VERSION 5.8 ;
BUSBITCHARS "[]" ;
DIVIDERCHAR "/" ;
UNITS
    DATABASE MICRONS 1000 ;
END UNITS

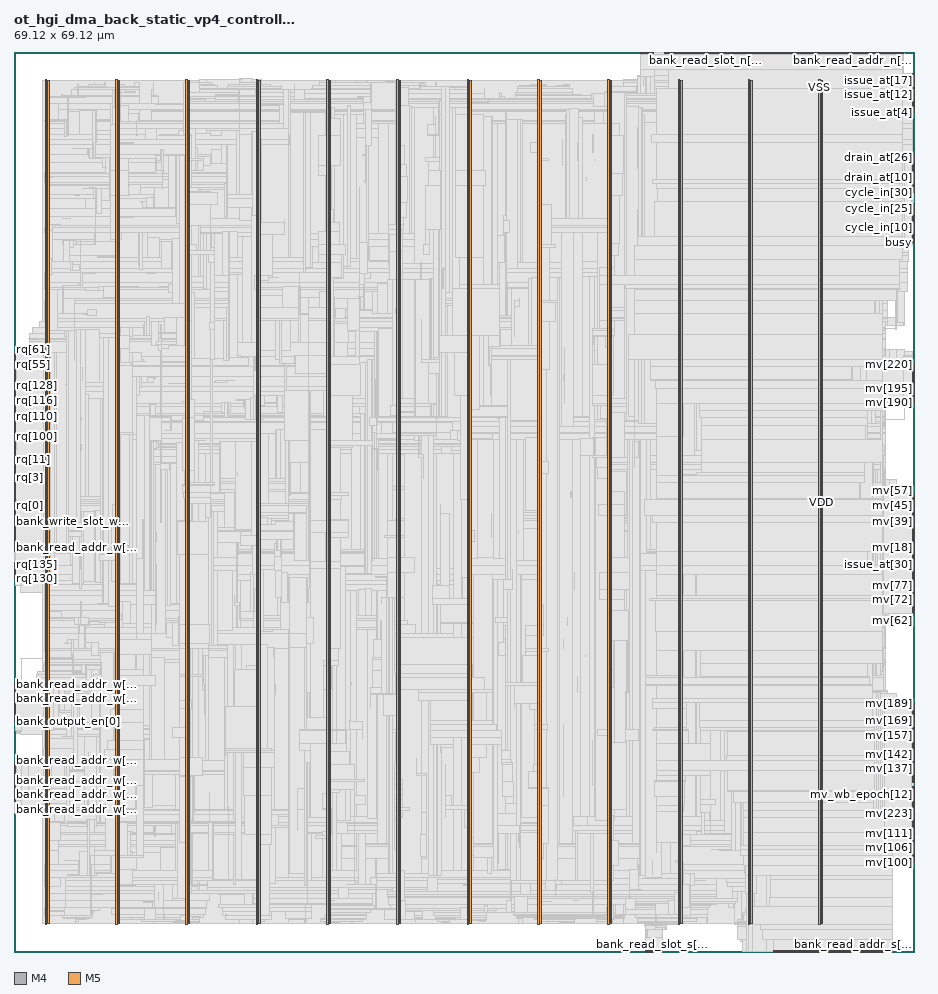
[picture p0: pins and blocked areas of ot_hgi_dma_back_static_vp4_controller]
MACRO ot_hgi_dma_back_static_vp4_controller
  FOREIGN ot_hgi_dma_back_static_vp4_controller 0 0 ;
  CLASS BLOCK ;
  SIZE 69.12 BY 69.12 ;
  PIN bank_output_en[0]
    DIRECTION OUTPUT ;
    USE SIGNAL ;
    PORT
      LAYER M4 ;
        RECT  0 17.712 0.084 17.736 ;
    END
  END bank_output_en[0]
  PIN bank_output_en[1]
    DIRECTION OUTPUT ;
    USE SIGNAL ;
    PORT
      LAYER M4 ;
        RECT  0 17.808 0.084 17.832 ;
    END
  END bank_output_en[1]
  PIN bank_output_en[2]
    DIRECTION OUTPUT ;
    USE SIGNAL ;
    PORT
      LAYER M4 ;
        RECT  0 17.904 0.084 17.928 ;
    END
  END bank_output_en[2]
  PIN bank_output_en[3]
    DIRECTION OUTPUT ;
    USE SIGNAL ;
    PORT
      LAYER M4 ;
        RECT  0 18 0.084 18.024 ;
    END
  END bank_output_en[3]
  PIN bank_output_en[4]
    DIRECTION OUTPUT ;
    USE SIGNAL ;
    PORT
      LAYER M4 ;
        RECT  0 18.096 0.084 18.12 ;
    END
  END bank_output_en[4]
  PIN bank_output_en[5]
    DIRECTION OUTPUT ;
    USE SIGNAL ;
    PORT
      LAYER M4 ;
        RECT  0 18.192 0.084 18.216 ;
    END
  END bank_output_en[5]
  PIN bank_output_en[6]
    DIRECTION OUTPUT ;
    USE SIGNAL ;
    PORT
      LAYER M4 ;
        RECT  0 18.288 0.084 18.312 ;
    END
  END bank_output_en[6]
  PIN bank_output_en[7]
    DIRECTION OUTPUT ;
    USE SIGNAL ;
    PORT
      LAYER M4 ;
        RECT  0 18.384 0.084 18.408 ;
    END
  END bank_output_en[7]
  PIN bank_read_addr_n[0]
    DIRECTION OUTPUT ;
    USE SIGNAL ;
    PORT
      LAYER M5 ;
        RECT  56.112 69.036 56.136 69.12 ;
    END
  END bank_read_addr_n[0]
  PIN bank_read_addr_n[10]
    DIRECTION OUTPUT ;
    USE SIGNAL ;
    PORT
      LAYER M5 ;
        RECT  57.072 69.036 57.096 69.12 ;
    END
  END bank_read_addr_n[10]
  PIN bank_read_addr_n[11]
    DIRECTION OUTPUT ;
    USE SIGNAL ;
    PORT
      LAYER M5 ;
        RECT  57.168 69.036 57.192 69.12 ;
    END
  END bank_read_addr_n[11]
  PIN bank_read_addr_n[12]
    DIRECTION OUTPUT ;
    USE SIGNAL ;
    PORT
      LAYER M5 ;
        RECT  57.264 69.036 57.288 69.12 ;
    END
  END bank_read_addr_n[12]
  PIN bank_read_addr_n[13]
    DIRECTION OUTPUT ;
    USE SIGNAL ;
    PORT
      LAYER M5 ;
        RECT  57.36 69.036 57.384 69.12 ;
    END
  END bank_read_addr_n[13]
  PIN bank_read_addr_n[14]
    DIRECTION OUTPUT ;
    USE SIGNAL ;
    PORT
      LAYER M5 ;
        RECT  57.456 69.036 57.48 69.12 ;
    END
  END bank_read_addr_n[14]
  PIN bank_read_addr_n[15]
    DIRECTION OUTPUT ;
    USE SIGNAL ;
    PORT
      LAYER M5 ;
        RECT  57.552 69.036 57.576 69.12 ;
    END
  END bank_read_addr_n[15]
  PIN bank_read_addr_n[16]
    DIRECTION OUTPUT ;
    USE SIGNAL ;
    PORT
      LAYER M5 ;
        RECT  57.648 69.036 57.672 69.12 ;
    END
  END bank_read_addr_n[16]
  PIN bank_read_addr_n[17]
    DIRECTION OUTPUT ;
    USE SIGNAL ;
    PORT
      LAYER M5 ;
        RECT  57.744 69.036 57.768 69.12 ;
    END
  END bank_read_addr_n[17]
  PIN bank_read_addr_n[18]
    DIRECTION OUTPUT ;
    USE SIGNAL ;
    PORT
      LAYER M5 ;
        RECT  57.84 69.036 57.864 69.12 ;
    END
  END bank_read_addr_n[18]
  PIN bank_read_addr_n[19]
    DIRECTION OUTPUT ;
    USE SIGNAL ;
    PORT
      LAYER M5 ;
        RECT  57.936 69.036 57.96 69.12 ;
    END
  END bank_read_addr_n[19]
  PIN bank_read_addr_n[1]
    DIRECTION OUTPUT ;
    USE SIGNAL ;
    PORT
      LAYER M5 ;
        RECT  56.208 69.036 56.232 69.12 ;
    END
  END bank_read_addr_n[1]
  PIN bank_read_addr_n[20]
    DIRECTION OUTPUT ;
    USE SIGNAL ;
    PORT
      LAYER M5 ;
        RECT  58.032 69.036 58.056 69.12 ;
    END
  END bank_read_addr_n[20]
  PIN bank_read_addr_n[21]
    DIRECTION OUTPUT ;
    USE SIGNAL ;
    PORT
      LAYER M5 ;
        RECT  58.128 69.036 58.152 69.12 ;
    END
  END bank_read_addr_n[21]
  PIN bank_read_addr_n[22]
    DIRECTION OUTPUT ;
    USE SIGNAL ;
    PORT
      LAYER M5 ;
        RECT  58.224 69.036 58.248 69.12 ;
    END
  END bank_read_addr_n[22]
  PIN bank_read_addr_n[23]
    DIRECTION OUTPUT ;
    USE SIGNAL ;
    PORT
      LAYER M5 ;
        RECT  58.32 69.036 58.344 69.12 ;
    END
  END bank_read_addr_n[23]
  PIN bank_read_addr_n[24]
    DIRECTION OUTPUT ;
    USE SIGNAL ;
    PORT
      LAYER M5 ;
        RECT  58.416 69.036 58.44 69.12 ;
    END
  END bank_read_addr_n[24]
  PIN bank_read_addr_n[25]
    DIRECTION OUTPUT ;
    USE SIGNAL ;
    PORT
      LAYER M5 ;
        RECT  58.512 69.036 58.536 69.12 ;
    END
  END bank_read_addr_n[25]
  PIN bank_read_addr_n[26]
    DIRECTION OUTPUT ;
    USE SIGNAL ;
    PORT
      LAYER M5 ;
        RECT  58.608 69.036 58.632 69.12 ;
    END
  END bank_read_addr_n[26]
  PIN bank_read_addr_n[27]
    DIRECTION OUTPUT ;
    USE SIGNAL ;
    PORT
      LAYER M5 ;
        RECT  58.704 69.036 58.728 69.12 ;
    END
  END bank_read_addr_n[27]
  PIN bank_read_addr_n[28]
    DIRECTION OUTPUT ;
    USE SIGNAL ;
    PORT
      LAYER M5 ;
        RECT  58.8 69.036 58.824 69.12 ;
    END
  END bank_read_addr_n[28]
  PIN bank_read_addr_n[29]
    DIRECTION OUTPUT ;
    USE SIGNAL ;
    PORT
      LAYER M5 ;
        RECT  58.896 69.036 58.92 69.12 ;
    END
  END bank_read_addr_n[29]
  PIN bank_read_addr_n[2]
    DIRECTION OUTPUT ;
    USE SIGNAL ;
    PORT
      LAYER M5 ;
        RECT  56.304 69.036 56.328 69.12 ;
    END
  END bank_read_addr_n[2]
  PIN bank_read_addr_n[30]
    DIRECTION OUTPUT ;
    USE SIGNAL ;
    PORT
      LAYER M5 ;
        RECT  58.992 69.036 59.016 69.12 ;
    END
  END bank_read_addr_n[30]
  PIN bank_read_addr_n[31]
    DIRECTION OUTPUT ;
    USE SIGNAL ;
    PORT
      LAYER M5 ;
        RECT  59.088 69.036 59.112 69.12 ;
    END
  END bank_read_addr_n[31]
  PIN bank_read_addr_n[32]
    DIRECTION OUTPUT ;
    USE SIGNAL ;
    PORT
      LAYER M5 ;
        RECT  62.256 69.036 62.28 69.12 ;
    END
  END bank_read_addr_n[32]
  PIN bank_read_addr_n[33]
    DIRECTION OUTPUT ;
    USE SIGNAL ;
    PORT
      LAYER M5 ;
        RECT  62.352 69.036 62.376 69.12 ;
    END
  END bank_read_addr_n[33]
  PIN bank_read_addr_n[34]
    DIRECTION OUTPUT ;
    USE SIGNAL ;
    PORT
      LAYER M5 ;
        RECT  62.448 69.036 62.472 69.12 ;
    END
  END bank_read_addr_n[34]
  PIN bank_read_addr_n[35]
    DIRECTION OUTPUT ;
    USE SIGNAL ;
    PORT
      LAYER M5 ;
        RECT  62.544 69.036 62.568 69.12 ;
    END
  END bank_read_addr_n[35]
  PIN bank_read_addr_n[36]
    DIRECTION OUTPUT ;
    USE SIGNAL ;
    PORT
      LAYER M5 ;
        RECT  62.64 69.036 62.664 69.12 ;
    END
  END bank_read_addr_n[36]
  PIN bank_read_addr_n[37]
    DIRECTION OUTPUT ;
    USE SIGNAL ;
    PORT
      LAYER M5 ;
        RECT  62.736 69.036 62.76 69.12 ;
    END
  END bank_read_addr_n[37]
  PIN bank_read_addr_n[38]
    DIRECTION OUTPUT ;
    USE SIGNAL ;
    PORT
      LAYER M5 ;
        RECT  62.832 69.036 62.856 69.12 ;
    END
  END bank_read_addr_n[38]
  PIN bank_read_addr_n[39]
    DIRECTION OUTPUT ;
    USE SIGNAL ;
    PORT
      LAYER M5 ;
        RECT  62.928 69.036 62.952 69.12 ;
    END
  END bank_read_addr_n[39]
  PIN bank_read_addr_n[3]
    DIRECTION OUTPUT ;
    USE SIGNAL ;
    PORT
      LAYER M5 ;
        RECT  56.4 69.036 56.424 69.12 ;
    END
  END bank_read_addr_n[3]
  PIN bank_read_addr_n[40]
    DIRECTION OUTPUT ;
    USE SIGNAL ;
    PORT
      LAYER M5 ;
        RECT  63.024 69.036 63.048 69.12 ;
    END
  END bank_read_addr_n[40]
  PIN bank_read_addr_n[41]
    DIRECTION OUTPUT ;
    USE SIGNAL ;
    PORT
      LAYER M5 ;
        RECT  63.12 69.036 63.144 69.12 ;
    END
  END bank_read_addr_n[41]
  PIN bank_read_addr_n[42]
    DIRECTION OUTPUT ;
    USE SIGNAL ;
    PORT
      LAYER M5 ;
        RECT  63.216 69.036 63.24 69.12 ;
    END
  END bank_read_addr_n[42]
  PIN bank_read_addr_n[43]
    DIRECTION OUTPUT ;
    USE SIGNAL ;
    PORT
      LAYER M5 ;
        RECT  63.312 69.036 63.336 69.12 ;
    END
  END bank_read_addr_n[43]
  PIN bank_read_addr_n[44]
    DIRECTION OUTPUT ;
    USE SIGNAL ;
    PORT
      LAYER M5 ;
        RECT  63.408 69.036 63.432 69.12 ;
    END
  END bank_read_addr_n[44]
  PIN bank_read_addr_n[45]
    DIRECTION OUTPUT ;
    USE SIGNAL ;
    PORT
      LAYER M5 ;
        RECT  63.504 69.036 63.528 69.12 ;
    END
  END bank_read_addr_n[45]
  PIN bank_read_addr_n[46]
    DIRECTION OUTPUT ;
    USE SIGNAL ;
    PORT
      LAYER M5 ;
        RECT  63.6 69.036 63.624 69.12 ;
    END
  END bank_read_addr_n[46]
  PIN bank_read_addr_n[47]
    DIRECTION OUTPUT ;
    USE SIGNAL ;
    PORT
      LAYER M5 ;
        RECT  63.696 69.036 63.72 69.12 ;
    END
  END bank_read_addr_n[47]
  PIN bank_read_addr_n[48]
    DIRECTION OUTPUT ;
    USE SIGNAL ;
    PORT
      LAYER M5 ;
        RECT  63.792 69.036 63.816 69.12 ;
    END
  END bank_read_addr_n[48]
  PIN bank_read_addr_n[49]
    DIRECTION OUTPUT ;
    USE SIGNAL ;
    PORT
      LAYER M5 ;
        RECT  63.888 69.036 63.912 69.12 ;
    END
  END bank_read_addr_n[49]
  PIN bank_read_addr_n[4]
    DIRECTION OUTPUT ;
    USE SIGNAL ;
    PORT
      LAYER M5 ;
        RECT  56.496 69.036 56.52 69.12 ;
    END
  END bank_read_addr_n[4]
  PIN bank_read_addr_n[50]
    DIRECTION OUTPUT ;
    USE SIGNAL ;
    PORT
      LAYER M5 ;
        RECT  63.984 69.036 64.008 69.12 ;
    END
  END bank_read_addr_n[50]
  PIN bank_read_addr_n[51]
    DIRECTION OUTPUT ;
    USE SIGNAL ;
    PORT
      LAYER M5 ;
        RECT  64.08 69.036 64.104 69.12 ;
    END
  END bank_read_addr_n[51]
  PIN bank_read_addr_n[52]
    DIRECTION OUTPUT ;
    USE SIGNAL ;
    PORT
      LAYER M5 ;
        RECT  64.176 69.036 64.2 69.12 ;
    END
  END bank_read_addr_n[52]
  PIN bank_read_addr_n[53]
    DIRECTION OUTPUT ;
    USE SIGNAL ;
    PORT
      LAYER M5 ;
        RECT  64.272 69.036 64.296 69.12 ;
    END
  END bank_read_addr_n[53]
  PIN bank_read_addr_n[54]
    DIRECTION OUTPUT ;
    USE SIGNAL ;
    PORT
      LAYER M5 ;
        RECT  64.368 69.036 64.392 69.12 ;
    END
  END bank_read_addr_n[54]
  PIN bank_read_addr_n[55]
    DIRECTION OUTPUT ;
    USE SIGNAL ;
    PORT
      LAYER M5 ;
        RECT  64.464 69.036 64.488 69.12 ;
    END
  END bank_read_addr_n[55]
  PIN bank_read_addr_n[56]
    DIRECTION OUTPUT ;
    USE SIGNAL ;
    PORT
      LAYER M5 ;
        RECT  64.56 69.036 64.584 69.12 ;
    END
  END bank_read_addr_n[56]
  PIN bank_read_addr_n[57]
    DIRECTION OUTPUT ;
    USE SIGNAL ;
    PORT
      LAYER M5 ;
        RECT  64.656 69.036 64.68 69.12 ;
    END
  END bank_read_addr_n[57]
  PIN bank_read_addr_n[58]
    DIRECTION OUTPUT ;
    USE SIGNAL ;
    PORT
      LAYER M5 ;
        RECT  64.752 69.036 64.776 69.12 ;
    END
  END bank_read_addr_n[58]
  PIN bank_read_addr_n[59]
    DIRECTION OUTPUT ;
    USE SIGNAL ;
    PORT
      LAYER M5 ;
        RECT  64.848 69.036 64.872 69.12 ;
    END
  END bank_read_addr_n[59]
  PIN bank_read_addr_n[5]
    DIRECTION OUTPUT ;
    USE SIGNAL ;
    PORT
      LAYER M5 ;
        RECT  56.592 69.036 56.616 69.12 ;
    END
  END bank_read_addr_n[5]
  PIN bank_read_addr_n[60]
    DIRECTION OUTPUT ;
    USE SIGNAL ;
    PORT
      LAYER M5 ;
        RECT  64.944 69.036 64.968 69.12 ;
    END
  END bank_read_addr_n[60]
  PIN bank_read_addr_n[61]
    DIRECTION OUTPUT ;
    USE SIGNAL ;
    PORT
      LAYER M5 ;
        RECT  65.04 69.036 65.064 69.12 ;
    END
  END bank_read_addr_n[61]
  PIN bank_read_addr_n[62]
    DIRECTION OUTPUT ;
    USE SIGNAL ;
    PORT
      LAYER M5 ;
        RECT  65.136 69.036 65.16 69.12 ;
    END
  END bank_read_addr_n[62]
  PIN bank_read_addr_n[63]
    DIRECTION OUTPUT ;
    USE SIGNAL ;
    PORT
      LAYER M5 ;
        RECT  65.232 69.036 65.256 69.12 ;
    END
  END bank_read_addr_n[63]
  PIN bank_read_addr_n[64]
    DIRECTION OUTPUT ;
    USE SIGNAL ;
    PORT
      LAYER M5 ;
        RECT  59.184 69.036 59.208 69.12 ;
    END
  END bank_read_addr_n[64]
  PIN bank_read_addr_n[65]
    DIRECTION OUTPUT ;
    USE SIGNAL ;
    PORT
      LAYER M5 ;
        RECT  59.28 69.036 59.304 69.12 ;
    END
  END bank_read_addr_n[65]
  PIN bank_read_addr_n[66]
    DIRECTION OUTPUT ;
    USE SIGNAL ;
    PORT
      LAYER M5 ;
        RECT  59.376 69.036 59.4 69.12 ;
    END
  END bank_read_addr_n[66]
  PIN bank_read_addr_n[67]
    DIRECTION OUTPUT ;
    USE SIGNAL ;
    PORT
      LAYER M5 ;
        RECT  59.472 69.036 59.496 69.12 ;
    END
  END bank_read_addr_n[67]
  PIN bank_read_addr_n[68]
    DIRECTION OUTPUT ;
    USE SIGNAL ;
    PORT
      LAYER M5 ;
        RECT  59.568 69.036 59.592 69.12 ;
    END
  END bank_read_addr_n[68]
  PIN bank_read_addr_n[69]
    DIRECTION OUTPUT ;
    USE SIGNAL ;
    PORT
      LAYER M5 ;
        RECT  59.664 69.036 59.688 69.12 ;
    END
  END bank_read_addr_n[69]
  PIN bank_read_addr_n[6]
    DIRECTION OUTPUT ;
    USE SIGNAL ;
    PORT
      LAYER M5 ;
        RECT  56.688 69.036 56.712 69.12 ;
    END
  END bank_read_addr_n[6]
  PIN bank_read_addr_n[70]
    DIRECTION OUTPUT ;
    USE SIGNAL ;
    PORT
      LAYER M5 ;
        RECT  59.76 69.036 59.784 69.12 ;
    END
  END bank_read_addr_n[70]
  PIN bank_read_addr_n[71]
    DIRECTION OUTPUT ;
    USE SIGNAL ;
    PORT
      LAYER M5 ;
        RECT  59.856 69.036 59.88 69.12 ;
    END
  END bank_read_addr_n[71]
  PIN bank_read_addr_n[72]
    DIRECTION OUTPUT ;
    USE SIGNAL ;
    PORT
      LAYER M5 ;
        RECT  59.952 69.036 59.976 69.12 ;
    END
  END bank_read_addr_n[72]
  PIN bank_read_addr_n[73]
    DIRECTION OUTPUT ;
    USE SIGNAL ;
    PORT
      LAYER M5 ;
        RECT  60.048 69.036 60.072 69.12 ;
    END
  END bank_read_addr_n[73]
  PIN bank_read_addr_n[74]
    DIRECTION OUTPUT ;
    USE SIGNAL ;
    PORT
      LAYER M5 ;
        RECT  60.144 69.036 60.168 69.12 ;
    END
  END bank_read_addr_n[74]
  PIN bank_read_addr_n[75]
    DIRECTION OUTPUT ;
    USE SIGNAL ;
    PORT
      LAYER M5 ;
        RECT  60.24 69.036 60.264 69.12 ;
    END
  END bank_read_addr_n[75]
  PIN bank_read_addr_n[76]
    DIRECTION OUTPUT ;
    USE SIGNAL ;
    PORT
      LAYER M5 ;
        RECT  60.336 69.036 60.36 69.12 ;
    END
  END bank_read_addr_n[76]
  PIN bank_read_addr_n[77]
    DIRECTION OUTPUT ;
    USE SIGNAL ;
    PORT
      LAYER M5 ;
        RECT  60.432 69.036 60.456 69.12 ;
    END
  END bank_read_addr_n[77]
  PIN bank_read_addr_n[78]
    DIRECTION OUTPUT ;
    USE SIGNAL ;
    PORT
      LAYER M5 ;
        RECT  60.528 69.036 60.552 69.12 ;
    END
  END bank_read_addr_n[78]
  PIN bank_read_addr_n[79]
    DIRECTION OUTPUT ;
    USE SIGNAL ;
    PORT
      LAYER M5 ;
        RECT  60.624 69.036 60.648 69.12 ;
    END
  END bank_read_addr_n[79]
  PIN bank_read_addr_n[7]
    DIRECTION OUTPUT ;
    USE SIGNAL ;
    PORT
      LAYER M5 ;
        RECT  56.784 69.036 56.808 69.12 ;
    END
  END bank_read_addr_n[7]
  PIN bank_read_addr_n[80]
    DIRECTION OUTPUT ;
    USE SIGNAL ;
    PORT
      LAYER M5 ;
        RECT  60.72 69.036 60.744 69.12 ;
    END
  END bank_read_addr_n[80]
  PIN bank_read_addr_n[81]
    DIRECTION OUTPUT ;
    USE SIGNAL ;
    PORT
      LAYER M5 ;
        RECT  60.816 69.036 60.84 69.12 ;
    END
  END bank_read_addr_n[81]
  PIN bank_read_addr_n[82]
    DIRECTION OUTPUT ;
    USE SIGNAL ;
    PORT
      LAYER M5 ;
        RECT  60.912 69.036 60.936 69.12 ;
    END
  END bank_read_addr_n[82]
  PIN bank_read_addr_n[83]
    DIRECTION OUTPUT ;
    USE SIGNAL ;
    PORT
      LAYER M5 ;
        RECT  61.008 69.036 61.032 69.12 ;
    END
  END bank_read_addr_n[83]
  PIN bank_read_addr_n[84]
    DIRECTION OUTPUT ;
    USE SIGNAL ;
    PORT
      LAYER M5 ;
        RECT  61.104 69.036 61.128 69.12 ;
    END
  END bank_read_addr_n[84]
  PIN bank_read_addr_n[85]
    DIRECTION OUTPUT ;
    USE SIGNAL ;
    PORT
      LAYER M5 ;
        RECT  61.2 69.036 61.224 69.12 ;
    END
  END bank_read_addr_n[85]
  PIN bank_read_addr_n[86]
    DIRECTION OUTPUT ;
    USE SIGNAL ;
    PORT
      LAYER M5 ;
        RECT  61.296 69.036 61.32 69.12 ;
    END
  END bank_read_addr_n[86]
  PIN bank_read_addr_n[87]
    DIRECTION OUTPUT ;
    USE SIGNAL ;
    PORT
      LAYER M5 ;
        RECT  61.392 69.036 61.416 69.12 ;
    END
  END bank_read_addr_n[87]
  PIN bank_read_addr_n[88]
    DIRECTION OUTPUT ;
    USE SIGNAL ;
    PORT
      LAYER M5 ;
        RECT  61.488 69.036 61.512 69.12 ;
    END
  END bank_read_addr_n[88]
  PIN bank_read_addr_n[89]
    DIRECTION OUTPUT ;
    USE SIGNAL ;
    PORT
      LAYER M5 ;
        RECT  61.584 69.036 61.608 69.12 ;
    END
  END bank_read_addr_n[89]
  PIN bank_read_addr_n[8]
    DIRECTION OUTPUT ;
    USE SIGNAL ;
    PORT
      LAYER M5 ;
        RECT  56.88 69.036 56.904 69.12 ;
    END
  END bank_read_addr_n[8]
  PIN bank_read_addr_n[90]
    DIRECTION OUTPUT ;
    USE SIGNAL ;
    PORT
      LAYER M5 ;
        RECT  61.68 69.036 61.704 69.12 ;
    END
  END bank_read_addr_n[90]
  PIN bank_read_addr_n[91]
    DIRECTION OUTPUT ;
    USE SIGNAL ;
    PORT
      LAYER M5 ;
        RECT  61.776 69.036 61.8 69.12 ;
    END
  END bank_read_addr_n[91]
  PIN bank_read_addr_n[92]
    DIRECTION OUTPUT ;
    USE SIGNAL ;
    PORT
      LAYER M5 ;
        RECT  61.872 69.036 61.896 69.12 ;
    END
  END bank_read_addr_n[92]
  PIN bank_read_addr_n[93]
    DIRECTION OUTPUT ;
    USE SIGNAL ;
    PORT
      LAYER M5 ;
        RECT  61.968 69.036 61.992 69.12 ;
    END
  END bank_read_addr_n[93]
  PIN bank_read_addr_n[94]
    DIRECTION OUTPUT ;
    USE SIGNAL ;
    PORT
      LAYER M5 ;
        RECT  62.064 69.036 62.088 69.12 ;
    END
  END bank_read_addr_n[94]
  PIN bank_read_addr_n[95]
    DIRECTION OUTPUT ;
    USE SIGNAL ;
    PORT
      LAYER M5 ;
        RECT  62.16 69.036 62.184 69.12 ;
    END
  END bank_read_addr_n[95]
  PIN bank_read_addr_n[9]
    DIRECTION OUTPUT ;
    USE SIGNAL ;
    PORT
      LAYER M5 ;
        RECT  56.976 69.036 57 69.12 ;
    END
  END bank_read_addr_n[9]
  PIN bank_read_addr_s[0]
    DIRECTION OUTPUT ;
    USE SIGNAL ;
    PORT
      LAYER M5 ;
        RECT  61.392 0 61.416 0.084 ;
    END
  END bank_read_addr_s[0]
  PIN bank_read_addr_s[10]
    DIRECTION OUTPUT ;
    USE SIGNAL ;
    PORT
      LAYER M5 ;
        RECT  62.352 0 62.376 0.084 ;
    END
  END bank_read_addr_s[10]
  PIN bank_read_addr_s[11]
    DIRECTION OUTPUT ;
    USE SIGNAL ;
    PORT
      LAYER M5 ;
        RECT  62.448 0 62.472 0.084 ;
    END
  END bank_read_addr_s[11]
  PIN bank_read_addr_s[12]
    DIRECTION OUTPUT ;
    USE SIGNAL ;
    PORT
      LAYER M5 ;
        RECT  62.544 0 62.568 0.084 ;
    END
  END bank_read_addr_s[12]
  PIN bank_read_addr_s[13]
    DIRECTION OUTPUT ;
    USE SIGNAL ;
    PORT
      LAYER M5 ;
        RECT  62.64 0 62.664 0.084 ;
    END
  END bank_read_addr_s[13]
  PIN bank_read_addr_s[14]
    DIRECTION OUTPUT ;
    USE SIGNAL ;
    PORT
      LAYER M5 ;
        RECT  62.736 0 62.76 0.084 ;
    END
  END bank_read_addr_s[14]
  PIN bank_read_addr_s[15]
    DIRECTION OUTPUT ;
    USE SIGNAL ;
    PORT
      LAYER M5 ;
        RECT  62.832 0 62.856 0.084 ;
    END
  END bank_read_addr_s[15]
  PIN bank_read_addr_s[16]
    DIRECTION OUTPUT ;
    USE SIGNAL ;
    PORT
      LAYER M5 ;
        RECT  62.928 0 62.952 0.084 ;
    END
  END bank_read_addr_s[16]
  PIN bank_read_addr_s[17]
    DIRECTION OUTPUT ;
    USE SIGNAL ;
    PORT
      LAYER M5 ;
        RECT  63.024 0 63.048 0.084 ;
    END
  END bank_read_addr_s[17]
  PIN bank_read_addr_s[18]
    DIRECTION OUTPUT ;
    USE SIGNAL ;
    PORT
      LAYER M5 ;
        RECT  63.12 0 63.144 0.084 ;
    END
  END bank_read_addr_s[18]
  PIN bank_read_addr_s[19]
    DIRECTION OUTPUT ;
    USE SIGNAL ;
    PORT
      LAYER M5 ;
        RECT  63.216 0 63.24 0.084 ;
    END
  END bank_read_addr_s[19]
  PIN bank_read_addr_s[1]
    DIRECTION OUTPUT ;
    USE SIGNAL ;
    PORT
      LAYER M5 ;
        RECT  61.488 0 61.512 0.084 ;
    END
  END bank_read_addr_s[1]
  PIN bank_read_addr_s[20]
    DIRECTION OUTPUT ;
    USE SIGNAL ;
    PORT
      LAYER M5 ;
        RECT  63.312 0 63.336 0.084 ;
    END
  END bank_read_addr_s[20]
  PIN bank_read_addr_s[21]
    DIRECTION OUTPUT ;
    USE SIGNAL ;
    PORT
      LAYER M5 ;
        RECT  63.408 0 63.432 0.084 ;
    END
  END bank_read_addr_s[21]
  PIN bank_read_addr_s[22]
    DIRECTION OUTPUT ;
    USE SIGNAL ;
    PORT
      LAYER M5 ;
        RECT  63.504 0 63.528 0.084 ;
    END
  END bank_read_addr_s[22]
  PIN bank_read_addr_s[23]
    DIRECTION OUTPUT ;
    USE SIGNAL ;
    PORT
      LAYER M5 ;
        RECT  63.6 0 63.624 0.084 ;
    END
  END bank_read_addr_s[23]
  PIN bank_read_addr_s[24]
    DIRECTION OUTPUT ;
    USE SIGNAL ;
    PORT
      LAYER M5 ;
        RECT  63.696 0 63.72 0.084 ;
    END
  END bank_read_addr_s[24]
  PIN bank_read_addr_s[25]
    DIRECTION OUTPUT ;
    USE SIGNAL ;
    PORT
      LAYER M5 ;
        RECT  63.792 0 63.816 0.084 ;
    END
  END bank_read_addr_s[25]
  PIN bank_read_addr_s[26]
    DIRECTION OUTPUT ;
    USE SIGNAL ;
    PORT
      LAYER M5 ;
        RECT  63.888 0 63.912 0.084 ;
    END
  END bank_read_addr_s[26]
  PIN bank_read_addr_s[27]
    DIRECTION OUTPUT ;
    USE SIGNAL ;
    PORT
      LAYER M5 ;
        RECT  63.984 0 64.008 0.084 ;
    END
  END bank_read_addr_s[27]
  PIN bank_read_addr_s[28]
    DIRECTION OUTPUT ;
    USE SIGNAL ;
    PORT
      LAYER M5 ;
        RECT  64.08 0 64.104 0.084 ;
    END
  END bank_read_addr_s[28]
  PIN bank_read_addr_s[29]
    DIRECTION OUTPUT ;
    USE SIGNAL ;
    PORT
      LAYER M5 ;
        RECT  64.176 0 64.2 0.084 ;
    END
  END bank_read_addr_s[29]
  PIN bank_read_addr_s[2]
    DIRECTION OUTPUT ;
    USE SIGNAL ;
    PORT
      LAYER M5 ;
        RECT  61.584 0 61.608 0.084 ;
    END
  END bank_read_addr_s[2]
  PIN bank_read_addr_s[30]
    DIRECTION OUTPUT ;
    USE SIGNAL ;
    PORT
      LAYER M5 ;
        RECT  64.272 0 64.296 0.084 ;
    END
  END bank_read_addr_s[30]
  PIN bank_read_addr_s[31]
    DIRECTION OUTPUT ;
    USE SIGNAL ;
    PORT
      LAYER M5 ;
        RECT  64.368 0 64.392 0.084 ;
    END
  END bank_read_addr_s[31]
  PIN bank_read_addr_s[32]
    DIRECTION OUTPUT ;
    USE SIGNAL ;
    PORT
      LAYER M5 ;
        RECT  64.464 0 64.488 0.084 ;
    END
  END bank_read_addr_s[32]
  PIN bank_read_addr_s[33]
    DIRECTION OUTPUT ;
    USE SIGNAL ;
    PORT
      LAYER M5 ;
        RECT  64.56 0 64.584 0.084 ;
    END
  END bank_read_addr_s[33]
  PIN bank_read_addr_s[34]
    DIRECTION OUTPUT ;
    USE SIGNAL ;
    PORT
      LAYER M5 ;
        RECT  64.656 0 64.68 0.084 ;
    END
  END bank_read_addr_s[34]
  PIN bank_read_addr_s[35]
    DIRECTION OUTPUT ;
    USE SIGNAL ;
    PORT
      LAYER M5 ;
        RECT  64.752 0 64.776 0.084 ;
    END
  END bank_read_addr_s[35]
  PIN bank_read_addr_s[36]
    DIRECTION OUTPUT ;
    USE SIGNAL ;
    PORT
      LAYER M5 ;
        RECT  64.848 0 64.872 0.084 ;
    END
  END bank_read_addr_s[36]
  PIN bank_read_addr_s[37]
    DIRECTION OUTPUT ;
    USE SIGNAL ;
    PORT
      LAYER M5 ;
        RECT  64.944 0 64.968 0.084 ;
    END
  END bank_read_addr_s[37]
  PIN bank_read_addr_s[38]
    DIRECTION OUTPUT ;
    USE SIGNAL ;
    PORT
      LAYER M5 ;
        RECT  65.04 0 65.064 0.084 ;
    END
  END bank_read_addr_s[38]
  PIN bank_read_addr_s[39]
    DIRECTION OUTPUT ;
    USE SIGNAL ;
    PORT
      LAYER M5 ;
        RECT  65.136 0 65.16 0.084 ;
    END
  END bank_read_addr_s[39]
  PIN bank_read_addr_s[3]
    DIRECTION OUTPUT ;
    USE SIGNAL ;
    PORT
      LAYER M5 ;
        RECT  61.68 0 61.704 0.084 ;
    END
  END bank_read_addr_s[3]
  PIN bank_read_addr_s[40]
    DIRECTION OUTPUT ;
    USE SIGNAL ;
    PORT
      LAYER M5 ;
        RECT  65.232 0 65.256 0.084 ;
    END
  END bank_read_addr_s[40]
  PIN bank_read_addr_s[41]
    DIRECTION OUTPUT ;
    USE SIGNAL ;
    PORT
      LAYER M5 ;
        RECT  65.328 0 65.352 0.084 ;
    END
  END bank_read_addr_s[41]
  PIN bank_read_addr_s[42]
    DIRECTION OUTPUT ;
    USE SIGNAL ;
    PORT
      LAYER M5 ;
        RECT  65.424 0 65.448 0.084 ;
    END
  END bank_read_addr_s[42]
  PIN bank_read_addr_s[43]
    DIRECTION OUTPUT ;
    USE SIGNAL ;
    PORT
      LAYER M5 ;
        RECT  65.52 0 65.544 0.084 ;
    END
  END bank_read_addr_s[43]
  PIN bank_read_addr_s[44]
    DIRECTION OUTPUT ;
    USE SIGNAL ;
    PORT
      LAYER M5 ;
        RECT  65.616 0 65.64 0.084 ;
    END
  END bank_read_addr_s[44]
  PIN bank_read_addr_s[45]
    DIRECTION OUTPUT ;
    USE SIGNAL ;
    PORT
      LAYER M5 ;
        RECT  65.712 0 65.736 0.084 ;
    END
  END bank_read_addr_s[45]
  PIN bank_read_addr_s[46]
    DIRECTION OUTPUT ;
    USE SIGNAL ;
    PORT
      LAYER M5 ;
        RECT  65.808 0 65.832 0.084 ;
    END
  END bank_read_addr_s[46]
  PIN bank_read_addr_s[47]
    DIRECTION OUTPUT ;
    USE SIGNAL ;
    PORT
      LAYER M5 ;
        RECT  65.904 0 65.928 0.084 ;
    END
  END bank_read_addr_s[47]
  PIN bank_read_addr_s[48]
    DIRECTION OUTPUT ;
    USE SIGNAL ;
    PORT
      LAYER M5 ;
        RECT  66 0 66.024 0.084 ;
    END
  END bank_read_addr_s[48]
  PIN bank_read_addr_s[49]
    DIRECTION OUTPUT ;
    USE SIGNAL ;
    PORT
      LAYER M5 ;
        RECT  66.096 0 66.12 0.084 ;
    END
  END bank_read_addr_s[49]
  PIN bank_read_addr_s[4]
    DIRECTION OUTPUT ;
    USE SIGNAL ;
    PORT
      LAYER M5 ;
        RECT  61.776 0 61.8 0.084 ;
    END
  END bank_read_addr_s[4]
  PIN bank_read_addr_s[50]
    DIRECTION OUTPUT ;
    USE SIGNAL ;
    PORT
      LAYER M5 ;
        RECT  66.192 0 66.216 0.084 ;
    END
  END bank_read_addr_s[50]
  PIN bank_read_addr_s[51]
    DIRECTION OUTPUT ;
    USE SIGNAL ;
    PORT
      LAYER M5 ;
        RECT  66.288 0 66.312 0.084 ;
    END
  END bank_read_addr_s[51]
  PIN bank_read_addr_s[52]
    DIRECTION OUTPUT ;
    USE SIGNAL ;
    PORT
      LAYER M5 ;
        RECT  66.384 0 66.408 0.084 ;
    END
  END bank_read_addr_s[52]
  PIN bank_read_addr_s[53]
    DIRECTION OUTPUT ;
    USE SIGNAL ;
    PORT
      LAYER M5 ;
        RECT  66.48 0 66.504 0.084 ;
    END
  END bank_read_addr_s[53]
  PIN bank_read_addr_s[54]
    DIRECTION OUTPUT ;
    USE SIGNAL ;
    PORT
      LAYER M5 ;
        RECT  66.576 0 66.6 0.084 ;
    END
  END bank_read_addr_s[54]
  PIN bank_read_addr_s[55]
    DIRECTION OUTPUT ;
    USE SIGNAL ;
    PORT
      LAYER M5 ;
        RECT  66.672 0 66.696 0.084 ;
    END
  END bank_read_addr_s[55]
  PIN bank_read_addr_s[56]
    DIRECTION OUTPUT ;
    USE SIGNAL ;
    PORT
      LAYER M5 ;
        RECT  66.768 0 66.792 0.084 ;
    END
  END bank_read_addr_s[56]
  PIN bank_read_addr_s[57]
    DIRECTION OUTPUT ;
    USE SIGNAL ;
    PORT
      LAYER M5 ;
        RECT  66.864 0 66.888 0.084 ;
    END
  END bank_read_addr_s[57]
  PIN bank_read_addr_s[58]
    DIRECTION OUTPUT ;
    USE SIGNAL ;
    PORT
      LAYER M5 ;
        RECT  66.96 0 66.984 0.084 ;
    END
  END bank_read_addr_s[58]
  PIN bank_read_addr_s[59]
    DIRECTION OUTPUT ;
    USE SIGNAL ;
    PORT
      LAYER M5 ;
        RECT  67.056 0 67.08 0.084 ;
    END
  END bank_read_addr_s[59]
  PIN bank_read_addr_s[5]
    DIRECTION OUTPUT ;
    USE SIGNAL ;
    PORT
      LAYER M5 ;
        RECT  61.872 0 61.896 0.084 ;
    END
  END bank_read_addr_s[5]
  PIN bank_read_addr_s[60]
    DIRECTION OUTPUT ;
    USE SIGNAL ;
    PORT
      LAYER M5 ;
        RECT  67.152 0 67.176 0.084 ;
    END
  END bank_read_addr_s[60]
  PIN bank_read_addr_s[61]
    DIRECTION OUTPUT ;
    USE SIGNAL ;
    PORT
      LAYER M5 ;
        RECT  67.248 0 67.272 0.084 ;
    END
  END bank_read_addr_s[61]
  PIN bank_read_addr_s[62]
    DIRECTION OUTPUT ;
    USE SIGNAL ;
    PORT
      LAYER M5 ;
        RECT  67.344 0 67.368 0.084 ;
    END
  END bank_read_addr_s[62]
  PIN bank_read_addr_s[63]
    DIRECTION OUTPUT ;
    USE SIGNAL ;
    PORT
      LAYER M5 ;
        RECT  67.44 0 67.464 0.084 ;
    END
  END bank_read_addr_s[63]
  PIN bank_read_addr_s[64]
    DIRECTION OUTPUT ;
    USE SIGNAL ;
    PORT
      LAYER M5 ;
        RECT  58.32 0 58.344 0.084 ;
    END
  END bank_read_addr_s[64]
  PIN bank_read_addr_s[65]
    DIRECTION OUTPUT ;
    USE SIGNAL ;
    PORT
      LAYER M5 ;
        RECT  58.416 0 58.44 0.084 ;
    END
  END bank_read_addr_s[65]
  PIN bank_read_addr_s[66]
    DIRECTION OUTPUT ;
    USE SIGNAL ;
    PORT
      LAYER M5 ;
        RECT  58.512 0 58.536 0.084 ;
    END
  END bank_read_addr_s[66]
  PIN bank_read_addr_s[67]
    DIRECTION OUTPUT ;
    USE SIGNAL ;
    PORT
      LAYER M5 ;
        RECT  58.608 0 58.632 0.084 ;
    END
  END bank_read_addr_s[67]
  PIN bank_read_addr_s[68]
    DIRECTION OUTPUT ;
    USE SIGNAL ;
    PORT
      LAYER M5 ;
        RECT  58.704 0 58.728 0.084 ;
    END
  END bank_read_addr_s[68]
  PIN bank_read_addr_s[69]
    DIRECTION OUTPUT ;
    USE SIGNAL ;
    PORT
      LAYER M5 ;
        RECT  58.8 0 58.824 0.084 ;
    END
  END bank_read_addr_s[69]
  PIN bank_read_addr_s[6]
    DIRECTION OUTPUT ;
    USE SIGNAL ;
    PORT
      LAYER M5 ;
        RECT  61.968 0 61.992 0.084 ;
    END
  END bank_read_addr_s[6]
  PIN bank_read_addr_s[70]
    DIRECTION OUTPUT ;
    USE SIGNAL ;
    PORT
      LAYER M5 ;
        RECT  58.896 0 58.92 0.084 ;
    END
  END bank_read_addr_s[70]
  PIN bank_read_addr_s[71]
    DIRECTION OUTPUT ;
    USE SIGNAL ;
    PORT
      LAYER M5 ;
        RECT  58.992 0 59.016 0.084 ;
    END
  END bank_read_addr_s[71]
  PIN bank_read_addr_s[72]
    DIRECTION OUTPUT ;
    USE SIGNAL ;
    PORT
      LAYER M5 ;
        RECT  59.088 0 59.112 0.084 ;
    END
  END bank_read_addr_s[72]
  PIN bank_read_addr_s[73]
    DIRECTION OUTPUT ;
    USE SIGNAL ;
    PORT
      LAYER M5 ;
        RECT  59.184 0 59.208 0.084 ;
    END
  END bank_read_addr_s[73]
  PIN bank_read_addr_s[74]
    DIRECTION OUTPUT ;
    USE SIGNAL ;
    PORT
      LAYER M5 ;
        RECT  59.28 0 59.304 0.084 ;
    END
  END bank_read_addr_s[74]
  PIN bank_read_addr_s[75]
    DIRECTION OUTPUT ;
    USE SIGNAL ;
    PORT
      LAYER M5 ;
        RECT  59.376 0 59.4 0.084 ;
    END
  END bank_read_addr_s[75]
  PIN bank_read_addr_s[76]
    DIRECTION OUTPUT ;
    USE SIGNAL ;
    PORT
      LAYER M5 ;
        RECT  59.472 0 59.496 0.084 ;
    END
  END bank_read_addr_s[76]
  PIN bank_read_addr_s[77]
    DIRECTION OUTPUT ;
    USE SIGNAL ;
    PORT
      LAYER M5 ;
        RECT  59.568 0 59.592 0.084 ;
    END
  END bank_read_addr_s[77]
  PIN bank_read_addr_s[78]
    DIRECTION OUTPUT ;
    USE SIGNAL ;
    PORT
      LAYER M5 ;
        RECT  59.664 0 59.688 0.084 ;
    END
  END bank_read_addr_s[78]
  PIN bank_read_addr_s[79]
    DIRECTION OUTPUT ;
    USE SIGNAL ;
    PORT
      LAYER M5 ;
        RECT  59.76 0 59.784 0.084 ;
    END
  END bank_read_addr_s[79]
  PIN bank_read_addr_s[7]
    DIRECTION OUTPUT ;
    USE SIGNAL ;
    PORT
      LAYER M5 ;
        RECT  62.064 0 62.088 0.084 ;
    END
  END bank_read_addr_s[7]
  PIN bank_read_addr_s[80]
    DIRECTION OUTPUT ;
    USE SIGNAL ;
    PORT
      LAYER M5 ;
        RECT  59.856 0 59.88 0.084 ;
    END
  END bank_read_addr_s[80]
  PIN bank_read_addr_s[81]
    DIRECTION OUTPUT ;
    USE SIGNAL ;
    PORT
      LAYER M5 ;
        RECT  59.952 0 59.976 0.084 ;
    END
  END bank_read_addr_s[81]
  PIN bank_read_addr_s[82]
    DIRECTION OUTPUT ;
    USE SIGNAL ;
    PORT
      LAYER M5 ;
        RECT  60.048 0 60.072 0.084 ;
    END
  END bank_read_addr_s[82]
  PIN bank_read_addr_s[83]
    DIRECTION OUTPUT ;
    USE SIGNAL ;
    PORT
      LAYER M5 ;
        RECT  60.144 0 60.168 0.084 ;
    END
  END bank_read_addr_s[83]
  PIN bank_read_addr_s[84]
    DIRECTION OUTPUT ;
    USE SIGNAL ;
    PORT
      LAYER M5 ;
        RECT  60.24 0 60.264 0.084 ;
    END
  END bank_read_addr_s[84]
  PIN bank_read_addr_s[85]
    DIRECTION OUTPUT ;
    USE SIGNAL ;
    PORT
      LAYER M5 ;
        RECT  60.336 0 60.36 0.084 ;
    END
  END bank_read_addr_s[85]
  PIN bank_read_addr_s[86]
    DIRECTION OUTPUT ;
    USE SIGNAL ;
    PORT
      LAYER M5 ;
        RECT  60.432 0 60.456 0.084 ;
    END
  END bank_read_addr_s[86]
  PIN bank_read_addr_s[87]
    DIRECTION OUTPUT ;
    USE SIGNAL ;
    PORT
      LAYER M5 ;
        RECT  60.528 0 60.552 0.084 ;
    END
  END bank_read_addr_s[87]
  PIN bank_read_addr_s[88]
    DIRECTION OUTPUT ;
    USE SIGNAL ;
    PORT
      LAYER M5 ;
        RECT  60.624 0 60.648 0.084 ;
    END
  END bank_read_addr_s[88]
  PIN bank_read_addr_s[89]
    DIRECTION OUTPUT ;
    USE SIGNAL ;
    PORT
      LAYER M5 ;
        RECT  60.72 0 60.744 0.084 ;
    END
  END bank_read_addr_s[89]
  PIN bank_read_addr_s[8]
    DIRECTION OUTPUT ;
    USE SIGNAL ;
    PORT
      LAYER M5 ;
        RECT  62.16 0 62.184 0.084 ;
    END
  END bank_read_addr_s[8]
  PIN bank_read_addr_s[90]
    DIRECTION OUTPUT ;
    USE SIGNAL ;
    PORT
      LAYER M5 ;
        RECT  60.816 0 60.84 0.084 ;
    END
  END bank_read_addr_s[90]
  PIN bank_read_addr_s[91]
    DIRECTION OUTPUT ;
    USE SIGNAL ;
    PORT
      LAYER M5 ;
        RECT  60.912 0 60.936 0.084 ;
    END
  END bank_read_addr_s[91]
  PIN bank_read_addr_s[92]
    DIRECTION OUTPUT ;
    USE SIGNAL ;
    PORT
      LAYER M5 ;
        RECT  61.008 0 61.032 0.084 ;
    END
  END bank_read_addr_s[92]
  PIN bank_read_addr_s[93]
    DIRECTION OUTPUT ;
    USE SIGNAL ;
    PORT
      LAYER M5 ;
        RECT  61.104 0 61.128 0.084 ;
    END
  END bank_read_addr_s[93]
  PIN bank_read_addr_s[94]
    DIRECTION OUTPUT ;
    USE SIGNAL ;
    PORT
      LAYER M5 ;
        RECT  61.2 0 61.224 0.084 ;
    END
  END bank_read_addr_s[94]
  PIN bank_read_addr_s[95]
    DIRECTION OUTPUT ;
    USE SIGNAL ;
    PORT
      LAYER M5 ;
        RECT  61.296 0 61.32 0.084 ;
    END
  END bank_read_addr_s[95]
  PIN bank_read_addr_s[9]
    DIRECTION OUTPUT ;
    USE SIGNAL ;
    PORT
      LAYER M5 ;
        RECT  62.256 0 62.28 0.084 ;
    END
  END bank_read_addr_s[9]
  PIN bank_read_addr_w[0]
    DIRECTION OUTPUT ;
    USE SIGNAL ;
    PORT
      LAYER M4 ;
        RECT  0 18.48 0.084 18.504 ;
    END
  END bank_read_addr_w[0]
  PIN bank_read_addr_w[10]
    DIRECTION OUTPUT ;
    USE SIGNAL ;
    PORT
      LAYER M4 ;
        RECT  0 19.44 0.084 19.464 ;
    END
  END bank_read_addr_w[10]
  PIN bank_read_addr_w[11]
    DIRECTION OUTPUT ;
    USE SIGNAL ;
    PORT
      LAYER M4 ;
        RECT  0 19.536 0.084 19.56 ;
    END
  END bank_read_addr_w[11]
  PIN bank_read_addr_w[12]
    DIRECTION OUTPUT ;
    USE SIGNAL ;
    PORT
      LAYER M4 ;
        RECT  0 19.632 0.084 19.656 ;
    END
  END bank_read_addr_w[12]
  PIN bank_read_addr_w[13]
    DIRECTION OUTPUT ;
    USE SIGNAL ;
    PORT
      LAYER M4 ;
        RECT  0 19.728 0.084 19.752 ;
    END
  END bank_read_addr_w[13]
  PIN bank_read_addr_w[14]
    DIRECTION OUTPUT ;
    USE SIGNAL ;
    PORT
      LAYER M4 ;
        RECT  0 19.824 0.084 19.848 ;
    END
  END bank_read_addr_w[14]
  PIN bank_read_addr_w[15]
    DIRECTION OUTPUT ;
    USE SIGNAL ;
    PORT
      LAYER M4 ;
        RECT  0 19.92 0.084 19.944 ;
    END
  END bank_read_addr_w[15]
  PIN bank_read_addr_w[16]
    DIRECTION OUTPUT ;
    USE SIGNAL ;
    PORT
      LAYER M4 ;
        RECT  0 20.016 0.084 20.04 ;
    END
  END bank_read_addr_w[16]
  PIN bank_read_addr_w[17]
    DIRECTION OUTPUT ;
    USE SIGNAL ;
    PORT
      LAYER M4 ;
        RECT  0 20.112 0.084 20.136 ;
    END
  END bank_read_addr_w[17]
  PIN bank_read_addr_w[18]
    DIRECTION OUTPUT ;
    USE SIGNAL ;
    PORT
      LAYER M4 ;
        RECT  0 20.208 0.084 20.232 ;
    END
  END bank_read_addr_w[18]
  PIN bank_read_addr_w[19]
    DIRECTION OUTPUT ;
    USE SIGNAL ;
    PORT
      LAYER M4 ;
        RECT  0 20.304 0.084 20.328 ;
    END
  END bank_read_addr_w[19]
  PIN bank_read_addr_w[1]
    DIRECTION OUTPUT ;
    USE SIGNAL ;
    PORT
      LAYER M4 ;
        RECT  0 18.576 0.084 18.6 ;
    END
  END bank_read_addr_w[1]
  PIN bank_read_addr_w[20]
    DIRECTION OUTPUT ;
    USE SIGNAL ;
    PORT
      LAYER M4 ;
        RECT  0 20.4 0.084 20.424 ;
    END
  END bank_read_addr_w[20]
  PIN bank_read_addr_w[21]
    DIRECTION OUTPUT ;
    USE SIGNAL ;
    PORT
      LAYER M4 ;
        RECT  0 20.496 0.084 20.52 ;
    END
  END bank_read_addr_w[21]
  PIN bank_read_addr_w[22]
    DIRECTION OUTPUT ;
    USE SIGNAL ;
    PORT
      LAYER M4 ;
        RECT  0 20.592 0.084 20.616 ;
    END
  END bank_read_addr_w[22]
  PIN bank_read_addr_w[23]
    DIRECTION OUTPUT ;
    USE SIGNAL ;
    PORT
      LAYER M4 ;
        RECT  0 20.688 0.084 20.712 ;
    END
  END bank_read_addr_w[23]
  PIN bank_read_addr_w[24]
    DIRECTION OUTPUT ;
    USE SIGNAL ;
    PORT
      LAYER M4 ;
        RECT  0 11.568 0.084 11.592 ;
    END
  END bank_read_addr_w[24]
  PIN bank_read_addr_w[25]
    DIRECTION OUTPUT ;
    USE SIGNAL ;
    PORT
      LAYER M4 ;
        RECT  0 11.664 0.084 11.688 ;
    END
  END bank_read_addr_w[25]
  PIN bank_read_addr_w[26]
    DIRECTION OUTPUT ;
    USE SIGNAL ;
    PORT
      LAYER M4 ;
        RECT  0 11.76 0.084 11.784 ;
    END
  END bank_read_addr_w[26]
  PIN bank_read_addr_w[27]
    DIRECTION OUTPUT ;
    USE SIGNAL ;
    PORT
      LAYER M4 ;
        RECT  0 11.856 0.084 11.88 ;
    END
  END bank_read_addr_w[27]
  PIN bank_read_addr_w[28]
    DIRECTION OUTPUT ;
    USE SIGNAL ;
    PORT
      LAYER M4 ;
        RECT  0 11.952 0.084 11.976 ;
    END
  END bank_read_addr_w[28]
  PIN bank_read_addr_w[29]
    DIRECTION OUTPUT ;
    USE SIGNAL ;
    PORT
      LAYER M4 ;
        RECT  0 12.048 0.084 12.072 ;
    END
  END bank_read_addr_w[29]
  PIN bank_read_addr_w[2]
    DIRECTION OUTPUT ;
    USE SIGNAL ;
    PORT
      LAYER M4 ;
        RECT  0 18.672 0.084 18.696 ;
    END
  END bank_read_addr_w[2]
  PIN bank_read_addr_w[30]
    DIRECTION OUTPUT ;
    USE SIGNAL ;
    PORT
      LAYER M4 ;
        RECT  0 12.144 0.084 12.168 ;
    END
  END bank_read_addr_w[30]
  PIN bank_read_addr_w[31]
    DIRECTION OUTPUT ;
    USE SIGNAL ;
    PORT
      LAYER M4 ;
        RECT  0 12.24 0.084 12.264 ;
    END
  END bank_read_addr_w[31]
  PIN bank_read_addr_w[32]
    DIRECTION OUTPUT ;
    USE SIGNAL ;
    PORT
      LAYER M4 ;
        RECT  0 12.336 0.084 12.36 ;
    END
  END bank_read_addr_w[32]
  PIN bank_read_addr_w[33]
    DIRECTION OUTPUT ;
    USE SIGNAL ;
    PORT
      LAYER M4 ;
        RECT  0 12.432 0.084 12.456 ;
    END
  END bank_read_addr_w[33]
  PIN bank_read_addr_w[34]
    DIRECTION OUTPUT ;
    USE SIGNAL ;
    PORT
      LAYER M4 ;
        RECT  0 12.528 0.084 12.552 ;
    END
  END bank_read_addr_w[34]
  PIN bank_read_addr_w[35]
    DIRECTION OUTPUT ;
    USE SIGNAL ;
    PORT
      LAYER M4 ;
        RECT  0 12.624 0.084 12.648 ;
    END
  END bank_read_addr_w[35]
  PIN bank_read_addr_w[36]
    DIRECTION OUTPUT ;
    USE SIGNAL ;
    PORT
      LAYER M4 ;
        RECT  0 12.72 0.084 12.744 ;
    END
  END bank_read_addr_w[36]
  PIN bank_read_addr_w[37]
    DIRECTION OUTPUT ;
    USE SIGNAL ;
    PORT
      LAYER M4 ;
        RECT  0 12.816 0.084 12.84 ;
    END
  END bank_read_addr_w[37]
  PIN bank_read_addr_w[38]
    DIRECTION OUTPUT ;
    USE SIGNAL ;
    PORT
      LAYER M4 ;
        RECT  0 12.912 0.084 12.936 ;
    END
  END bank_read_addr_w[38]
  PIN bank_read_addr_w[39]
    DIRECTION OUTPUT ;
    USE SIGNAL ;
    PORT
      LAYER M4 ;
        RECT  0 13.008 0.084 13.032 ;
    END
  END bank_read_addr_w[39]
  PIN bank_read_addr_w[3]
    DIRECTION OUTPUT ;
    USE SIGNAL ;
    PORT
      LAYER M4 ;
        RECT  0 18.768 0.084 18.792 ;
    END
  END bank_read_addr_w[3]
  PIN bank_read_addr_w[40]
    DIRECTION OUTPUT ;
    USE SIGNAL ;
    PORT
      LAYER M4 ;
        RECT  0 13.104 0.084 13.128 ;
    END
  END bank_read_addr_w[40]
  PIN bank_read_addr_w[41]
    DIRECTION OUTPUT ;
    USE SIGNAL ;
    PORT
      LAYER M4 ;
        RECT  0 13.2 0.084 13.224 ;
    END
  END bank_read_addr_w[41]
  PIN bank_read_addr_w[42]
    DIRECTION OUTPUT ;
    USE SIGNAL ;
    PORT
      LAYER M4 ;
        RECT  0 13.296 0.084 13.32 ;
    END
  END bank_read_addr_w[42]
  PIN bank_read_addr_w[43]
    DIRECTION OUTPUT ;
    USE SIGNAL ;
    PORT
      LAYER M4 ;
        RECT  0 13.392 0.084 13.416 ;
    END
  END bank_read_addr_w[43]
  PIN bank_read_addr_w[44]
    DIRECTION OUTPUT ;
    USE SIGNAL ;
    PORT
      LAYER M4 ;
        RECT  0 13.488 0.084 13.512 ;
    END
  END bank_read_addr_w[44]
  PIN bank_read_addr_w[45]
    DIRECTION OUTPUT ;
    USE SIGNAL ;
    PORT
      LAYER M4 ;
        RECT  0 13.584 0.084 13.608 ;
    END
  END bank_read_addr_w[45]
  PIN bank_read_addr_w[46]
    DIRECTION OUTPUT ;
    USE SIGNAL ;
    PORT
      LAYER M4 ;
        RECT  0 13.68 0.084 13.704 ;
    END
  END bank_read_addr_w[46]
  PIN bank_read_addr_w[47]
    DIRECTION OUTPUT ;
    USE SIGNAL ;
    PORT
      LAYER M4 ;
        RECT  0 13.776 0.084 13.8 ;
    END
  END bank_read_addr_w[47]
  PIN bank_read_addr_w[48]
    DIRECTION OUTPUT ;
    USE SIGNAL ;
    PORT
      LAYER M4 ;
        RECT  0 13.872 0.084 13.896 ;
    END
  END bank_read_addr_w[48]
  PIN bank_read_addr_w[49]
    DIRECTION OUTPUT ;
    USE SIGNAL ;
    PORT
      LAYER M4 ;
        RECT  0 13.968 0.084 13.992 ;
    END
  END bank_read_addr_w[49]
  PIN bank_read_addr_w[4]
    DIRECTION OUTPUT ;
    USE SIGNAL ;
    PORT
      LAYER M4 ;
        RECT  0 18.864 0.084 18.888 ;
    END
  END bank_read_addr_w[4]
  PIN bank_read_addr_w[50]
    DIRECTION OUTPUT ;
    USE SIGNAL ;
    PORT
      LAYER M4 ;
        RECT  0 14.064 0.084 14.088 ;
    END
  END bank_read_addr_w[50]
  PIN bank_read_addr_w[51]
    DIRECTION OUTPUT ;
    USE SIGNAL ;
    PORT
      LAYER M4 ;
        RECT  0 14.16 0.084 14.184 ;
    END
  END bank_read_addr_w[51]
  PIN bank_read_addr_w[52]
    DIRECTION OUTPUT ;
    USE SIGNAL ;
    PORT
      LAYER M4 ;
        RECT  0 14.256 0.084 14.28 ;
    END
  END bank_read_addr_w[52]
  PIN bank_read_addr_w[53]
    DIRECTION OUTPUT ;
    USE SIGNAL ;
    PORT
      LAYER M4 ;
        RECT  0 14.352 0.084 14.376 ;
    END
  END bank_read_addr_w[53]
  PIN bank_read_addr_w[54]
    DIRECTION OUTPUT ;
    USE SIGNAL ;
    PORT
      LAYER M4 ;
        RECT  0 14.448 0.084 14.472 ;
    END
  END bank_read_addr_w[54]
  PIN bank_read_addr_w[55]
    DIRECTION OUTPUT ;
    USE SIGNAL ;
    PORT
      LAYER M4 ;
        RECT  0 14.544 0.084 14.568 ;
    END
  END bank_read_addr_w[55]
  PIN bank_read_addr_w[56]
    DIRECTION OUTPUT ;
    USE SIGNAL ;
    PORT
      LAYER M4 ;
        RECT  0 30.768 0.084 30.792 ;
    END
  END bank_read_addr_w[56]
  PIN bank_read_addr_w[57]
    DIRECTION OUTPUT ;
    USE SIGNAL ;
    PORT
      LAYER M4 ;
        RECT  0 30.864 0.084 30.888 ;
    END
  END bank_read_addr_w[57]
  PIN bank_read_addr_w[58]
    DIRECTION OUTPUT ;
    USE SIGNAL ;
    PORT
      LAYER M4 ;
        RECT  0 30.96 0.084 30.984 ;
    END
  END bank_read_addr_w[58]
  PIN bank_read_addr_w[59]
    DIRECTION OUTPUT ;
    USE SIGNAL ;
    PORT
      LAYER M4 ;
        RECT  0 31.056 0.084 31.08 ;
    END
  END bank_read_addr_w[59]
  PIN bank_read_addr_w[5]
    DIRECTION OUTPUT ;
    USE SIGNAL ;
    PORT
      LAYER M4 ;
        RECT  0 18.96 0.084 18.984 ;
    END
  END bank_read_addr_w[5]
  PIN bank_read_addr_w[60]
    DIRECTION OUTPUT ;
    USE SIGNAL ;
    PORT
      LAYER M4 ;
        RECT  0 31.152 0.084 31.176 ;
    END
  END bank_read_addr_w[60]
  PIN bank_read_addr_w[61]
    DIRECTION OUTPUT ;
    USE SIGNAL ;
    PORT
      LAYER M4 ;
        RECT  0 31.248 0.084 31.272 ;
    END
  END bank_read_addr_w[61]
  PIN bank_read_addr_w[62]
    DIRECTION OUTPUT ;
    USE SIGNAL ;
    PORT
      LAYER M4 ;
        RECT  0 31.344 0.084 31.368 ;
    END
  END bank_read_addr_w[62]
  PIN bank_read_addr_w[63]
    DIRECTION OUTPUT ;
    USE SIGNAL ;
    PORT
      LAYER M4 ;
        RECT  0 31.44 0.084 31.464 ;
    END
  END bank_read_addr_w[63]
  PIN bank_read_addr_w[6]
    DIRECTION OUTPUT ;
    USE SIGNAL ;
    PORT
      LAYER M4 ;
        RECT  0 19.056 0.084 19.08 ;
    END
  END bank_read_addr_w[6]
  PIN bank_read_addr_w[7]
    DIRECTION OUTPUT ;
    USE SIGNAL ;
    PORT
      LAYER M4 ;
        RECT  0 19.152 0.084 19.176 ;
    END
  END bank_read_addr_w[7]
  PIN bank_read_addr_w[8]
    DIRECTION OUTPUT ;
    USE SIGNAL ;
    PORT
      LAYER M4 ;
        RECT  0 19.248 0.084 19.272 ;
    END
  END bank_read_addr_w[8]
  PIN bank_read_addr_w[9]
    DIRECTION OUTPUT ;
    USE SIGNAL ;
    PORT
      LAYER M4 ;
        RECT  0 19.344 0.084 19.368 ;
    END
  END bank_read_addr_w[9]
  PIN bank_read_en[0]
    DIRECTION OUTPUT ;
    USE SIGNAL ;
    PORT
      LAYER M4 ;
        RECT  0 31.536 0.084 31.56 ;
    END
  END bank_read_en[0]
  PIN bank_read_en[1]
    DIRECTION OUTPUT ;
    USE SIGNAL ;
    PORT
      LAYER M4 ;
        RECT  0 31.632 0.084 31.656 ;
    END
  END bank_read_en[1]
  PIN bank_read_en[2]
    DIRECTION OUTPUT ;
    USE SIGNAL ;
    PORT
      LAYER M4 ;
        RECT  0 31.728 0.084 31.752 ;
    END
  END bank_read_en[2]
  PIN bank_read_en[3]
    DIRECTION OUTPUT ;
    USE SIGNAL ;
    PORT
      LAYER M4 ;
        RECT  0 31.824 0.084 31.848 ;
    END
  END bank_read_en[3]
  PIN bank_read_en[4]
    DIRECTION OUTPUT ;
    USE SIGNAL ;
    PORT
      LAYER M4 ;
        RECT  0 31.92 0.084 31.944 ;
    END
  END bank_read_en[4]
  PIN bank_read_en[5]
    DIRECTION OUTPUT ;
    USE SIGNAL ;
    PORT
      LAYER M4 ;
        RECT  0 32.016 0.084 32.04 ;
    END
  END bank_read_en[5]
  PIN bank_read_en[6]
    DIRECTION OUTPUT ;
    USE SIGNAL ;
    PORT
      LAYER M4 ;
        RECT  0 32.112 0.084 32.136 ;
    END
  END bank_read_en[6]
  PIN bank_read_en[7]
    DIRECTION OUTPUT ;
    USE SIGNAL ;
    PORT
      LAYER M4 ;
        RECT  0 32.208 0.084 32.232 ;
    END
  END bank_read_en[7]
  PIN bank_read_slot_n[0]
    DIRECTION OUTPUT ;
    USE SIGNAL ;
    PORT
      LAYER M5 ;
        RECT  53.04 69.036 53.064 69.12 ;
    END
  END bank_read_slot_n[0]
  PIN bank_read_slot_n[1]
    DIRECTION OUTPUT ;
    USE SIGNAL ;
    PORT
      LAYER M5 ;
        RECT  53.136 69.036 53.16 69.12 ;
    END
  END bank_read_slot_n[1]
  PIN bank_read_slot_n[2]
    DIRECTION OUTPUT ;
    USE SIGNAL ;
    PORT
      LAYER M5 ;
        RECT  53.232 69.036 53.256 69.12 ;
    END
  END bank_read_slot_n[2]
  PIN bank_read_slot_n[3]
    DIRECTION OUTPUT ;
    USE SIGNAL ;
    PORT
      LAYER M5 ;
        RECT  53.328 69.036 53.352 69.12 ;
    END
  END bank_read_slot_n[3]
  PIN bank_read_slot_n[4]
    DIRECTION OUTPUT ;
    USE SIGNAL ;
    PORT
      LAYER M5 ;
        RECT  53.424 69.036 53.448 69.12 ;
    END
  END bank_read_slot_n[4]
  PIN bank_read_slot_n[5]
    DIRECTION OUTPUT ;
    USE SIGNAL ;
    PORT
      LAYER M5 ;
        RECT  53.52 69.036 53.544 69.12 ;
    END
  END bank_read_slot_n[5]
  PIN bank_read_slot_n[6]
    DIRECTION OUTPUT ;
    USE SIGNAL ;
    PORT
      LAYER M5 ;
        RECT  53.616 69.036 53.64 69.12 ;
    END
  END bank_read_slot_n[6]
  PIN bank_read_slot_s[0]
    DIRECTION OUTPUT ;
    USE SIGNAL ;
    PORT
      LAYER M5 ;
        RECT  48.528 0 48.552 0.084 ;
    END
  END bank_read_slot_s[0]
  PIN bank_read_slot_s[1]
    DIRECTION OUTPUT ;
    USE SIGNAL ;
    PORT
      LAYER M5 ;
        RECT  48.624 0 48.648 0.084 ;
    END
  END bank_read_slot_s[1]
  PIN bank_read_slot_s[2]
    DIRECTION OUTPUT ;
    USE SIGNAL ;
    PORT
      LAYER M5 ;
        RECT  48.72 0 48.744 0.084 ;
    END
  END bank_read_slot_s[2]
  PIN bank_read_slot_s[3]
    DIRECTION OUTPUT ;
    USE SIGNAL ;
    PORT
      LAYER M5 ;
        RECT  48.816 0 48.84 0.084 ;
    END
  END bank_read_slot_s[3]
  PIN bank_read_slot_s[4]
    DIRECTION OUTPUT ;
    USE SIGNAL ;
    PORT
      LAYER M5 ;
        RECT  48.912 0 48.936 0.084 ;
    END
  END bank_read_slot_s[4]
  PIN bank_read_slot_s[5]
    DIRECTION OUTPUT ;
    USE SIGNAL ;
    PORT
      LAYER M5 ;
        RECT  49.008 0 49.032 0.084 ;
    END
  END bank_read_slot_s[5]
  PIN bank_read_slot_s[6]
    DIRECTION OUTPUT ;
    USE SIGNAL ;
    PORT
      LAYER M5 ;
        RECT  49.104 0 49.128 0.084 ;
    END
  END bank_read_slot_s[6]
  PIN bank_read_slot_w[0]
    DIRECTION OUTPUT ;
    USE SIGNAL ;
    PORT
      LAYER M4 ;
        RECT  0 32.304 0.084 32.328 ;
    END
  END bank_read_slot_w[0]
  PIN bank_read_slot_w[1]
    DIRECTION OUTPUT ;
    USE SIGNAL ;
    PORT
      LAYER M4 ;
        RECT  0 32.4 0.084 32.424 ;
    END
  END bank_read_slot_w[1]
  PIN bank_read_slot_w[2]
    DIRECTION OUTPUT ;
    USE SIGNAL ;
    PORT
      LAYER M4 ;
        RECT  0 32.496 0.084 32.52 ;
    END
  END bank_read_slot_w[2]
  PIN bank_read_slot_w[3]
    DIRECTION OUTPUT ;
    USE SIGNAL ;
    PORT
      LAYER M4 ;
        RECT  0 32.592 0.084 32.616 ;
    END
  END bank_read_slot_w[3]
  PIN bank_read_slot_w[4]
    DIRECTION OUTPUT ;
    USE SIGNAL ;
    PORT
      LAYER M4 ;
        RECT  0 32.688 0.084 32.712 ;
    END
  END bank_read_slot_w[4]
  PIN bank_read_slot_w[5]
    DIRECTION OUTPUT ;
    USE SIGNAL ;
    PORT
      LAYER M4 ;
        RECT  0 32.784 0.084 32.808 ;
    END
  END bank_read_slot_w[5]
  PIN bank_read_slot_w[6]
    DIRECTION OUTPUT ;
    USE SIGNAL ;
    PORT
      LAYER M4 ;
        RECT  0 32.88 0.084 32.904 ;
    END
  END bank_read_slot_w[6]
  PIN bank_write_slot_n[0]
    DIRECTION OUTPUT ;
    USE SIGNAL ;
    PORT
      LAYER M5 ;
        RECT  53.712 69.036 53.736 69.12 ;
    END
  END bank_write_slot_n[0]
  PIN bank_write_slot_n[1]
    DIRECTION OUTPUT ;
    USE SIGNAL ;
    PORT
      LAYER M5 ;
        RECT  53.808 69.036 53.832 69.12 ;
    END
  END bank_write_slot_n[1]
  PIN bank_write_slot_n[2]
    DIRECTION OUTPUT ;
    USE SIGNAL ;
    PORT
      LAYER M5 ;
        RECT  53.904 69.036 53.928 69.12 ;
    END
  END bank_write_slot_n[2]
  PIN bank_write_slot_n[3]
    DIRECTION OUTPUT ;
    USE SIGNAL ;
    PORT
      LAYER M5 ;
        RECT  54 69.036 54.024 69.12 ;
    END
  END bank_write_slot_n[3]
  PIN bank_write_slot_n[4]
    DIRECTION OUTPUT ;
    USE SIGNAL ;
    PORT
      LAYER M5 ;
        RECT  54.096 69.036 54.12 69.12 ;
    END
  END bank_write_slot_n[4]
  PIN bank_write_slot_n[5]
    DIRECTION OUTPUT ;
    USE SIGNAL ;
    PORT
      LAYER M5 ;
        RECT  54.192 69.036 54.216 69.12 ;
    END
  END bank_write_slot_n[5]
  PIN bank_write_slot_n[6]
    DIRECTION OUTPUT ;
    USE SIGNAL ;
    PORT
      LAYER M5 ;
        RECT  54.288 69.036 54.312 69.12 ;
    END
  END bank_write_slot_n[6]
  PIN bank_write_slot_s[0]
    DIRECTION OUTPUT ;
    USE SIGNAL ;
    PORT
      LAYER M5 ;
        RECT  49.2 0 49.224 0.084 ;
    END
  END bank_write_slot_s[0]
  PIN bank_write_slot_s[1]
    DIRECTION OUTPUT ;
    USE SIGNAL ;
    PORT
      LAYER M5 ;
        RECT  49.296 0 49.32 0.084 ;
    END
  END bank_write_slot_s[1]
  PIN bank_write_slot_s[2]
    DIRECTION OUTPUT ;
    USE SIGNAL ;
    PORT
      LAYER M5 ;
        RECT  49.392 0 49.416 0.084 ;
    END
  END bank_write_slot_s[2]
  PIN bank_write_slot_s[3]
    DIRECTION OUTPUT ;
    USE SIGNAL ;
    PORT
      LAYER M5 ;
        RECT  49.488 0 49.512 0.084 ;
    END
  END bank_write_slot_s[3]
  PIN bank_write_slot_s[4]
    DIRECTION OUTPUT ;
    USE SIGNAL ;
    PORT
      LAYER M5 ;
        RECT  49.584 0 49.608 0.084 ;
    END
  END bank_write_slot_s[4]
  PIN bank_write_slot_s[5]
    DIRECTION OUTPUT ;
    USE SIGNAL ;
    PORT
      LAYER M5 ;
        RECT  49.68 0 49.704 0.084 ;
    END
  END bank_write_slot_s[5]
  PIN bank_write_slot_s[6]
    DIRECTION OUTPUT ;
    USE SIGNAL ;
    PORT
      LAYER M5 ;
        RECT  49.776 0 49.8 0.084 ;
    END
  END bank_write_slot_s[6]
  PIN bank_write_slot_w[0]
    DIRECTION OUTPUT ;
    USE SIGNAL ;
    PORT
      LAYER M4 ;
        RECT  0 32.976 0.084 33 ;
    END
  END bank_write_slot_w[0]
  PIN bank_write_slot_w[1]
    DIRECTION OUTPUT ;
    USE SIGNAL ;
    PORT
      LAYER M4 ;
        RECT  0 33.072 0.084 33.096 ;
    END
  END bank_write_slot_w[1]
  PIN bank_write_slot_w[2]
    DIRECTION OUTPUT ;
    USE SIGNAL ;
    PORT
      LAYER M4 ;
        RECT  0 33.168 0.084 33.192 ;
    END
  END bank_write_slot_w[2]
  PIN bank_write_slot_w[3]
    DIRECTION OUTPUT ;
    USE SIGNAL ;
    PORT
      LAYER M4 ;
        RECT  0 33.264 0.084 33.288 ;
    END
  END bank_write_slot_w[3]
  PIN bank_write_slot_w[4]
    DIRECTION OUTPUT ;
    USE SIGNAL ;
    PORT
      LAYER M4 ;
        RECT  0 33.36 0.084 33.384 ;
    END
  END bank_write_slot_w[4]
  PIN bank_write_slot_w[5]
    DIRECTION OUTPUT ;
    USE SIGNAL ;
    PORT
      LAYER M4 ;
        RECT  0 33.456 0.084 33.48 ;
    END
  END bank_write_slot_w[5]
  PIN bank_write_slot_w[6]
    DIRECTION OUTPUT ;
    USE SIGNAL ;
    PORT
      LAYER M4 ;
        RECT  0 33.552 0.084 33.576 ;
    END
  END bank_write_slot_w[6]
  PIN busy
    DIRECTION OUTPUT ;
    USE SIGNAL ;
    PORT
      LAYER M4 ;
        RECT  69.036 54.48 69.12 54.504 ;
    END
  END busy
  PIN clk
    DIRECTION INPUT ;
    USE SIGNAL ;
    PORT
      LAYER M4 ;
        RECT  69.036 54.576 69.12 54.6 ;
    END
  END clk
  PIN cycle_in[0]
    DIRECTION INPUT ;
    USE SIGNAL ;
    PORT
      LAYER M4 ;
        RECT  69.036 54.672 69.12 54.696 ;
    END
  END cycle_in[0]
  PIN cycle_in[10]
    DIRECTION INPUT ;
    USE SIGNAL ;
    PORT
      LAYER M4 ;
        RECT  69.036 55.632 69.12 55.656 ;
    END
  END cycle_in[10]
  PIN cycle_in[11]
    DIRECTION INPUT ;
    USE SIGNAL ;
    PORT
      LAYER M4 ;
        RECT  69.036 55.728 69.12 55.752 ;
    END
  END cycle_in[11]
  PIN cycle_in[12]
    DIRECTION INPUT ;
    USE SIGNAL ;
    PORT
      LAYER M4 ;
        RECT  69.036 55.824 69.12 55.848 ;
    END
  END cycle_in[12]
  PIN cycle_in[13]
    DIRECTION INPUT ;
    USE SIGNAL ;
    PORT
      LAYER M4 ;
        RECT  69.036 55.92 69.12 55.944 ;
    END
  END cycle_in[13]
  PIN cycle_in[14]
    DIRECTION INPUT ;
    USE SIGNAL ;
    PORT
      LAYER M4 ;
        RECT  69.036 56.016 69.12 56.04 ;
    END
  END cycle_in[14]
  PIN cycle_in[15]
    DIRECTION INPUT ;
    USE SIGNAL ;
    PORT
      LAYER M4 ;
        RECT  69.036 56.112 69.12 56.136 ;
    END
  END cycle_in[15]
  PIN cycle_in[16]
    DIRECTION INPUT ;
    USE SIGNAL ;
    PORT
      LAYER M4 ;
        RECT  69.036 56.208 69.12 56.232 ;
    END
  END cycle_in[16]
  PIN cycle_in[17]
    DIRECTION INPUT ;
    USE SIGNAL ;
    PORT
      LAYER M4 ;
        RECT  69.036 56.304 69.12 56.328 ;
    END
  END cycle_in[17]
  PIN cycle_in[18]
    DIRECTION INPUT ;
    USE SIGNAL ;
    PORT
      LAYER M4 ;
        RECT  69.036 56.4 69.12 56.424 ;
    END
  END cycle_in[18]
  PIN cycle_in[19]
    DIRECTION INPUT ;
    USE SIGNAL ;
    PORT
      LAYER M4 ;
        RECT  69.036 56.496 69.12 56.52 ;
    END
  END cycle_in[19]
  PIN cycle_in[1]
    DIRECTION INPUT ;
    USE SIGNAL ;
    PORT
      LAYER M4 ;
        RECT  69.036 54.768 69.12 54.792 ;
    END
  END cycle_in[1]
  PIN cycle_in[20]
    DIRECTION INPUT ;
    USE SIGNAL ;
    PORT
      LAYER M4 ;
        RECT  69.036 56.592 69.12 56.616 ;
    END
  END cycle_in[20]
  PIN cycle_in[21]
    DIRECTION INPUT ;
    USE SIGNAL ;
    PORT
      LAYER M4 ;
        RECT  69.036 56.688 69.12 56.712 ;
    END
  END cycle_in[21]
  PIN cycle_in[22]
    DIRECTION INPUT ;
    USE SIGNAL ;
    PORT
      LAYER M4 ;
        RECT  69.036 56.784 69.12 56.808 ;
    END
  END cycle_in[22]
  PIN cycle_in[23]
    DIRECTION INPUT ;
    USE SIGNAL ;
    PORT
      LAYER M4 ;
        RECT  69.036 56.88 69.12 56.904 ;
    END
  END cycle_in[23]
  PIN cycle_in[24]
    DIRECTION INPUT ;
    USE SIGNAL ;
    PORT
      LAYER M4 ;
        RECT  69.036 56.976 69.12 57 ;
    END
  END cycle_in[24]
  PIN cycle_in[25]
    DIRECTION INPUT ;
    USE SIGNAL ;
    PORT
      LAYER M4 ;
        RECT  69.036 57.072 69.12 57.096 ;
    END
  END cycle_in[25]
  PIN cycle_in[26]
    DIRECTION INPUT ;
    USE SIGNAL ;
    PORT
      LAYER M4 ;
        RECT  69.036 57.168 69.12 57.192 ;
    END
  END cycle_in[26]
  PIN cycle_in[27]
    DIRECTION INPUT ;
    USE SIGNAL ;
    PORT
      LAYER M4 ;
        RECT  69.036 57.264 69.12 57.288 ;
    END
  END cycle_in[27]
  PIN cycle_in[28]
    DIRECTION INPUT ;
    USE SIGNAL ;
    PORT
      LAYER M4 ;
        RECT  69.036 57.36 69.12 57.384 ;
    END
  END cycle_in[28]
  PIN cycle_in[29]
    DIRECTION INPUT ;
    USE SIGNAL ;
    PORT
      LAYER M4 ;
        RECT  69.036 57.456 69.12 57.48 ;
    END
  END cycle_in[29]
  PIN cycle_in[2]
    DIRECTION INPUT ;
    USE SIGNAL ;
    PORT
      LAYER M4 ;
        RECT  69.036 54.864 69.12 54.888 ;
    END
  END cycle_in[2]
  PIN cycle_in[30]
    DIRECTION INPUT ;
    USE SIGNAL ;
    PORT
      LAYER M4 ;
        RECT  69.036 58.32 69.12 58.344 ;
    END
  END cycle_in[30]
  PIN cycle_in[31]
    DIRECTION INPUT ;
    USE SIGNAL ;
    PORT
      LAYER M4 ;
        RECT  69.036 58.416 69.12 58.44 ;
    END
  END cycle_in[31]
  PIN cycle_in[3]
    DIRECTION INPUT ;
    USE SIGNAL ;
    PORT
      LAYER M4 ;
        RECT  69.036 54.96 69.12 54.984 ;
    END
  END cycle_in[3]
  PIN cycle_in[4]
    DIRECTION INPUT ;
    USE SIGNAL ;
    PORT
      LAYER M4 ;
        RECT  69.036 55.056 69.12 55.08 ;
    END
  END cycle_in[4]
  PIN cycle_in[5]
    DIRECTION INPUT ;
    USE SIGNAL ;
    PORT
      LAYER M4 ;
        RECT  69.036 55.152 69.12 55.176 ;
    END
  END cycle_in[5]
  PIN cycle_in[6]
    DIRECTION INPUT ;
    USE SIGNAL ;
    PORT
      LAYER M4 ;
        RECT  69.036 55.248 69.12 55.272 ;
    END
  END cycle_in[6]
  PIN cycle_in[7]
    DIRECTION INPUT ;
    USE SIGNAL ;
    PORT
      LAYER M4 ;
        RECT  69.036 55.344 69.12 55.368 ;
    END
  END cycle_in[7]
  PIN cycle_in[8]
    DIRECTION INPUT ;
    USE SIGNAL ;
    PORT
      LAYER M4 ;
        RECT  69.036 55.44 69.12 55.464 ;
    END
  END cycle_in[8]
  PIN cycle_in[9]
    DIRECTION INPUT ;
    USE SIGNAL ;
    PORT
      LAYER M4 ;
        RECT  69.036 55.536 69.12 55.56 ;
    END
  END cycle_in[9]
  PIN drain_at[0]
    DIRECTION INPUT ;
    USE SIGNAL ;
    PORT
      LAYER M4 ;
        RECT  69.036 58.512 69.12 58.536 ;
    END
  END drain_at[0]
  PIN drain_at[10]
    DIRECTION INPUT ;
    USE SIGNAL ;
    PORT
      LAYER M4 ;
        RECT  69.036 59.472 69.12 59.496 ;
    END
  END drain_at[10]
  PIN drain_at[11]
    DIRECTION INPUT ;
    USE SIGNAL ;
    PORT
      LAYER M4 ;
        RECT  69.036 59.568 69.12 59.592 ;
    END
  END drain_at[11]
  PIN drain_at[12]
    DIRECTION INPUT ;
    USE SIGNAL ;
    PORT
      LAYER M4 ;
        RECT  69.036 59.664 69.12 59.688 ;
    END
  END drain_at[12]
  PIN drain_at[13]
    DIRECTION INPUT ;
    USE SIGNAL ;
    PORT
      LAYER M4 ;
        RECT  69.036 59.76 69.12 59.784 ;
    END
  END drain_at[13]
  PIN drain_at[14]
    DIRECTION INPUT ;
    USE SIGNAL ;
    PORT
      LAYER M4 ;
        RECT  69.036 59.856 69.12 59.88 ;
    END
  END drain_at[14]
  PIN drain_at[15]
    DIRECTION INPUT ;
    USE SIGNAL ;
    PORT
      LAYER M4 ;
        RECT  69.036 59.952 69.12 59.976 ;
    END
  END drain_at[15]
  PIN drain_at[16]
    DIRECTION INPUT ;
    USE SIGNAL ;
    PORT
      LAYER M4 ;
        RECT  69.036 60.048 69.12 60.072 ;
    END
  END drain_at[16]
  PIN drain_at[17]
    DIRECTION INPUT ;
    USE SIGNAL ;
    PORT
      LAYER M4 ;
        RECT  69.036 60.144 69.12 60.168 ;
    END
  END drain_at[17]
  PIN drain_at[18]
    DIRECTION INPUT ;
    USE SIGNAL ;
    PORT
      LAYER M4 ;
        RECT  69.036 60.24 69.12 60.264 ;
    END
  END drain_at[18]
  PIN drain_at[19]
    DIRECTION INPUT ;
    USE SIGNAL ;
    PORT
      LAYER M4 ;
        RECT  69.036 60.336 69.12 60.36 ;
    END
  END drain_at[19]
  PIN drain_at[1]
    DIRECTION INPUT ;
    USE SIGNAL ;
    PORT
      LAYER M4 ;
        RECT  69.036 58.608 69.12 58.632 ;
    END
  END drain_at[1]
  PIN drain_at[20]
    DIRECTION INPUT ;
    USE SIGNAL ;
    PORT
      LAYER M4 ;
        RECT  69.036 60.432 69.12 60.456 ;
    END
  END drain_at[20]
  PIN drain_at[21]
    DIRECTION INPUT ;
    USE SIGNAL ;
    PORT
      LAYER M4 ;
        RECT  69.036 60.528 69.12 60.552 ;
    END
  END drain_at[21]
  PIN drain_at[22]
    DIRECTION INPUT ;
    USE SIGNAL ;
    PORT
      LAYER M4 ;
        RECT  69.036 60.624 69.12 60.648 ;
    END
  END drain_at[22]
  PIN drain_at[23]
    DIRECTION INPUT ;
    USE SIGNAL ;
    PORT
      LAYER M4 ;
        RECT  69.036 60.72 69.12 60.744 ;
    END
  END drain_at[23]
  PIN drain_at[24]
    DIRECTION INPUT ;
    USE SIGNAL ;
    PORT
      LAYER M4 ;
        RECT  69.036 60.816 69.12 60.84 ;
    END
  END drain_at[24]
  PIN drain_at[25]
    DIRECTION INPUT ;
    USE SIGNAL ;
    PORT
      LAYER M4 ;
        RECT  69.036 60.912 69.12 60.936 ;
    END
  END drain_at[25]
  PIN drain_at[26]
    DIRECTION INPUT ;
    USE SIGNAL ;
    PORT
      LAYER M4 ;
        RECT  69.036 61.008 69.12 61.032 ;
    END
  END drain_at[26]
  PIN drain_at[27]
    DIRECTION INPUT ;
    USE SIGNAL ;
    PORT
      LAYER M4 ;
        RECT  69.036 61.104 69.12 61.128 ;
    END
  END drain_at[27]
  PIN drain_at[28]
    DIRECTION INPUT ;
    USE SIGNAL ;
    PORT
      LAYER M4 ;
        RECT  69.036 61.2 69.12 61.224 ;
    END
  END drain_at[28]
  PIN drain_at[29]
    DIRECTION INPUT ;
    USE SIGNAL ;
    PORT
      LAYER M4 ;
        RECT  69.036 61.296 69.12 61.32 ;
    END
  END drain_at[29]
  PIN drain_at[2]
    DIRECTION INPUT ;
    USE SIGNAL ;
    PORT
      LAYER M4 ;
        RECT  69.036 58.704 69.12 58.728 ;
    END
  END drain_at[2]
  PIN drain_at[30]
    DIRECTION INPUT ;
    USE SIGNAL ;
    PORT
      LAYER M4 ;
        RECT  69.036 64.464 69.12 64.488 ;
    END
  END drain_at[30]
  PIN drain_at[31]
    DIRECTION INPUT ;
    USE SIGNAL ;
    PORT
      LAYER M4 ;
        RECT  69.036 64.56 69.12 64.584 ;
    END
  END drain_at[31]
  PIN drain_at[3]
    DIRECTION INPUT ;
    USE SIGNAL ;
    PORT
      LAYER M4 ;
        RECT  69.036 58.8 69.12 58.824 ;
    END
  END drain_at[3]
  PIN drain_at[4]
    DIRECTION INPUT ;
    USE SIGNAL ;
    PORT
      LAYER M4 ;
        RECT  69.036 58.896 69.12 58.92 ;
    END
  END drain_at[4]
  PIN drain_at[5]
    DIRECTION INPUT ;
    USE SIGNAL ;
    PORT
      LAYER M4 ;
        RECT  69.036 58.992 69.12 59.016 ;
    END
  END drain_at[5]
  PIN drain_at[6]
    DIRECTION INPUT ;
    USE SIGNAL ;
    PORT
      LAYER M4 ;
        RECT  69.036 59.088 69.12 59.112 ;
    END
  END drain_at[6]
  PIN drain_at[7]
    DIRECTION INPUT ;
    USE SIGNAL ;
    PORT
      LAYER M4 ;
        RECT  69.036 59.184 69.12 59.208 ;
    END
  END drain_at[7]
  PIN drain_at[8]
    DIRECTION INPUT ;
    USE SIGNAL ;
    PORT
      LAYER M4 ;
        RECT  69.036 59.28 69.12 59.304 ;
    END
  END drain_at[8]
  PIN drain_at[9]
    DIRECTION INPUT ;
    USE SIGNAL ;
    PORT
      LAYER M4 ;
        RECT  69.036 59.376 69.12 59.4 ;
    END
  END drain_at[9]
  PIN issue_at[0]
    DIRECTION INPUT ;
    USE SIGNAL ;
    PORT
      LAYER M4 ;
        RECT  69.036 64.656 69.12 64.68 ;
    END
  END issue_at[0]
  PIN issue_at[10]
    DIRECTION INPUT ;
    USE SIGNAL ;
    PORT
      LAYER M4 ;
        RECT  69.036 65.616 69.12 65.64 ;
    END
  END issue_at[10]
  PIN issue_at[11]
    DIRECTION INPUT ;
    USE SIGNAL ;
    PORT
      LAYER M4 ;
        RECT  69.036 65.712 69.12 65.736 ;
    END
  END issue_at[11]
  PIN issue_at[12]
    DIRECTION INPUT ;
    USE SIGNAL ;
    PORT
      LAYER M4 ;
        RECT  69.036 65.808 69.12 65.832 ;
    END
  END issue_at[12]
  PIN issue_at[13]
    DIRECTION INPUT ;
    USE SIGNAL ;
    PORT
      LAYER M4 ;
        RECT  69.036 65.904 69.12 65.928 ;
    END
  END issue_at[13]
  PIN issue_at[14]
    DIRECTION INPUT ;
    USE SIGNAL ;
    PORT
      LAYER M4 ;
        RECT  69.036 66 69.12 66.024 ;
    END
  END issue_at[14]
  PIN issue_at[15]
    DIRECTION INPUT ;
    USE SIGNAL ;
    PORT
      LAYER M4 ;
        RECT  69.036 66.096 69.12 66.12 ;
    END
  END issue_at[15]
  PIN issue_at[16]
    DIRECTION INPUT ;
    USE SIGNAL ;
    PORT
      LAYER M4 ;
        RECT  69.036 66.192 69.12 66.216 ;
    END
  END issue_at[16]
  PIN issue_at[17]
    DIRECTION INPUT ;
    USE SIGNAL ;
    PORT
      LAYER M4 ;
        RECT  69.036 66.288 69.12 66.312 ;
    END
  END issue_at[17]
  PIN issue_at[18]
    DIRECTION INPUT ;
    USE SIGNAL ;
    PORT
      LAYER M4 ;
        RECT  69.036 66.384 69.12 66.408 ;
    END
  END issue_at[18]
  PIN issue_at[19]
    DIRECTION INPUT ;
    USE SIGNAL ;
    PORT
      LAYER M4 ;
        RECT  69.036 66.48 69.12 66.504 ;
    END
  END issue_at[19]
  PIN issue_at[1]
    DIRECTION INPUT ;
    USE SIGNAL ;
    PORT
      LAYER M4 ;
        RECT  69.036 64.752 69.12 64.776 ;
    END
  END issue_at[1]
  PIN issue_at[20]
    DIRECTION INPUT ;
    USE SIGNAL ;
    PORT
      LAYER M4 ;
        RECT  69.036 66.576 69.12 66.6 ;
    END
  END issue_at[20]
  PIN issue_at[21]
    DIRECTION INPUT ;
    USE SIGNAL ;
    PORT
      LAYER M4 ;
        RECT  69.036 66.672 69.12 66.696 ;
    END
  END issue_at[21]
  PIN issue_at[22]
    DIRECTION INPUT ;
    USE SIGNAL ;
    PORT
      LAYER M4 ;
        RECT  69.036 66.768 69.12 66.792 ;
    END
  END issue_at[22]
  PIN issue_at[23]
    DIRECTION INPUT ;
    USE SIGNAL ;
    PORT
      LAYER M4 ;
        RECT  69.036 66.864 69.12 66.888 ;
    END
  END issue_at[23]
  PIN issue_at[24]
    DIRECTION INPUT ;
    USE SIGNAL ;
    PORT
      LAYER M4 ;
        RECT  69.036 66.96 69.12 66.984 ;
    END
  END issue_at[24]
  PIN issue_at[25]
    DIRECTION INPUT ;
    USE SIGNAL ;
    PORT
      LAYER M4 ;
        RECT  69.036 67.056 69.12 67.08 ;
    END
  END issue_at[25]
  PIN issue_at[26]
    DIRECTION INPUT ;
    USE SIGNAL ;
    PORT
      LAYER M4 ;
        RECT  69.036 67.152 69.12 67.176 ;
    END
  END issue_at[26]
  PIN issue_at[27]
    DIRECTION INPUT ;
    USE SIGNAL ;
    PORT
      LAYER M4 ;
        RECT  69.036 67.248 69.12 67.272 ;
    END
  END issue_at[27]
  PIN issue_at[28]
    DIRECTION INPUT ;
    USE SIGNAL ;
    PORT
      LAYER M4 ;
        RECT  69.036 67.344 69.12 67.368 ;
    END
  END issue_at[28]
  PIN issue_at[29]
    DIRECTION INPUT ;
    USE SIGNAL ;
    PORT
      LAYER M4 ;
        RECT  69.036 67.44 69.12 67.464 ;
    END
  END issue_at[29]
  PIN issue_at[2]
    DIRECTION INPUT ;
    USE SIGNAL ;
    PORT
      LAYER M4 ;
        RECT  69.036 64.848 69.12 64.872 ;
    END
  END issue_at[2]
  PIN issue_at[30]
    DIRECTION INPUT ;
    USE SIGNAL ;
    PORT
      LAYER M4 ;
        RECT  69.036 29.136 69.12 29.16 ;
    END
  END issue_at[30]
  PIN issue_at[31]
    DIRECTION INPUT ;
    USE SIGNAL ;
    PORT
      LAYER M4 ;
        RECT  69.036 29.232 69.12 29.256 ;
    END
  END issue_at[31]
  PIN issue_at[3]
    DIRECTION INPUT ;
    USE SIGNAL ;
    PORT
      LAYER M4 ;
        RECT  69.036 64.944 69.12 64.968 ;
    END
  END issue_at[3]
  PIN issue_at[4]
    DIRECTION INPUT ;
    USE SIGNAL ;
    PORT
      LAYER M4 ;
        RECT  69.036 65.04 69.12 65.064 ;
    END
  END issue_at[4]
  PIN issue_at[5]
    DIRECTION INPUT ;
    USE SIGNAL ;
    PORT
      LAYER M4 ;
        RECT  69.036 65.136 69.12 65.16 ;
    END
  END issue_at[5]
  PIN issue_at[6]
    DIRECTION INPUT ;
    USE SIGNAL ;
    PORT
      LAYER M4 ;
        RECT  69.036 65.232 69.12 65.256 ;
    END
  END issue_at[6]
  PIN issue_at[7]
    DIRECTION INPUT ;
    USE SIGNAL ;
    PORT
      LAYER M4 ;
        RECT  69.036 65.328 69.12 65.352 ;
    END
  END issue_at[7]
  PIN issue_at[8]
    DIRECTION INPUT ;
    USE SIGNAL ;
    PORT
      LAYER M4 ;
        RECT  69.036 65.424 69.12 65.448 ;
    END
  END issue_at[8]
  PIN issue_at[9]
    DIRECTION INPUT ;
    USE SIGNAL ;
    PORT
      LAYER M4 ;
        RECT  69.036 65.52 69.12 65.544 ;
    END
  END issue_at[9]
  PIN mv[0]
    DIRECTION INPUT ;
    USE SIGNAL ;
    PORT
      LAYER M4 ;
        RECT  69.036 29.328 69.12 29.352 ;
    END
  END mv[0]
  PIN mv[100]
    DIRECTION INPUT ;
    USE SIGNAL ;
    PORT
      LAYER M4 ;
        RECT  69.036 7.44 69.12 7.464 ;
    END
  END mv[100]
  PIN mv[101]
    DIRECTION INPUT ;
    USE SIGNAL ;
    PORT
      LAYER M4 ;
        RECT  69.036 7.536 69.12 7.56 ;
    END
  END mv[101]
  PIN mv[102]
    DIRECTION INPUT ;
    USE SIGNAL ;
    PORT
      LAYER M4 ;
        RECT  69.036 7.632 69.12 7.656 ;
    END
  END mv[102]
  PIN mv[103]
    DIRECTION INPUT ;
    USE SIGNAL ;
    PORT
      LAYER M4 ;
        RECT  69.036 7.728 69.12 7.752 ;
    END
  END mv[103]
  PIN mv[104]
    DIRECTION INPUT ;
    USE SIGNAL ;
    PORT
      LAYER M4 ;
        RECT  69.036 7.824 69.12 7.848 ;
    END
  END mv[104]
  PIN mv[105]
    DIRECTION INPUT ;
    USE SIGNAL ;
    PORT
      LAYER M4 ;
        RECT  69.036 7.92 69.12 7.944 ;
    END
  END mv[105]
  PIN mv[106]
    DIRECTION INPUT ;
    USE SIGNAL ;
    PORT
      LAYER M4 ;
        RECT  69.036 8.016 69.12 8.04 ;
    END
  END mv[106]
  PIN mv[107]
    DIRECTION INPUT ;
    USE SIGNAL ;
    PORT
      LAYER M4 ;
        RECT  69.036 8.112 69.12 8.136 ;
    END
  END mv[107]
  PIN mv[108]
    DIRECTION INPUT ;
    USE SIGNAL ;
    PORT
      LAYER M4 ;
        RECT  69.036 8.208 69.12 8.232 ;
    END
  END mv[108]
  PIN mv[109]
    DIRECTION INPUT ;
    USE SIGNAL ;
    PORT
      LAYER M4 ;
        RECT  69.036 8.304 69.12 8.328 ;
    END
  END mv[109]
  PIN mv[10]
    DIRECTION INPUT ;
    USE SIGNAL ;
    PORT
      LAYER M4 ;
        RECT  69.036 30.288 69.12 30.312 ;
    END
  END mv[10]
  PIN mv[110]
    DIRECTION INPUT ;
    USE SIGNAL ;
    PORT
      LAYER M4 ;
        RECT  69.036 8.4 69.12 8.424 ;
    END
  END mv[110]
  PIN mv[111]
    DIRECTION INPUT ;
    USE SIGNAL ;
    PORT
      LAYER M4 ;
        RECT  69.036 8.496 69.12 8.52 ;
    END
  END mv[111]
  PIN mv[112]
    DIRECTION INPUT ;
    USE SIGNAL ;
    PORT
      LAYER M4 ;
        RECT  69.036 8.592 69.12 8.616 ;
    END
  END mv[112]
  PIN mv[113]
    DIRECTION INPUT ;
    USE SIGNAL ;
    PORT
      LAYER M4 ;
        RECT  69.036 8.688 69.12 8.712 ;
    END
  END mv[113]
  PIN mv[114]
    DIRECTION INPUT ;
    USE SIGNAL ;
    PORT
      LAYER M4 ;
        RECT  69.036 8.784 69.12 8.808 ;
    END
  END mv[114]
  PIN mv[115]
    DIRECTION INPUT ;
    USE SIGNAL ;
    PORT
      LAYER M4 ;
        RECT  69.036 8.88 69.12 8.904 ;
    END
  END mv[115]
  PIN mv[116]
    DIRECTION INPUT ;
    USE SIGNAL ;
    PORT
      LAYER M4 ;
        RECT  69.036 8.976 69.12 9 ;
    END
  END mv[116]
  PIN mv[117]
    DIRECTION INPUT ;
    USE SIGNAL ;
    PORT
      LAYER M4 ;
        RECT  69.036 9.072 69.12 9.096 ;
    END
  END mv[117]
  PIN mv[118]
    DIRECTION INPUT ;
    USE SIGNAL ;
    PORT
      LAYER M4 ;
        RECT  69.036 9.168 69.12 9.192 ;
    END
  END mv[118]
  PIN mv[119]
    DIRECTION INPUT ;
    USE SIGNAL ;
    PORT
      LAYER M4 ;
        RECT  69.036 9.264 69.12 9.288 ;
    END
  END mv[119]
  PIN mv[11]
    DIRECTION INPUT ;
    USE SIGNAL ;
    PORT
      LAYER M4 ;
        RECT  69.036 30.384 69.12 30.408 ;
    END
  END mv[11]
  PIN mv[120]
    DIRECTION INPUT ;
    USE SIGNAL ;
    PORT
      LAYER M4 ;
        RECT  69.036 9.36 69.12 9.384 ;
    END
  END mv[120]
  PIN mv[121]
    DIRECTION INPUT ;
    USE SIGNAL ;
    PORT
      LAYER M4 ;
        RECT  69.036 9.456 69.12 9.48 ;
    END
  END mv[121]
  PIN mv[122]
    DIRECTION INPUT ;
    USE SIGNAL ;
    PORT
      LAYER M4 ;
        RECT  69.036 9.552 69.12 9.576 ;
    END
  END mv[122]
  PIN mv[123]
    DIRECTION INPUT ;
    USE SIGNAL ;
    PORT
      LAYER M4 ;
        RECT  69.036 9.648 69.12 9.672 ;
    END
  END mv[123]
  PIN mv[124]
    DIRECTION INPUT ;
    USE SIGNAL ;
    PORT
      LAYER M4 ;
        RECT  69.036 9.744 69.12 9.768 ;
    END
  END mv[124]
  PIN mv[125]
    DIRECTION INPUT ;
    USE SIGNAL ;
    PORT
      LAYER M4 ;
        RECT  69.036 9.84 69.12 9.864 ;
    END
  END mv[125]
  PIN mv[126]
    DIRECTION INPUT ;
    USE SIGNAL ;
    PORT
      LAYER M4 ;
        RECT  69.036 13.008 69.12 13.032 ;
    END
  END mv[126]
  PIN mv[127]
    DIRECTION INPUT ;
    USE SIGNAL ;
    PORT
      LAYER M4 ;
        RECT  69.036 13.104 69.12 13.128 ;
    END
  END mv[127]
  PIN mv[128]
    DIRECTION INPUT ;
    USE SIGNAL ;
    PORT
      LAYER M4 ;
        RECT  69.036 13.2 69.12 13.224 ;
    END
  END mv[128]
  PIN mv[129]
    DIRECTION INPUT ;
    USE SIGNAL ;
    PORT
      LAYER M4 ;
        RECT  69.036 13.296 69.12 13.32 ;
    END
  END mv[129]
  PIN mv[12]
    DIRECTION INPUT ;
    USE SIGNAL ;
    PORT
      LAYER M4 ;
        RECT  69.036 30.48 69.12 30.504 ;
    END
  END mv[12]
  PIN mv[130]
    DIRECTION INPUT ;
    USE SIGNAL ;
    PORT
      LAYER M4 ;
        RECT  69.036 13.392 69.12 13.416 ;
    END
  END mv[130]
  PIN mv[131]
    DIRECTION INPUT ;
    USE SIGNAL ;
    PORT
      LAYER M4 ;
        RECT  69.036 13.488 69.12 13.512 ;
    END
  END mv[131]
  PIN mv[132]
    DIRECTION INPUT ;
    USE SIGNAL ;
    PORT
      LAYER M4 ;
        RECT  69.036 13.584 69.12 13.608 ;
    END
  END mv[132]
  PIN mv[133]
    DIRECTION INPUT ;
    USE SIGNAL ;
    PORT
      LAYER M4 ;
        RECT  69.036 13.68 69.12 13.704 ;
    END
  END mv[133]
  PIN mv[134]
    DIRECTION INPUT ;
    USE SIGNAL ;
    PORT
      LAYER M4 ;
        RECT  69.036 13.776 69.12 13.8 ;
    END
  END mv[134]
  PIN mv[135]
    DIRECTION INPUT ;
    USE SIGNAL ;
    PORT
      LAYER M4 ;
        RECT  69.036 13.872 69.12 13.896 ;
    END
  END mv[135]
  PIN mv[136]
    DIRECTION INPUT ;
    USE SIGNAL ;
    PORT
      LAYER M4 ;
        RECT  69.036 13.968 69.12 13.992 ;
    END
  END mv[136]
  PIN mv[137]
    DIRECTION INPUT ;
    USE SIGNAL ;
    PORT
      LAYER M4 ;
        RECT  69.036 14.064 69.12 14.088 ;
    END
  END mv[137]
  PIN mv[138]
    DIRECTION INPUT ;
    USE SIGNAL ;
    PORT
      LAYER M4 ;
        RECT  69.036 14.16 69.12 14.184 ;
    END
  END mv[138]
  PIN mv[139]
    DIRECTION INPUT ;
    USE SIGNAL ;
    PORT
      LAYER M4 ;
        RECT  69.036 14.256 69.12 14.28 ;
    END
  END mv[139]
  PIN mv[13]
    DIRECTION INPUT ;
    USE SIGNAL ;
    PORT
      LAYER M4 ;
        RECT  69.036 30.576 69.12 30.6 ;
    END
  END mv[13]
  PIN mv[140]
    DIRECTION INPUT ;
    USE SIGNAL ;
    PORT
      LAYER M4 ;
        RECT  69.036 14.352 69.12 14.376 ;
    END
  END mv[140]
  PIN mv[141]
    DIRECTION INPUT ;
    USE SIGNAL ;
    PORT
      LAYER M4 ;
        RECT  69.036 14.448 69.12 14.472 ;
    END
  END mv[141]
  PIN mv[142]
    DIRECTION INPUT ;
    USE SIGNAL ;
    PORT
      LAYER M4 ;
        RECT  69.036 14.544 69.12 14.568 ;
    END
  END mv[142]
  PIN mv[143]
    DIRECTION INPUT ;
    USE SIGNAL ;
    PORT
      LAYER M4 ;
        RECT  69.036 14.64 69.12 14.664 ;
    END
  END mv[143]
  PIN mv[144]
    DIRECTION INPUT ;
    USE SIGNAL ;
    PORT
      LAYER M4 ;
        RECT  69.036 14.736 69.12 14.76 ;
    END
  END mv[144]
  PIN mv[145]
    DIRECTION INPUT ;
    USE SIGNAL ;
    PORT
      LAYER M4 ;
        RECT  69.036 14.832 69.12 14.856 ;
    END
  END mv[145]
  PIN mv[146]
    DIRECTION INPUT ;
    USE SIGNAL ;
    PORT
      LAYER M4 ;
        RECT  69.036 14.928 69.12 14.952 ;
    END
  END mv[146]
  PIN mv[147]
    DIRECTION INPUT ;
    USE SIGNAL ;
    PORT
      LAYER M4 ;
        RECT  69.036 15.024 69.12 15.048 ;
    END
  END mv[147]
  PIN mv[148]
    DIRECTION INPUT ;
    USE SIGNAL ;
    PORT
      LAYER M4 ;
        RECT  69.036 15.12 69.12 15.144 ;
    END
  END mv[148]
  PIN mv[149]
    DIRECTION INPUT ;
    USE SIGNAL ;
    PORT
      LAYER M4 ;
        RECT  69.036 15.216 69.12 15.24 ;
    END
  END mv[149]
  PIN mv[14]
    DIRECTION INPUT ;
    USE SIGNAL ;
    PORT
      LAYER M4 ;
        RECT  69.036 30.672 69.12 30.696 ;
    END
  END mv[14]
  PIN mv[150]
    DIRECTION INPUT ;
    USE SIGNAL ;
    PORT
      LAYER M4 ;
        RECT  69.036 15.312 69.12 15.336 ;
    END
  END mv[150]
  PIN mv[151]
    DIRECTION INPUT ;
    USE SIGNAL ;
    PORT
      LAYER M4 ;
        RECT  69.036 15.408 69.12 15.432 ;
    END
  END mv[151]
  PIN mv[152]
    DIRECTION INPUT ;
    USE SIGNAL ;
    PORT
      LAYER M4 ;
        RECT  69.036 15.504 69.12 15.528 ;
    END
  END mv[152]
  PIN mv[153]
    DIRECTION INPUT ;
    USE SIGNAL ;
    PORT
      LAYER M4 ;
        RECT  69.036 15.6 69.12 15.624 ;
    END
  END mv[153]
  PIN mv[154]
    DIRECTION INPUT ;
    USE SIGNAL ;
    PORT
      LAYER M4 ;
        RECT  69.036 15.696 69.12 15.72 ;
    END
  END mv[154]
  PIN mv[155]
    DIRECTION INPUT ;
    USE SIGNAL ;
    PORT
      LAYER M4 ;
        RECT  69.036 15.792 69.12 15.816 ;
    END
  END mv[155]
  PIN mv[156]
    DIRECTION INPUT ;
    USE SIGNAL ;
    PORT
      LAYER M4 ;
        RECT  69.036 15.888 69.12 15.912 ;
    END
  END mv[156]
  PIN mv[157]
    DIRECTION INPUT ;
    USE SIGNAL ;
    PORT
      LAYER M4 ;
        RECT  69.036 15.984 69.12 16.008 ;
    END
  END mv[157]
  PIN mv[158]
    DIRECTION INPUT ;
    USE SIGNAL ;
    PORT
      LAYER M4 ;
        RECT  69.036 16.08 69.12 16.104 ;
    END
  END mv[158]
  PIN mv[159]
    DIRECTION INPUT ;
    USE SIGNAL ;
    PORT
      LAYER M4 ;
        RECT  69.036 16.176 69.12 16.2 ;
    END
  END mv[159]
  PIN mv[15]
    DIRECTION INPUT ;
    USE SIGNAL ;
    PORT
      LAYER M4 ;
        RECT  69.036 30.768 69.12 30.792 ;
    END
  END mv[15]
  PIN mv[160]
    DIRECTION INPUT ;
    USE SIGNAL ;
    PORT
      LAYER M4 ;
        RECT  69.036 16.272 69.12 16.296 ;
    END
  END mv[160]
  PIN mv[161]
    DIRECTION INPUT ;
    USE SIGNAL ;
    PORT
      LAYER M4 ;
        RECT  69.036 16.368 69.12 16.392 ;
    END
  END mv[161]
  PIN mv[162]
    DIRECTION INPUT ;
    USE SIGNAL ;
    PORT
      LAYER M4 ;
        RECT  69.036 16.464 69.12 16.488 ;
    END
  END mv[162]
  PIN mv[163]
    DIRECTION INPUT ;
    USE SIGNAL ;
    PORT
      LAYER M4 ;
        RECT  69.036 16.56 69.12 16.584 ;
    END
  END mv[163]
  PIN mv[164]
    DIRECTION INPUT ;
    USE SIGNAL ;
    PORT
      LAYER M4 ;
        RECT  69.036 16.656 69.12 16.68 ;
    END
  END mv[164]
  PIN mv[165]
    DIRECTION INPUT ;
    USE SIGNAL ;
    PORT
      LAYER M4 ;
        RECT  69.036 16.752 69.12 16.776 ;
    END
  END mv[165]
  PIN mv[166]
    DIRECTION INPUT ;
    USE SIGNAL ;
    PORT
      LAYER M4 ;
        RECT  69.036 16.848 69.12 16.872 ;
    END
  END mv[166]
  PIN mv[167]
    DIRECTION INPUT ;
    USE SIGNAL ;
    PORT
      LAYER M4 ;
        RECT  69.036 16.944 69.12 16.968 ;
    END
  END mv[167]
  PIN mv[168]
    DIRECTION INPUT ;
    USE SIGNAL ;
    PORT
      LAYER M4 ;
        RECT  69.036 17.04 69.12 17.064 ;
    END
  END mv[168]
  PIN mv[169]
    DIRECTION INPUT ;
    USE SIGNAL ;
    PORT
      LAYER M4 ;
        RECT  69.036 17.136 69.12 17.16 ;
    END
  END mv[169]
  PIN mv[16]
    DIRECTION INPUT ;
    USE SIGNAL ;
    PORT
      LAYER M4 ;
        RECT  69.036 30.864 69.12 30.888 ;
    END
  END mv[16]
  PIN mv[170]
    DIRECTION INPUT ;
    USE SIGNAL ;
    PORT
      LAYER M4 ;
        RECT  69.036 17.232 69.12 17.256 ;
    END
  END mv[170]
  PIN mv[171]
    DIRECTION INPUT ;
    USE SIGNAL ;
    PORT
      LAYER M4 ;
        RECT  69.036 17.328 69.12 17.352 ;
    END
  END mv[171]
  PIN mv[172]
    DIRECTION INPUT ;
    USE SIGNAL ;
    PORT
      LAYER M4 ;
        RECT  69.036 17.424 69.12 17.448 ;
    END
  END mv[172]
  PIN mv[173]
    DIRECTION INPUT ;
    USE SIGNAL ;
    PORT
      LAYER M4 ;
        RECT  69.036 17.52 69.12 17.544 ;
    END
  END mv[173]
  PIN mv[174]
    DIRECTION INPUT ;
    USE SIGNAL ;
    PORT
      LAYER M4 ;
        RECT  69.036 17.616 69.12 17.64 ;
    END
  END mv[174]
  PIN mv[175]
    DIRECTION INPUT ;
    USE SIGNAL ;
    PORT
      LAYER M4 ;
        RECT  69.036 17.712 69.12 17.736 ;
    END
  END mv[175]
  PIN mv[176]
    DIRECTION INPUT ;
    USE SIGNAL ;
    PORT
      LAYER M4 ;
        RECT  69.036 17.808 69.12 17.832 ;
    END
  END mv[176]
  PIN mv[177]
    DIRECTION INPUT ;
    USE SIGNAL ;
    PORT
      LAYER M4 ;
        RECT  69.036 17.904 69.12 17.928 ;
    END
  END mv[177]
  PIN mv[178]
    DIRECTION INPUT ;
    USE SIGNAL ;
    PORT
      LAYER M4 ;
        RECT  69.036 18 69.12 18.024 ;
    END
  END mv[178]
  PIN mv[179]
    DIRECTION INPUT ;
    USE SIGNAL ;
    PORT
      LAYER M4 ;
        RECT  69.036 18.096 69.12 18.12 ;
    END
  END mv[179]
  PIN mv[17]
    DIRECTION INPUT ;
    USE SIGNAL ;
    PORT
      LAYER M4 ;
        RECT  69.036 30.96 69.12 30.984 ;
    END
  END mv[17]
  PIN mv[180]
    DIRECTION INPUT ;
    USE SIGNAL ;
    PORT
      LAYER M4 ;
        RECT  69.036 18.192 69.12 18.216 ;
    END
  END mv[180]
  PIN mv[181]
    DIRECTION INPUT ;
    USE SIGNAL ;
    PORT
      LAYER M4 ;
        RECT  69.036 18.288 69.12 18.312 ;
    END
  END mv[181]
  PIN mv[182]
    DIRECTION INPUT ;
    USE SIGNAL ;
    PORT
      LAYER M4 ;
        RECT  69.036 18.384 69.12 18.408 ;
    END
  END mv[182]
  PIN mv[183]
    DIRECTION INPUT ;
    USE SIGNAL ;
    PORT
      LAYER M4 ;
        RECT  69.036 18.48 69.12 18.504 ;
    END
  END mv[183]
  PIN mv[184]
    DIRECTION INPUT ;
    USE SIGNAL ;
    PORT
      LAYER M4 ;
        RECT  69.036 18.576 69.12 18.6 ;
    END
  END mv[184]
  PIN mv[185]
    DIRECTION INPUT ;
    USE SIGNAL ;
    PORT
      LAYER M4 ;
        RECT  69.036 18.672 69.12 18.696 ;
    END
  END mv[185]
  PIN mv[186]
    DIRECTION INPUT ;
    USE SIGNAL ;
    PORT
      LAYER M4 ;
        RECT  69.036 18.768 69.12 18.792 ;
    END
  END mv[186]
  PIN mv[187]
    DIRECTION INPUT ;
    USE SIGNAL ;
    PORT
      LAYER M4 ;
        RECT  69.036 18.864 69.12 18.888 ;
    END
  END mv[187]
  PIN mv[188]
    DIRECTION INPUT ;
    USE SIGNAL ;
    PORT
      LAYER M4 ;
        RECT  69.036 18.96 69.12 18.984 ;
    END
  END mv[188]
  PIN mv[189]
    DIRECTION INPUT ;
    USE SIGNAL ;
    PORT
      LAYER M4 ;
        RECT  69.036 19.056 69.12 19.08 ;
    END
  END mv[189]
  PIN mv[18]
    DIRECTION INPUT ;
    USE SIGNAL ;
    PORT
      LAYER M4 ;
        RECT  69.036 31.056 69.12 31.08 ;
    END
  END mv[18]
  PIN mv[190]
    DIRECTION INPUT ;
    USE SIGNAL ;
    PORT
      LAYER M4 ;
        RECT  69.036 42.192 69.12 42.216 ;
    END
  END mv[190]
  PIN mv[191]
    DIRECTION INPUT ;
    USE SIGNAL ;
    PORT
      LAYER M4 ;
        RECT  69.036 42.288 69.12 42.312 ;
    END
  END mv[191]
  PIN mv[192]
    DIRECTION INPUT ;
    USE SIGNAL ;
    PORT
      LAYER M4 ;
        RECT  69.036 42.384 69.12 42.408 ;
    END
  END mv[192]
  PIN mv[193]
    DIRECTION INPUT ;
    USE SIGNAL ;
    PORT
      LAYER M4 ;
        RECT  69.036 42.48 69.12 42.504 ;
    END
  END mv[193]
  PIN mv[194]
    DIRECTION INPUT ;
    USE SIGNAL ;
    PORT
      LAYER M4 ;
        RECT  69.036 42.576 69.12 42.6 ;
    END
  END mv[194]
  PIN mv[195]
    DIRECTION INPUT ;
    USE SIGNAL ;
    PORT
      LAYER M4 ;
        RECT  69.036 42.672 69.12 42.696 ;
    END
  END mv[195]
  PIN mv[196]
    DIRECTION INPUT ;
    USE SIGNAL ;
    PORT
      LAYER M4 ;
        RECT  69.036 42.768 69.12 42.792 ;
    END
  END mv[196]
  PIN mv[197]
    DIRECTION INPUT ;
    USE SIGNAL ;
    PORT
      LAYER M4 ;
        RECT  69.036 42.864 69.12 42.888 ;
    END
  END mv[197]
  PIN mv[198]
    DIRECTION INPUT ;
    USE SIGNAL ;
    PORT
      LAYER M4 ;
        RECT  69.036 42.96 69.12 42.984 ;
    END
  END mv[198]
  PIN mv[199]
    DIRECTION INPUT ;
    USE SIGNAL ;
    PORT
      LAYER M4 ;
        RECT  69.036 43.056 69.12 43.08 ;
    END
  END mv[199]
  PIN mv[19]
    DIRECTION INPUT ;
    USE SIGNAL ;
    PORT
      LAYER M4 ;
        RECT  69.036 31.152 69.12 31.176 ;
    END
  END mv[19]
  PIN mv[1]
    DIRECTION INPUT ;
    USE SIGNAL ;
    PORT
      LAYER M4 ;
        RECT  69.036 29.424 69.12 29.448 ;
    END
  END mv[1]
  PIN mv[200]
    DIRECTION INPUT ;
    USE SIGNAL ;
    PORT
      LAYER M4 ;
        RECT  69.036 43.152 69.12 43.176 ;
    END
  END mv[200]
  PIN mv[201]
    DIRECTION INPUT ;
    USE SIGNAL ;
    PORT
      LAYER M4 ;
        RECT  69.036 43.248 69.12 43.272 ;
    END
  END mv[201]
  PIN mv[202]
    DIRECTION INPUT ;
    USE SIGNAL ;
    PORT
      LAYER M4 ;
        RECT  69.036 43.344 69.12 43.368 ;
    END
  END mv[202]
  PIN mv[203]
    DIRECTION INPUT ;
    USE SIGNAL ;
    PORT
      LAYER M4 ;
        RECT  69.036 43.44 69.12 43.464 ;
    END
  END mv[203]
  PIN mv[204]
    DIRECTION INPUT ;
    USE SIGNAL ;
    PORT
      LAYER M4 ;
        RECT  69.036 43.536 69.12 43.56 ;
    END
  END mv[204]
  PIN mv[205]
    DIRECTION INPUT ;
    USE SIGNAL ;
    PORT
      LAYER M4 ;
        RECT  69.036 43.632 69.12 43.656 ;
    END
  END mv[205]
  PIN mv[206]
    DIRECTION INPUT ;
    USE SIGNAL ;
    PORT
      LAYER M4 ;
        RECT  69.036 43.728 69.12 43.752 ;
    END
  END mv[206]
  PIN mv[207]
    DIRECTION INPUT ;
    USE SIGNAL ;
    PORT
      LAYER M4 ;
        RECT  69.036 43.824 69.12 43.848 ;
    END
  END mv[207]
  PIN mv[208]
    DIRECTION INPUT ;
    USE SIGNAL ;
    PORT
      LAYER M4 ;
        RECT  69.036 43.92 69.12 43.944 ;
    END
  END mv[208]
  PIN mv[209]
    DIRECTION INPUT ;
    USE SIGNAL ;
    PORT
      LAYER M4 ;
        RECT  69.036 44.016 69.12 44.04 ;
    END
  END mv[209]
  PIN mv[20]
    DIRECTION INPUT ;
    USE SIGNAL ;
    PORT
      LAYER M4 ;
        RECT  69.036 31.248 69.12 31.272 ;
    END
  END mv[20]
  PIN mv[210]
    DIRECTION INPUT ;
    USE SIGNAL ;
    PORT
      LAYER M4 ;
        RECT  69.036 44.112 69.12 44.136 ;
    END
  END mv[210]
  PIN mv[211]
    DIRECTION INPUT ;
    USE SIGNAL ;
    PORT
      LAYER M4 ;
        RECT  69.036 44.208 69.12 44.232 ;
    END
  END mv[211]
  PIN mv[212]
    DIRECTION INPUT ;
    USE SIGNAL ;
    PORT
      LAYER M4 ;
        RECT  69.036 44.304 69.12 44.328 ;
    END
  END mv[212]
  PIN mv[213]
    DIRECTION INPUT ;
    USE SIGNAL ;
    PORT
      LAYER M4 ;
        RECT  69.036 44.4 69.12 44.424 ;
    END
  END mv[213]
  PIN mv[214]
    DIRECTION INPUT ;
    USE SIGNAL ;
    PORT
      LAYER M4 ;
        RECT  69.036 44.496 69.12 44.52 ;
    END
  END mv[214]
  PIN mv[215]
    DIRECTION INPUT ;
    USE SIGNAL ;
    PORT
      LAYER M4 ;
        RECT  69.036 44.592 69.12 44.616 ;
    END
  END mv[215]
  PIN mv[216]
    DIRECTION INPUT ;
    USE SIGNAL ;
    PORT
      LAYER M4 ;
        RECT  69.036 44.688 69.12 44.712 ;
    END
  END mv[216]
  PIN mv[217]
    DIRECTION INPUT ;
    USE SIGNAL ;
    PORT
      LAYER M4 ;
        RECT  69.036 44.784 69.12 44.808 ;
    END
  END mv[217]
  PIN mv[218]
    DIRECTION INPUT ;
    USE SIGNAL ;
    PORT
      LAYER M4 ;
        RECT  69.036 44.88 69.12 44.904 ;
    END
  END mv[218]
  PIN mv[219]
    DIRECTION INPUT ;
    USE SIGNAL ;
    PORT
      LAYER M4 ;
        RECT  69.036 44.976 69.12 45 ;
    END
  END mv[219]
  PIN mv[21]
    DIRECTION INPUT ;
    USE SIGNAL ;
    PORT
      LAYER M4 ;
        RECT  69.036 31.344 69.12 31.368 ;
    END
  END mv[21]
  PIN mv[220]
    DIRECTION INPUT ;
    USE SIGNAL ;
    PORT
      LAYER M4 ;
        RECT  69.036 45.072 69.12 45.096 ;
    END
  END mv[220]
  PIN mv[221]
    DIRECTION INPUT ;
    USE SIGNAL ;
    PORT
      LAYER M4 ;
        RECT  69.036 45.168 69.12 45.192 ;
    END
  END mv[221]
  PIN mv[222]
    DIRECTION INPUT ;
    USE SIGNAL ;
    PORT
      LAYER M4 ;
        RECT  69.036 9.936 69.12 9.96 ;
    END
  END mv[222]
  PIN mv[223]
    DIRECTION INPUT ;
    USE SIGNAL ;
    PORT
      LAYER M4 ;
        RECT  69.036 10.032 69.12 10.056 ;
    END
  END mv[223]
  PIN mv[224]
    DIRECTION INPUT ;
    USE SIGNAL ;
    PORT
      LAYER M4 ;
        RECT  69.036 10.128 69.12 10.152 ;
    END
  END mv[224]
  PIN mv[225]
    DIRECTION INPUT ;
    USE SIGNAL ;
    PORT
      LAYER M4 ;
        RECT  69.036 10.224 69.12 10.248 ;
    END
  END mv[225]
  PIN mv[226]
    DIRECTION INPUT ;
    USE SIGNAL ;
    PORT
      LAYER M4 ;
        RECT  69.036 10.32 69.12 10.344 ;
    END
  END mv[226]
  PIN mv[22]
    DIRECTION INPUT ;
    USE SIGNAL ;
    PORT
      LAYER M4 ;
        RECT  69.036 31.44 69.12 31.464 ;
    END
  END mv[22]
  PIN mv[23]
    DIRECTION INPUT ;
    USE SIGNAL ;
    PORT
      LAYER M4 ;
        RECT  69.036 31.536 69.12 31.56 ;
    END
  END mv[23]
  PIN mv[24]
    DIRECTION INPUT ;
    USE SIGNAL ;
    PORT
      LAYER M4 ;
        RECT  69.036 31.632 69.12 31.656 ;
    END
  END mv[24]
  PIN mv[25]
    DIRECTION INPUT ;
    USE SIGNAL ;
    PORT
      LAYER M4 ;
        RECT  69.036 31.728 69.12 31.752 ;
    END
  END mv[25]
  PIN mv[26]
    DIRECTION INPUT ;
    USE SIGNAL ;
    PORT
      LAYER M4 ;
        RECT  69.036 31.824 69.12 31.848 ;
    END
  END mv[26]
  PIN mv[27]
    DIRECTION INPUT ;
    USE SIGNAL ;
    PORT
      LAYER M4 ;
        RECT  69.036 31.92 69.12 31.944 ;
    END
  END mv[27]
  PIN mv[28]
    DIRECTION INPUT ;
    USE SIGNAL ;
    PORT
      LAYER M4 ;
        RECT  69.036 32.016 69.12 32.04 ;
    END
  END mv[28]
  PIN mv[29]
    DIRECTION INPUT ;
    USE SIGNAL ;
    PORT
      LAYER M4 ;
        RECT  69.036 32.112 69.12 32.136 ;
    END
  END mv[29]
  PIN mv[2]
    DIRECTION INPUT ;
    USE SIGNAL ;
    PORT
      LAYER M4 ;
        RECT  69.036 29.52 69.12 29.544 ;
    END
  END mv[2]
  PIN mv[30]
    DIRECTION INPUT ;
    USE SIGNAL ;
    PORT
      LAYER M4 ;
        RECT  69.036 32.208 69.12 32.232 ;
    END
  END mv[30]
  PIN mv[31]
    DIRECTION INPUT ;
    USE SIGNAL ;
    PORT
      LAYER M4 ;
        RECT  69.036 32.304 69.12 32.328 ;
    END
  END mv[31]
  PIN mv[32]
    DIRECTION INPUT ;
    USE SIGNAL ;
    PORT
      LAYER M4 ;
        RECT  69.036 32.4 69.12 32.424 ;
    END
  END mv[32]
  PIN mv[33]
    DIRECTION INPUT ;
    USE SIGNAL ;
    PORT
      LAYER M4 ;
        RECT  69.036 32.496 69.12 32.52 ;
    END
  END mv[33]
  PIN mv[34]
    DIRECTION INPUT ;
    USE SIGNAL ;
    PORT
      LAYER M4 ;
        RECT  69.036 32.592 69.12 32.616 ;
    END
  END mv[34]
  PIN mv[35]
    DIRECTION INPUT ;
    USE SIGNAL ;
    PORT
      LAYER M4 ;
        RECT  69.036 32.688 69.12 32.712 ;
    END
  END mv[35]
  PIN mv[36]
    DIRECTION INPUT ;
    USE SIGNAL ;
    PORT
      LAYER M4 ;
        RECT  69.036 32.784 69.12 32.808 ;
    END
  END mv[36]
  PIN mv[37]
    DIRECTION INPUT ;
    USE SIGNAL ;
    PORT
      LAYER M4 ;
        RECT  69.036 32.88 69.12 32.904 ;
    END
  END mv[37]
  PIN mv[38]
    DIRECTION INPUT ;
    USE SIGNAL ;
    PORT
      LAYER M4 ;
        RECT  69.036 32.976 69.12 33 ;
    END
  END mv[38]
  PIN mv[39]
    DIRECTION INPUT ;
    USE SIGNAL ;
    PORT
      LAYER M4 ;
        RECT  69.036 33.072 69.12 33.096 ;
    END
  END mv[39]
  PIN mv[3]
    DIRECTION INPUT ;
    USE SIGNAL ;
    PORT
      LAYER M4 ;
        RECT  69.036 29.616 69.12 29.64 ;
    END
  END mv[3]
  PIN mv[40]
    DIRECTION INPUT ;
    USE SIGNAL ;
    PORT
      LAYER M4 ;
        RECT  69.036 33.168 69.12 33.192 ;
    END
  END mv[40]
  PIN mv[41]
    DIRECTION INPUT ;
    USE SIGNAL ;
    PORT
      LAYER M4 ;
        RECT  69.036 33.264 69.12 33.288 ;
    END
  END mv[41]
  PIN mv[42]
    DIRECTION INPUT ;
    USE SIGNAL ;
    PORT
      LAYER M4 ;
        RECT  69.036 33.36 69.12 33.384 ;
    END
  END mv[42]
  PIN mv[43]
    DIRECTION INPUT ;
    USE SIGNAL ;
    PORT
      LAYER M4 ;
        RECT  69.036 33.456 69.12 33.48 ;
    END
  END mv[43]
  PIN mv[44]
    DIRECTION INPUT ;
    USE SIGNAL ;
    PORT
      LAYER M4 ;
        RECT  69.036 33.552 69.12 33.576 ;
    END
  END mv[44]
  PIN mv[45]
    DIRECTION INPUT ;
    USE SIGNAL ;
    PORT
      LAYER M4 ;
        RECT  69.036 33.648 69.12 33.672 ;
    END
  END mv[45]
  PIN mv[46]
    DIRECTION INPUT ;
    USE SIGNAL ;
    PORT
      LAYER M4 ;
        RECT  69.036 33.744 69.12 33.768 ;
    END
  END mv[46]
  PIN mv[47]
    DIRECTION INPUT ;
    USE SIGNAL ;
    PORT
      LAYER M4 ;
        RECT  69.036 33.84 69.12 33.864 ;
    END
  END mv[47]
  PIN mv[48]
    DIRECTION INPUT ;
    USE SIGNAL ;
    PORT
      LAYER M4 ;
        RECT  69.036 33.936 69.12 33.96 ;
    END
  END mv[48]
  PIN mv[49]
    DIRECTION INPUT ;
    USE SIGNAL ;
    PORT
      LAYER M4 ;
        RECT  69.036 34.032 69.12 34.056 ;
    END
  END mv[49]
  PIN mv[4]
    DIRECTION INPUT ;
    USE SIGNAL ;
    PORT
      LAYER M4 ;
        RECT  69.036 29.712 69.12 29.736 ;
    END
  END mv[4]
  PIN mv[50]
    DIRECTION INPUT ;
    USE SIGNAL ;
    PORT
      LAYER M4 ;
        RECT  69.036 34.128 69.12 34.152 ;
    END
  END mv[50]
  PIN mv[51]
    DIRECTION INPUT ;
    USE SIGNAL ;
    PORT
      LAYER M4 ;
        RECT  69.036 34.224 69.12 34.248 ;
    END
  END mv[51]
  PIN mv[52]
    DIRECTION INPUT ;
    USE SIGNAL ;
    PORT
      LAYER M4 ;
        RECT  69.036 34.32 69.12 34.344 ;
    END
  END mv[52]
  PIN mv[53]
    DIRECTION INPUT ;
    USE SIGNAL ;
    PORT
      LAYER M4 ;
        RECT  69.036 34.416 69.12 34.44 ;
    END
  END mv[53]
  PIN mv[54]
    DIRECTION INPUT ;
    USE SIGNAL ;
    PORT
      LAYER M4 ;
        RECT  69.036 34.512 69.12 34.536 ;
    END
  END mv[54]
  PIN mv[55]
    DIRECTION INPUT ;
    USE SIGNAL ;
    PORT
      LAYER M4 ;
        RECT  69.036 34.608 69.12 34.632 ;
    END
  END mv[55]
  PIN mv[56]
    DIRECTION INPUT ;
    USE SIGNAL ;
    PORT
      LAYER M4 ;
        RECT  69.036 34.704 69.12 34.728 ;
    END
  END mv[56]
  PIN mv[57]
    DIRECTION INPUT ;
    USE SIGNAL ;
    PORT
      LAYER M4 ;
        RECT  69.036 34.8 69.12 34.824 ;
    END
  END mv[57]
  PIN mv[58]
    DIRECTION INPUT ;
    USE SIGNAL ;
    PORT
      LAYER M4 ;
        RECT  69.036 34.896 69.12 34.92 ;
    END
  END mv[58]
  PIN mv[59]
    DIRECTION INPUT ;
    USE SIGNAL ;
    PORT
      LAYER M4 ;
        RECT  69.036 34.992 69.12 35.016 ;
    END
  END mv[59]
  PIN mv[5]
    DIRECTION INPUT ;
    USE SIGNAL ;
    PORT
      LAYER M4 ;
        RECT  69.036 29.808 69.12 29.832 ;
    END
  END mv[5]
  PIN mv[60]
    DIRECTION INPUT ;
    USE SIGNAL ;
    PORT
      LAYER M4 ;
        RECT  69.036 35.088 69.12 35.112 ;
    END
  END mv[60]
  PIN mv[61]
    DIRECTION INPUT ;
    USE SIGNAL ;
    PORT
      LAYER M4 ;
        RECT  69.036 35.184 69.12 35.208 ;
    END
  END mv[61]
  PIN mv[62]
    DIRECTION INPUT ;
    USE SIGNAL ;
    PORT
      LAYER M4 ;
        RECT  69.036 26.064 69.12 26.088 ;
    END
  END mv[62]
  PIN mv[63]
    DIRECTION INPUT ;
    USE SIGNAL ;
    PORT
      LAYER M4 ;
        RECT  69.036 26.16 69.12 26.184 ;
    END
  END mv[63]
  PIN mv[64]
    DIRECTION INPUT ;
    USE SIGNAL ;
    PORT
      LAYER M4 ;
        RECT  69.036 26.256 69.12 26.28 ;
    END
  END mv[64]
  PIN mv[65]
    DIRECTION INPUT ;
    USE SIGNAL ;
    PORT
      LAYER M4 ;
        RECT  69.036 26.352 69.12 26.376 ;
    END
  END mv[65]
  PIN mv[66]
    DIRECTION INPUT ;
    USE SIGNAL ;
    PORT
      LAYER M4 ;
        RECT  69.036 26.448 69.12 26.472 ;
    END
  END mv[66]
  PIN mv[67]
    DIRECTION INPUT ;
    USE SIGNAL ;
    PORT
      LAYER M4 ;
        RECT  69.036 26.544 69.12 26.568 ;
    END
  END mv[67]
  PIN mv[68]
    DIRECTION INPUT ;
    USE SIGNAL ;
    PORT
      LAYER M4 ;
        RECT  69.036 26.64 69.12 26.664 ;
    END
  END mv[68]
  PIN mv[69]
    DIRECTION INPUT ;
    USE SIGNAL ;
    PORT
      LAYER M4 ;
        RECT  69.036 26.736 69.12 26.76 ;
    END
  END mv[69]
  PIN mv[6]
    DIRECTION INPUT ;
    USE SIGNAL ;
    PORT
      LAYER M4 ;
        RECT  69.036 29.904 69.12 29.928 ;
    END
  END mv[6]
  PIN mv[70]
    DIRECTION INPUT ;
    USE SIGNAL ;
    PORT
      LAYER M4 ;
        RECT  69.036 26.832 69.12 26.856 ;
    END
  END mv[70]
  PIN mv[71]
    DIRECTION INPUT ;
    USE SIGNAL ;
    PORT
      LAYER M4 ;
        RECT  69.036 26.928 69.12 26.952 ;
    END
  END mv[71]
  PIN mv[72]
    DIRECTION INPUT ;
    USE SIGNAL ;
    PORT
      LAYER M4 ;
        RECT  69.036 27.024 69.12 27.048 ;
    END
  END mv[72]
  PIN mv[73]
    DIRECTION INPUT ;
    USE SIGNAL ;
    PORT
      LAYER M4 ;
        RECT  69.036 27.12 69.12 27.144 ;
    END
  END mv[73]
  PIN mv[74]
    DIRECTION INPUT ;
    USE SIGNAL ;
    PORT
      LAYER M4 ;
        RECT  69.036 27.216 69.12 27.24 ;
    END
  END mv[74]
  PIN mv[75]
    DIRECTION INPUT ;
    USE SIGNAL ;
    PORT
      LAYER M4 ;
        RECT  69.036 27.312 69.12 27.336 ;
    END
  END mv[75]
  PIN mv[76]
    DIRECTION INPUT ;
    USE SIGNAL ;
    PORT
      LAYER M4 ;
        RECT  69.036 27.408 69.12 27.432 ;
    END
  END mv[76]
  PIN mv[77]
    DIRECTION INPUT ;
    USE SIGNAL ;
    PORT
      LAYER M4 ;
        RECT  69.036 27.504 69.12 27.528 ;
    END
  END mv[77]
  PIN mv[78]
    DIRECTION INPUT ;
    USE SIGNAL ;
    PORT
      LAYER M4 ;
        RECT  69.036 27.6 69.12 27.624 ;
    END
  END mv[78]
  PIN mv[79]
    DIRECTION INPUT ;
    USE SIGNAL ;
    PORT
      LAYER M4 ;
        RECT  69.036 27.696 69.12 27.72 ;
    END
  END mv[79]
  PIN mv[7]
    DIRECTION INPUT ;
    USE SIGNAL ;
    PORT
      LAYER M4 ;
        RECT  69.036 30 69.12 30.024 ;
    END
  END mv[7]
  PIN mv[80]
    DIRECTION INPUT ;
    USE SIGNAL ;
    PORT
      LAYER M4 ;
        RECT  69.036 27.792 69.12 27.816 ;
    END
  END mv[80]
  PIN mv[81]
    DIRECTION INPUT ;
    USE SIGNAL ;
    PORT
      LAYER M4 ;
        RECT  69.036 27.888 69.12 27.912 ;
    END
  END mv[81]
  PIN mv[82]
    DIRECTION INPUT ;
    USE SIGNAL ;
    PORT
      LAYER M4 ;
        RECT  69.036 27.984 69.12 28.008 ;
    END
  END mv[82]
  PIN mv[83]
    DIRECTION INPUT ;
    USE SIGNAL ;
    PORT
      LAYER M4 ;
        RECT  69.036 28.08 69.12 28.104 ;
    END
  END mv[83]
  PIN mv[84]
    DIRECTION INPUT ;
    USE SIGNAL ;
    PORT
      LAYER M4 ;
        RECT  69.036 28.176 69.12 28.2 ;
    END
  END mv[84]
  PIN mv[85]
    DIRECTION INPUT ;
    USE SIGNAL ;
    PORT
      LAYER M4 ;
        RECT  69.036 28.272 69.12 28.296 ;
    END
  END mv[85]
  PIN mv[86]
    DIRECTION INPUT ;
    USE SIGNAL ;
    PORT
      LAYER M4 ;
        RECT  69.036 28.368 69.12 28.392 ;
    END
  END mv[86]
  PIN mv[87]
    DIRECTION INPUT ;
    USE SIGNAL ;
    PORT
      LAYER M4 ;
        RECT  69.036 28.464 69.12 28.488 ;
    END
  END mv[87]
  PIN mv[88]
    DIRECTION INPUT ;
    USE SIGNAL ;
    PORT
      LAYER M4 ;
        RECT  69.036 28.56 69.12 28.584 ;
    END
  END mv[88]
  PIN mv[89]
    DIRECTION INPUT ;
    USE SIGNAL ;
    PORT
      LAYER M4 ;
        RECT  69.036 28.656 69.12 28.68 ;
    END
  END mv[89]
  PIN mv[8]
    DIRECTION INPUT ;
    USE SIGNAL ;
    PORT
      LAYER M4 ;
        RECT  69.036 30.096 69.12 30.12 ;
    END
  END mv[8]
  PIN mv[90]
    DIRECTION INPUT ;
    USE SIGNAL ;
    PORT
      LAYER M4 ;
        RECT  69.036 28.752 69.12 28.776 ;
    END
  END mv[90]
  PIN mv[91]
    DIRECTION INPUT ;
    USE SIGNAL ;
    PORT
      LAYER M4 ;
        RECT  69.036 28.848 69.12 28.872 ;
    END
  END mv[91]
  PIN mv[92]
    DIRECTION INPUT ;
    USE SIGNAL ;
    PORT
      LAYER M4 ;
        RECT  69.036 28.944 69.12 28.968 ;
    END
  END mv[92]
  PIN mv[93]
    DIRECTION INPUT ;
    USE SIGNAL ;
    PORT
      LAYER M4 ;
        RECT  69.036 29.04 69.12 29.064 ;
    END
  END mv[93]
  PIN mv[94]
    DIRECTION INPUT ;
    USE SIGNAL ;
    PORT
      LAYER M4 ;
        RECT  69.036 6.864 69.12 6.888 ;
    END
  END mv[94]
  PIN mv[95]
    DIRECTION INPUT ;
    USE SIGNAL ;
    PORT
      LAYER M4 ;
        RECT  69.036 6.96 69.12 6.984 ;
    END
  END mv[95]
  PIN mv[96]
    DIRECTION INPUT ;
    USE SIGNAL ;
    PORT
      LAYER M4 ;
        RECT  69.036 7.056 69.12 7.08 ;
    END
  END mv[96]
  PIN mv[97]
    DIRECTION INPUT ;
    USE SIGNAL ;
    PORT
      LAYER M4 ;
        RECT  69.036 7.152 69.12 7.176 ;
    END
  END mv[97]
  PIN mv[98]
    DIRECTION INPUT ;
    USE SIGNAL ;
    PORT
      LAYER M4 ;
        RECT  69.036 7.248 69.12 7.272 ;
    END
  END mv[98]
  PIN mv[99]
    DIRECTION INPUT ;
    USE SIGNAL ;
    PORT
      LAYER M4 ;
        RECT  69.036 7.344 69.12 7.368 ;
    END
  END mv[99]
  PIN mv[9]
    DIRECTION INPUT ;
    USE SIGNAL ;
    PORT
      LAYER M4 ;
        RECT  69.036 30.192 69.12 30.216 ;
    END
  END mv[9]
  PIN mv_done
    DIRECTION OUTPUT ;
    USE SIGNAL ;
    PORT
      LAYER M4 ;
        RECT  69.036 10.416 69.12 10.44 ;
    END
  END mv_done
  PIN mv_fault
    DIRECTION OUTPUT ;
    USE SIGNAL ;
    PORT
      LAYER M4 ;
        RECT  69.036 10.512 69.12 10.536 ;
    END
  END mv_fault
  PIN mv_src
    DIRECTION OUTPUT ;
    USE SIGNAL ;
    PORT
      LAYER M4 ;
        RECT  69.036 10.608 69.12 10.632 ;
    END
  END mv_src
  PIN mv_v
    DIRECTION INPUT ;
    USE SIGNAL ;
    PORT
      LAYER M4 ;
        RECT  69.036 10.704 69.12 10.728 ;
    END
  END mv_v
  PIN mv_wb_bank
    DIRECTION INPUT ;
    USE SIGNAL ;
    PORT
      LAYER M4 ;
        RECT  69.036 10.8 69.12 10.824 ;
    END
  END mv_wb_bank
  PIN mv_wb_epoch[0]
    DIRECTION INPUT ;
    USE SIGNAL ;
    PORT
      LAYER M4 ;
        RECT  69.036 10.896 69.12 10.92 ;
    END
  END mv_wb_epoch[0]
  PIN mv_wb_epoch[10]
    DIRECTION INPUT ;
    USE SIGNAL ;
    PORT
      LAYER M4 ;
        RECT  69.036 11.856 69.12 11.88 ;
    END
  END mv_wb_epoch[10]
  PIN mv_wb_epoch[11]
    DIRECTION INPUT ;
    USE SIGNAL ;
    PORT
      LAYER M4 ;
        RECT  69.036 11.952 69.12 11.976 ;
    END
  END mv_wb_epoch[11]
  PIN mv_wb_epoch[12]
    DIRECTION INPUT ;
    USE SIGNAL ;
    PORT
      LAYER M4 ;
        RECT  69.036 12.048 69.12 12.072 ;
    END
  END mv_wb_epoch[12]
  PIN mv_wb_epoch[13]
    DIRECTION INPUT ;
    USE SIGNAL ;
    PORT
      LAYER M4 ;
        RECT  69.036 12.144 69.12 12.168 ;
    END
  END mv_wb_epoch[13]
  PIN mv_wb_epoch[14]
    DIRECTION INPUT ;
    USE SIGNAL ;
    PORT
      LAYER M4 ;
        RECT  69.036 12.24 69.12 12.264 ;
    END
  END mv_wb_epoch[14]
  PIN mv_wb_epoch[15]
    DIRECTION INPUT ;
    USE SIGNAL ;
    PORT
      LAYER M4 ;
        RECT  69.036 12.336 69.12 12.36 ;
    END
  END mv_wb_epoch[15]
  PIN mv_wb_epoch[1]
    DIRECTION INPUT ;
    USE SIGNAL ;
    PORT
      LAYER M4 ;
        RECT  69.036 10.992 69.12 11.016 ;
    END
  END mv_wb_epoch[1]
  PIN mv_wb_epoch[2]
    DIRECTION INPUT ;
    USE SIGNAL ;
    PORT
      LAYER M4 ;
        RECT  69.036 11.088 69.12 11.112 ;
    END
  END mv_wb_epoch[2]
  PIN mv_wb_epoch[3]
    DIRECTION INPUT ;
    USE SIGNAL ;
    PORT
      LAYER M4 ;
        RECT  69.036 11.184 69.12 11.208 ;
    END
  END mv_wb_epoch[3]
  PIN mv_wb_epoch[4]
    DIRECTION INPUT ;
    USE SIGNAL ;
    PORT
      LAYER M4 ;
        RECT  69.036 11.28 69.12 11.304 ;
    END
  END mv_wb_epoch[4]
  PIN mv_wb_epoch[5]
    DIRECTION INPUT ;
    USE SIGNAL ;
    PORT
      LAYER M4 ;
        RECT  69.036 11.376 69.12 11.4 ;
    END
  END mv_wb_epoch[5]
  PIN mv_wb_epoch[6]
    DIRECTION INPUT ;
    USE SIGNAL ;
    PORT
      LAYER M4 ;
        RECT  69.036 11.472 69.12 11.496 ;
    END
  END mv_wb_epoch[6]
  PIN mv_wb_epoch[7]
    DIRECTION INPUT ;
    USE SIGNAL ;
    PORT
      LAYER M4 ;
        RECT  69.036 11.568 69.12 11.592 ;
    END
  END mv_wb_epoch[7]
  PIN mv_wb_epoch[8]
    DIRECTION INPUT ;
    USE SIGNAL ;
    PORT
      LAYER M4 ;
        RECT  69.036 11.664 69.12 11.688 ;
    END
  END mv_wb_epoch[8]
  PIN mv_wb_epoch[9]
    DIRECTION INPUT ;
    USE SIGNAL ;
    PORT
      LAYER M4 ;
        RECT  69.036 11.76 69.12 11.784 ;
    END
  END mv_wb_epoch[9]
  PIN quiet
    DIRECTION OUTPUT ;
    USE SIGNAL ;
    PORT
      LAYER M4 ;
        RECT  69.036 12.432 69.12 12.456 ;
    END
  END quiet
  PIN rq[0]
    DIRECTION OUTPUT ;
    USE SIGNAL ;
    PORT
      LAYER M4 ;
        RECT  0 33.648 0.084 33.672 ;
    END
  END rq[0]
  PIN rq[100]
    DIRECTION OUTPUT ;
    USE SIGNAL ;
    PORT
      LAYER M4 ;
        RECT  0 40.176 0.084 40.2 ;
    END
  END rq[100]
  PIN rq[101]
    DIRECTION OUTPUT ;
    USE SIGNAL ;
    PORT
      LAYER M4 ;
        RECT  0 40.272 0.084 40.296 ;
    END
  END rq[101]
  PIN rq[102]
    DIRECTION OUTPUT ;
    USE SIGNAL ;
    PORT
      LAYER M4 ;
        RECT  0 40.368 0.084 40.392 ;
    END
  END rq[102]
  PIN rq[103]
    DIRECTION OUTPUT ;
    USE SIGNAL ;
    PORT
      LAYER M4 ;
        RECT  0 40.464 0.084 40.488 ;
    END
  END rq[103]
  PIN rq[104]
    DIRECTION OUTPUT ;
    USE SIGNAL ;
    PORT
      LAYER M4 ;
        RECT  0 40.56 0.084 40.584 ;
    END
  END rq[104]
  PIN rq[105]
    DIRECTION OUTPUT ;
    USE SIGNAL ;
    PORT
      LAYER M4 ;
        RECT  0 40.656 0.084 40.68 ;
    END
  END rq[105]
  PIN rq[106]
    DIRECTION OUTPUT ;
    USE SIGNAL ;
    PORT
      LAYER M4 ;
        RECT  0 40.752 0.084 40.776 ;
    END
  END rq[106]
  PIN rq[107]
    DIRECTION OUTPUT ;
    USE SIGNAL ;
    PORT
      LAYER M4 ;
        RECT  0 40.848 0.084 40.872 ;
    END
  END rq[107]
  PIN rq[108]
    DIRECTION OUTPUT ;
    USE SIGNAL ;
    PORT
      LAYER M4 ;
        RECT  0 40.944 0.084 40.968 ;
    END
  END rq[108]
  PIN rq[109]
    DIRECTION OUTPUT ;
    USE SIGNAL ;
    PORT
      LAYER M4 ;
        RECT  0 41.04 0.084 41.064 ;
    END
  END rq[109]
  PIN rq[10]
    DIRECTION OUTPUT ;
    USE SIGNAL ;
    PORT
      LAYER M4 ;
        RECT  0 37.68 0.084 37.704 ;
    END
  END rq[10]
  PIN rq[110]
    DIRECTION OUTPUT ;
    USE SIGNAL ;
    PORT
      LAYER M4 ;
        RECT  0 41.136 0.084 41.16 ;
    END
  END rq[110]
  PIN rq[111]
    DIRECTION OUTPUT ;
    USE SIGNAL ;
    PORT
      LAYER M4 ;
        RECT  0 41.232 0.084 41.256 ;
    END
  END rq[111]
  PIN rq[112]
    DIRECTION OUTPUT ;
    USE SIGNAL ;
    PORT
      LAYER M4 ;
        RECT  0 41.328 0.084 41.352 ;
    END
  END rq[112]
  PIN rq[113]
    DIRECTION OUTPUT ;
    USE SIGNAL ;
    PORT
      LAYER M4 ;
        RECT  0 41.424 0.084 41.448 ;
    END
  END rq[113]
  PIN rq[114]
    DIRECTION OUTPUT ;
    USE SIGNAL ;
    PORT
      LAYER M4 ;
        RECT  0 41.52 0.084 41.544 ;
    END
  END rq[114]
  PIN rq[115]
    DIRECTION OUTPUT ;
    USE SIGNAL ;
    PORT
      LAYER M4 ;
        RECT  0 41.616 0.084 41.64 ;
    END
  END rq[115]
  PIN rq[116]
    DIRECTION OUTPUT ;
    USE SIGNAL ;
    PORT
      LAYER M4 ;
        RECT  0 41.712 0.084 41.736 ;
    END
  END rq[116]
  PIN rq[117]
    DIRECTION OUTPUT ;
    USE SIGNAL ;
    PORT
      LAYER M4 ;
        RECT  0 41.808 0.084 41.832 ;
    END
  END rq[117]
  PIN rq[118]
    DIRECTION OUTPUT ;
    USE SIGNAL ;
    PORT
      LAYER M4 ;
        RECT  0 41.904 0.084 41.928 ;
    END
  END rq[118]
  PIN rq[119]
    DIRECTION OUTPUT ;
    USE SIGNAL ;
    PORT
      LAYER M4 ;
        RECT  0 42 0.084 42.024 ;
    END
  END rq[119]
  PIN rq[11]
    DIRECTION OUTPUT ;
    USE SIGNAL ;
    PORT
      LAYER M4 ;
        RECT  0 37.776 0.084 37.8 ;
    END
  END rq[11]
  PIN rq[120]
    DIRECTION OUTPUT ;
    USE SIGNAL ;
    PORT
      LAYER M4 ;
        RECT  0 42.096 0.084 42.12 ;
    END
  END rq[120]
  PIN rq[121]
    DIRECTION OUTPUT ;
    USE SIGNAL ;
    PORT
      LAYER M4 ;
        RECT  0 42.192 0.084 42.216 ;
    END
  END rq[121]
  PIN rq[122]
    DIRECTION OUTPUT ;
    USE SIGNAL ;
    PORT
      LAYER M4 ;
        RECT  0 42.288 0.084 42.312 ;
    END
  END rq[122]
  PIN rq[123]
    DIRECTION OUTPUT ;
    USE SIGNAL ;
    PORT
      LAYER M4 ;
        RECT  0 42.384 0.084 42.408 ;
    END
  END rq[123]
  PIN rq[124]
    DIRECTION OUTPUT ;
    USE SIGNAL ;
    PORT
      LAYER M4 ;
        RECT  0 42.48 0.084 42.504 ;
    END
  END rq[124]
  PIN rq[125]
    DIRECTION OUTPUT ;
    USE SIGNAL ;
    PORT
      LAYER M4 ;
        RECT  0 42.576 0.084 42.6 ;
    END
  END rq[125]
  PIN rq[126]
    DIRECTION OUTPUT ;
    USE SIGNAL ;
    PORT
      LAYER M4 ;
        RECT  0 42.672 0.084 42.696 ;
    END
  END rq[126]
  PIN rq[127]
    DIRECTION OUTPUT ;
    USE SIGNAL ;
    PORT
      LAYER M4 ;
        RECT  0 42.768 0.084 42.792 ;
    END
  END rq[127]
  PIN rq[128]
    DIRECTION OUTPUT ;
    USE SIGNAL ;
    PORT
      LAYER M4 ;
        RECT  0 42.864 0.084 42.888 ;
    END
  END rq[128]
  PIN rq[129]
    DIRECTION OUTPUT ;
    USE SIGNAL ;
    PORT
      LAYER M4 ;
        RECT  0 42.96 0.084 42.984 ;
    END
  END rq[129]
  PIN rq[12]
    DIRECTION OUTPUT ;
    USE SIGNAL ;
    PORT
      LAYER M4 ;
        RECT  0 37.872 0.084 37.896 ;
    END
  END rq[12]
  PIN rq[130]
    DIRECTION OUTPUT ;
    USE SIGNAL ;
    PORT
      LAYER M4 ;
        RECT  0 28.656 0.084 28.68 ;
    END
  END rq[130]
  PIN rq[131]
    DIRECTION OUTPUT ;
    USE SIGNAL ;
    PORT
      LAYER M4 ;
        RECT  0 28.752 0.084 28.776 ;
    END
  END rq[131]
  PIN rq[132]
    DIRECTION OUTPUT ;
    USE SIGNAL ;
    PORT
      LAYER M4 ;
        RECT  0 28.848 0.084 28.872 ;
    END
  END rq[132]
  PIN rq[133]
    DIRECTION OUTPUT ;
    USE SIGNAL ;
    PORT
      LAYER M4 ;
        RECT  0 28.944 0.084 28.968 ;
    END
  END rq[133]
  PIN rq[134]
    DIRECTION OUTPUT ;
    USE SIGNAL ;
    PORT
      LAYER M4 ;
        RECT  0 29.04 0.084 29.064 ;
    END
  END rq[134]
  PIN rq[135]
    DIRECTION OUTPUT ;
    USE SIGNAL ;
    PORT
      LAYER M4 ;
        RECT  0 29.136 0.084 29.16 ;
    END
  END rq[135]
  PIN rq[13]
    DIRECTION OUTPUT ;
    USE SIGNAL ;
    PORT
      LAYER M4 ;
        RECT  0 37.968 0.084 37.992 ;
    END
  END rq[13]
  PIN rq[14]
    DIRECTION OUTPUT ;
    USE SIGNAL ;
    PORT
      LAYER M4 ;
        RECT  0 38.064 0.084 38.088 ;
    END
  END rq[14]
  PIN rq[15]
    DIRECTION OUTPUT ;
    USE SIGNAL ;
    PORT
      LAYER M4 ;
        RECT  0 38.16 0.084 38.184 ;
    END
  END rq[15]
  PIN rq[16]
    DIRECTION OUTPUT ;
    USE SIGNAL ;
    PORT
      LAYER M4 ;
        RECT  0 38.256 0.084 38.28 ;
    END
  END rq[16]
  PIN rq[17]
    DIRECTION OUTPUT ;
    USE SIGNAL ;
    PORT
      LAYER M4 ;
        RECT  0 38.352 0.084 38.376 ;
    END
  END rq[17]
  PIN rq[18]
    DIRECTION OUTPUT ;
    USE SIGNAL ;
    PORT
      LAYER M4 ;
        RECT  0 38.448 0.084 38.472 ;
    END
  END rq[18]
  PIN rq[19]
    DIRECTION OUTPUT ;
    USE SIGNAL ;
    PORT
      LAYER M4 ;
        RECT  0 38.544 0.084 38.568 ;
    END
  END rq[19]
  PIN rq[1]
    DIRECTION OUTPUT ;
    USE SIGNAL ;
    PORT
      LAYER M4 ;
        RECT  0 33.744 0.084 33.768 ;
    END
  END rq[1]
  PIN rq[20]
    DIRECTION OUTPUT ;
    USE SIGNAL ;
    PORT
      LAYER M4 ;
        RECT  0 38.64 0.084 38.664 ;
    END
  END rq[20]
  PIN rq[21]
    DIRECTION OUTPUT ;
    USE SIGNAL ;
    PORT
      LAYER M4 ;
        RECT  0 38.736 0.084 38.76 ;
    END
  END rq[21]
  PIN rq[22]
    DIRECTION OUTPUT ;
    USE SIGNAL ;
    PORT
      LAYER M4 ;
        RECT  0 38.832 0.084 38.856 ;
    END
  END rq[22]
  PIN rq[23]
    DIRECTION OUTPUT ;
    USE SIGNAL ;
    PORT
      LAYER M4 ;
        RECT  0 38.928 0.084 38.952 ;
    END
  END rq[23]
  PIN rq[24]
    DIRECTION OUTPUT ;
    USE SIGNAL ;
    PORT
      LAYER M4 ;
        RECT  0 39.024 0.084 39.048 ;
    END
  END rq[24]
  PIN rq[25]
    DIRECTION OUTPUT ;
    USE SIGNAL ;
    PORT
      LAYER M4 ;
        RECT  0 39.12 0.084 39.144 ;
    END
  END rq[25]
  PIN rq[26]
    DIRECTION OUTPUT ;
    USE SIGNAL ;
    PORT
      LAYER M4 ;
        RECT  0 39.216 0.084 39.24 ;
    END
  END rq[26]
  PIN rq[27]
    DIRECTION OUTPUT ;
    USE SIGNAL ;
    PORT
      LAYER M4 ;
        RECT  0 39.312 0.084 39.336 ;
    END
  END rq[27]
  PIN rq[28]
    DIRECTION OUTPUT ;
    USE SIGNAL ;
    PORT
      LAYER M4 ;
        RECT  0 39.408 0.084 39.432 ;
    END
  END rq[28]
  PIN rq[29]
    DIRECTION OUTPUT ;
    USE SIGNAL ;
    PORT
      LAYER M4 ;
        RECT  0 39.504 0.084 39.528 ;
    END
  END rq[29]
  PIN rq[2]
    DIRECTION OUTPUT ;
    USE SIGNAL ;
    PORT
      LAYER M4 ;
        RECT  0 36.912 0.084 36.936 ;
    END
  END rq[2]
  PIN rq[30]
    DIRECTION OUTPUT ;
    USE SIGNAL ;
    PORT
      LAYER M4 ;
        RECT  0 39.6 0.084 39.624 ;
    END
  END rq[30]
  PIN rq[31]
    DIRECTION OUTPUT ;
    USE SIGNAL ;
    PORT
      LAYER M4 ;
        RECT  0 39.696 0.084 39.72 ;
    END
  END rq[31]
  PIN rq[32]
    DIRECTION OUTPUT ;
    USE SIGNAL ;
    PORT
      LAYER M4 ;
        RECT  0 39.792 0.084 39.816 ;
    END
  END rq[32]
  PIN rq[33]
    DIRECTION OUTPUT ;
    USE SIGNAL ;
    PORT
      LAYER M4 ;
        RECT  0 39.888 0.084 39.912 ;
    END
  END rq[33]
  PIN rq[34]
    DIRECTION OUTPUT ;
    USE SIGNAL ;
    PORT
      LAYER M4 ;
        RECT  0 43.056 0.084 43.08 ;
    END
  END rq[34]
  PIN rq[35]
    DIRECTION OUTPUT ;
    USE SIGNAL ;
    PORT
      LAYER M4 ;
        RECT  0 43.152 0.084 43.176 ;
    END
  END rq[35]
  PIN rq[36]
    DIRECTION OUTPUT ;
    USE SIGNAL ;
    PORT
      LAYER M4 ;
        RECT  0 43.248 0.084 43.272 ;
    END
  END rq[36]
  PIN rq[37]
    DIRECTION OUTPUT ;
    USE SIGNAL ;
    PORT
      LAYER M4 ;
        RECT  0 43.344 0.084 43.368 ;
    END
  END rq[37]
  PIN rq[38]
    DIRECTION OUTPUT ;
    USE SIGNAL ;
    PORT
      LAYER M4 ;
        RECT  0 43.44 0.084 43.464 ;
    END
  END rq[38]
  PIN rq[39]
    DIRECTION OUTPUT ;
    USE SIGNAL ;
    PORT
      LAYER M4 ;
        RECT  0 43.536 0.084 43.56 ;
    END
  END rq[39]
  PIN rq[3]
    DIRECTION OUTPUT ;
    USE SIGNAL ;
    PORT
      LAYER M4 ;
        RECT  0 37.008 0.084 37.032 ;
    END
  END rq[3]
  PIN rq[40]
    DIRECTION OUTPUT ;
    USE SIGNAL ;
    PORT
      LAYER M4 ;
        RECT  0 43.632 0.084 43.656 ;
    END
  END rq[40]
  PIN rq[41]
    DIRECTION OUTPUT ;
    USE SIGNAL ;
    PORT
      LAYER M4 ;
        RECT  0 43.728 0.084 43.752 ;
    END
  END rq[41]
  PIN rq[42]
    DIRECTION OUTPUT ;
    USE SIGNAL ;
    PORT
      LAYER M4 ;
        RECT  0 43.824 0.084 43.848 ;
    END
  END rq[42]
  PIN rq[43]
    DIRECTION OUTPUT ;
    USE SIGNAL ;
    PORT
      LAYER M4 ;
        RECT  0 43.92 0.084 43.944 ;
    END
  END rq[43]
  PIN rq[44]
    DIRECTION OUTPUT ;
    USE SIGNAL ;
    PORT
      LAYER M4 ;
        RECT  0 44.016 0.084 44.04 ;
    END
  END rq[44]
  PIN rq[45]
    DIRECTION OUTPUT ;
    USE SIGNAL ;
    PORT
      LAYER M4 ;
        RECT  0 44.112 0.084 44.136 ;
    END
  END rq[45]
  PIN rq[46]
    DIRECTION OUTPUT ;
    USE SIGNAL ;
    PORT
      LAYER M4 ;
        RECT  0 44.208 0.084 44.232 ;
    END
  END rq[46]
  PIN rq[47]
    DIRECTION OUTPUT ;
    USE SIGNAL ;
    PORT
      LAYER M4 ;
        RECT  0 44.304 0.084 44.328 ;
    END
  END rq[47]
  PIN rq[48]
    DIRECTION OUTPUT ;
    USE SIGNAL ;
    PORT
      LAYER M4 ;
        RECT  0 44.4 0.084 44.424 ;
    END
  END rq[48]
  PIN rq[49]
    DIRECTION OUTPUT ;
    USE SIGNAL ;
    PORT
      LAYER M4 ;
        RECT  0 44.496 0.084 44.52 ;
    END
  END rq[49]
  PIN rq[4]
    DIRECTION OUTPUT ;
    USE SIGNAL ;
    PORT
      LAYER M4 ;
        RECT  0 37.104 0.084 37.128 ;
    END
  END rq[4]
  PIN rq[50]
    DIRECTION OUTPUT ;
    USE SIGNAL ;
    PORT
      LAYER M4 ;
        RECT  0 44.592 0.084 44.616 ;
    END
  END rq[50]
  PIN rq[51]
    DIRECTION OUTPUT ;
    USE SIGNAL ;
    PORT
      LAYER M4 ;
        RECT  0 44.688 0.084 44.712 ;
    END
  END rq[51]
  PIN rq[52]
    DIRECTION OUTPUT ;
    USE SIGNAL ;
    PORT
      LAYER M4 ;
        RECT  0 44.784 0.084 44.808 ;
    END
  END rq[52]
  PIN rq[53]
    DIRECTION OUTPUT ;
    USE SIGNAL ;
    PORT
      LAYER M4 ;
        RECT  0 44.88 0.084 44.904 ;
    END
  END rq[53]
  PIN rq[54]
    DIRECTION OUTPUT ;
    USE SIGNAL ;
    PORT
      LAYER M4 ;
        RECT  0 44.976 0.084 45 ;
    END
  END rq[54]
  PIN rq[55]
    DIRECTION OUTPUT ;
    USE SIGNAL ;
    PORT
      LAYER M4 ;
        RECT  0 45.072 0.084 45.096 ;
    END
  END rq[55]
  PIN rq[56]
    DIRECTION OUTPUT ;
    USE SIGNAL ;
    PORT
      LAYER M4 ;
        RECT  0 45.168 0.084 45.192 ;
    END
  END rq[56]
  PIN rq[57]
    DIRECTION OUTPUT ;
    USE SIGNAL ;
    PORT
      LAYER M4 ;
        RECT  0 45.264 0.084 45.288 ;
    END
  END rq[57]
  PIN rq[58]
    DIRECTION OUTPUT ;
    USE SIGNAL ;
    PORT
      LAYER M4 ;
        RECT  0 45.36 0.084 45.384 ;
    END
  END rq[58]
  PIN rq[59]
    DIRECTION OUTPUT ;
    USE SIGNAL ;
    PORT
      LAYER M4 ;
        RECT  0 45.456 0.084 45.48 ;
    END
  END rq[59]
  PIN rq[5]
    DIRECTION OUTPUT ;
    USE SIGNAL ;
    PORT
      LAYER M4 ;
        RECT  0 37.2 0.084 37.224 ;
    END
  END rq[5]
  PIN rq[60]
    DIRECTION OUTPUT ;
    USE SIGNAL ;
    PORT
      LAYER M4 ;
        RECT  0 45.552 0.084 45.576 ;
    END
  END rq[60]
  PIN rq[61]
    DIRECTION OUTPUT ;
    USE SIGNAL ;
    PORT
      LAYER M4 ;
        RECT  0 45.648 0.084 45.672 ;
    END
  END rq[61]
  PIN rq[62]
    DIRECTION OUTPUT ;
    USE SIGNAL ;
    PORT
      LAYER M4 ;
        RECT  0 45.744 0.084 45.768 ;
    END
  END rq[62]
  PIN rq[63]
    DIRECTION OUTPUT ;
    USE SIGNAL ;
    PORT
      LAYER M4 ;
        RECT  0 45.84 0.084 45.864 ;
    END
  END rq[63]
  PIN rq[64]
    DIRECTION OUTPUT ;
    USE SIGNAL ;
    PORT
      LAYER M4 ;
        RECT  0 45.936 0.084 45.96 ;
    END
  END rq[64]
  PIN rq[65]
    DIRECTION OUTPUT ;
    USE SIGNAL ;
    PORT
      LAYER M4 ;
        RECT  0 46.032 0.084 46.056 ;
    END
  END rq[65]
  PIN rq[66]
    DIRECTION OUTPUT ;
    USE SIGNAL ;
    PORT
      LAYER M4 ;
        RECT  0 33.84 0.084 33.864 ;
    END
  END rq[66]
  PIN rq[67]
    DIRECTION OUTPUT ;
    USE SIGNAL ;
    PORT
      LAYER M4 ;
        RECT  0 33.936 0.084 33.96 ;
    END
  END rq[67]
  PIN rq[68]
    DIRECTION OUTPUT ;
    USE SIGNAL ;
    PORT
      LAYER M4 ;
        RECT  0 34.032 0.084 34.056 ;
    END
  END rq[68]
  PIN rq[69]
    DIRECTION OUTPUT ;
    USE SIGNAL ;
    PORT
      LAYER M4 ;
        RECT  0 34.128 0.084 34.152 ;
    END
  END rq[69]
  PIN rq[6]
    DIRECTION OUTPUT ;
    USE SIGNAL ;
    PORT
      LAYER M4 ;
        RECT  0 37.296 0.084 37.32 ;
    END
  END rq[6]
  PIN rq[70]
    DIRECTION OUTPUT ;
    USE SIGNAL ;
    PORT
      LAYER M4 ;
        RECT  0 34.224 0.084 34.248 ;
    END
  END rq[70]
  PIN rq[71]
    DIRECTION OUTPUT ;
    USE SIGNAL ;
    PORT
      LAYER M4 ;
        RECT  0 34.32 0.084 34.344 ;
    END
  END rq[71]
  PIN rq[72]
    DIRECTION OUTPUT ;
    USE SIGNAL ;
    PORT
      LAYER M4 ;
        RECT  0 34.416 0.084 34.44 ;
    END
  END rq[72]
  PIN rq[73]
    DIRECTION OUTPUT ;
    USE SIGNAL ;
    PORT
      LAYER M4 ;
        RECT  0 34.512 0.084 34.536 ;
    END
  END rq[73]
  PIN rq[74]
    DIRECTION OUTPUT ;
    USE SIGNAL ;
    PORT
      LAYER M4 ;
        RECT  0 34.608 0.084 34.632 ;
    END
  END rq[74]
  PIN rq[75]
    DIRECTION OUTPUT ;
    USE SIGNAL ;
    PORT
      LAYER M4 ;
        RECT  0 34.704 0.084 34.728 ;
    END
  END rq[75]
  PIN rq[76]
    DIRECTION OUTPUT ;
    USE SIGNAL ;
    PORT
      LAYER M4 ;
        RECT  0 34.8 0.084 34.824 ;
    END
  END rq[76]
  PIN rq[77]
    DIRECTION OUTPUT ;
    USE SIGNAL ;
    PORT
      LAYER M4 ;
        RECT  0 34.896 0.084 34.92 ;
    END
  END rq[77]
  PIN rq[78]
    DIRECTION OUTPUT ;
    USE SIGNAL ;
    PORT
      LAYER M4 ;
        RECT  0 34.992 0.084 35.016 ;
    END
  END rq[78]
  PIN rq[79]
    DIRECTION OUTPUT ;
    USE SIGNAL ;
    PORT
      LAYER M4 ;
        RECT  0 35.088 0.084 35.112 ;
    END
  END rq[79]
  PIN rq[7]
    DIRECTION OUTPUT ;
    USE SIGNAL ;
    PORT
      LAYER M4 ;
        RECT  0 37.392 0.084 37.416 ;
    END
  END rq[7]
  PIN rq[80]
    DIRECTION OUTPUT ;
    USE SIGNAL ;
    PORT
      LAYER M4 ;
        RECT  0 35.184 0.084 35.208 ;
    END
  END rq[80]
  PIN rq[81]
    DIRECTION OUTPUT ;
    USE SIGNAL ;
    PORT
      LAYER M4 ;
        RECT  0 35.28 0.084 35.304 ;
    END
  END rq[81]
  PIN rq[82]
    DIRECTION OUTPUT ;
    USE SIGNAL ;
    PORT
      LAYER M4 ;
        RECT  0 35.376 0.084 35.4 ;
    END
  END rq[82]
  PIN rq[83]
    DIRECTION OUTPUT ;
    USE SIGNAL ;
    PORT
      LAYER M4 ;
        RECT  0 35.472 0.084 35.496 ;
    END
  END rq[83]
  PIN rq[84]
    DIRECTION OUTPUT ;
    USE SIGNAL ;
    PORT
      LAYER M4 ;
        RECT  0 35.568 0.084 35.592 ;
    END
  END rq[84]
  PIN rq[85]
    DIRECTION OUTPUT ;
    USE SIGNAL ;
    PORT
      LAYER M4 ;
        RECT  0 35.664 0.084 35.688 ;
    END
  END rq[85]
  PIN rq[86]
    DIRECTION OUTPUT ;
    USE SIGNAL ;
    PORT
      LAYER M4 ;
        RECT  0 35.76 0.084 35.784 ;
    END
  END rq[86]
  PIN rq[87]
    DIRECTION OUTPUT ;
    USE SIGNAL ;
    PORT
      LAYER M4 ;
        RECT  0 35.856 0.084 35.88 ;
    END
  END rq[87]
  PIN rq[88]
    DIRECTION OUTPUT ;
    USE SIGNAL ;
    PORT
      LAYER M4 ;
        RECT  0 35.952 0.084 35.976 ;
    END
  END rq[88]
  PIN rq[89]
    DIRECTION OUTPUT ;
    USE SIGNAL ;
    PORT
      LAYER M4 ;
        RECT  0 36.048 0.084 36.072 ;
    END
  END rq[89]
  PIN rq[8]
    DIRECTION OUTPUT ;
    USE SIGNAL ;
    PORT
      LAYER M4 ;
        RECT  0 37.488 0.084 37.512 ;
    END
  END rq[8]
  PIN rq[90]
    DIRECTION OUTPUT ;
    USE SIGNAL ;
    PORT
      LAYER M4 ;
        RECT  0 36.144 0.084 36.168 ;
    END
  END rq[90]
  PIN rq[91]
    DIRECTION OUTPUT ;
    USE SIGNAL ;
    PORT
      LAYER M4 ;
        RECT  0 36.24 0.084 36.264 ;
    END
  END rq[91]
  PIN rq[92]
    DIRECTION OUTPUT ;
    USE SIGNAL ;
    PORT
      LAYER M4 ;
        RECT  0 36.336 0.084 36.36 ;
    END
  END rq[92]
  PIN rq[93]
    DIRECTION OUTPUT ;
    USE SIGNAL ;
    PORT
      LAYER M4 ;
        RECT  0 36.432 0.084 36.456 ;
    END
  END rq[93]
  PIN rq[94]
    DIRECTION OUTPUT ;
    USE SIGNAL ;
    PORT
      LAYER M4 ;
        RECT  0 36.528 0.084 36.552 ;
    END
  END rq[94]
  PIN rq[95]
    DIRECTION OUTPUT ;
    USE SIGNAL ;
    PORT
      LAYER M4 ;
        RECT  0 36.624 0.084 36.648 ;
    END
  END rq[95]
  PIN rq[96]
    DIRECTION OUTPUT ;
    USE SIGNAL ;
    PORT
      LAYER M4 ;
        RECT  0 36.72 0.084 36.744 ;
    END
  END rq[96]
  PIN rq[97]
    DIRECTION OUTPUT ;
    USE SIGNAL ;
    PORT
      LAYER M4 ;
        RECT  0 36.816 0.084 36.84 ;
    END
  END rq[97]
  PIN rq[98]
    DIRECTION OUTPUT ;
    USE SIGNAL ;
    PORT
      LAYER M4 ;
        RECT  0 39.984 0.084 40.008 ;
    END
  END rq[98]
  PIN rq[99]
    DIRECTION OUTPUT ;
    USE SIGNAL ;
    PORT
      LAYER M4 ;
        RECT  0 40.08 0.084 40.104 ;
    END
  END rq[99]
  PIN rq[9]
    DIRECTION OUTPUT ;
    USE SIGNAL ;
    PORT
      LAYER M4 ;
        RECT  0 37.584 0.084 37.608 ;
    END
  END rq[9]
  PIN rr_valid_i[0]
    DIRECTION INPUT ;
    USE SIGNAL ;
    PORT
      LAYER M4 ;
        RECT  0 29.232 0.084 29.256 ;
    END
  END rr_valid_i[0]
  PIN rr_valid_i[1]
    DIRECTION INPUT ;
    USE SIGNAL ;
    PORT
      LAYER M4 ;
        RECT  0 29.328 0.084 29.352 ;
    END
  END rr_valid_i[1]
  PIN rr_valid_i[2]
    DIRECTION INPUT ;
    USE SIGNAL ;
    PORT
      LAYER M4 ;
        RECT  0 29.424 0.084 29.448 ;
    END
  END rr_valid_i[2]
  PIN rr_valid_i[3]
    DIRECTION INPUT ;
    USE SIGNAL ;
    PORT
      LAYER M4 ;
        RECT  0 29.52 0.084 29.544 ;
    END
  END rr_valid_i[3]
  PIN rr_valid_i[4]
    DIRECTION INPUT ;
    USE SIGNAL ;
    PORT
      LAYER M4 ;
        RECT  0 29.616 0.084 29.64 ;
    END
  END rr_valid_i[4]
  PIN rr_valid_i[5]
    DIRECTION INPUT ;
    USE SIGNAL ;
    PORT
      LAYER M4 ;
        RECT  0 29.712 0.084 29.736 ;
    END
  END rr_valid_i[5]
  PIN rr_valid_i[6]
    DIRECTION INPUT ;
    USE SIGNAL ;
    PORT
      LAYER M4 ;
        RECT  0 29.808 0.084 29.832 ;
    END
  END rr_valid_i[6]
  PIN rr_valid_i[7]
    DIRECTION INPUT ;
    USE SIGNAL ;
    PORT
      LAYER M4 ;
        RECT  0 29.904 0.084 29.928 ;
    END
  END rr_valid_i[7]
  PIN rst_n
    DIRECTION INPUT ;
    USE SIGNAL ;
    PORT
      LAYER M4 ;
        RECT  69.036 12.528 69.12 12.552 ;
    END
  END rst_n
  PIN stk[0]
    DIRECTION INPUT ;
    USE SIGNAL ;
    PORT
      LAYER M4 ;
        RECT  69.036 12.624 69.12 12.648 ;
    END
  END stk[0]
  PIN stk[1]
    DIRECTION INPUT ;
    USE SIGNAL ;
    PORT
      LAYER M4 ;
        RECT  69.036 12.72 69.12 12.744 ;
    END
  END stk[1]
  PIN wa[0]
    DIRECTION INPUT ;
    USE SIGNAL ;
    PORT
      LAYER M5 ;
        RECT  54.384 69.036 54.408 69.12 ;
    END
  END wa[0]
  PIN wa[10]
    DIRECTION INPUT ;
    USE SIGNAL ;
    PORT
      LAYER M5 ;
        RECT  55.344 69.036 55.368 69.12 ;
    END
  END wa[10]
  PIN wa[11]
    DIRECTION INPUT ;
    USE SIGNAL ;
    PORT
      LAYER M5 ;
        RECT  55.44 69.036 55.464 69.12 ;
    END
  END wa[11]
  PIN wa[1]
    DIRECTION INPUT ;
    USE SIGNAL ;
    PORT
      LAYER M5 ;
        RECT  54.48 69.036 54.504 69.12 ;
    END
  END wa[1]
  PIN wa[2]
    DIRECTION INPUT ;
    USE SIGNAL ;
    PORT
      LAYER M5 ;
        RECT  54.576 69.036 54.6 69.12 ;
    END
  END wa[2]
  PIN wa[3]
    DIRECTION INPUT ;
    USE SIGNAL ;
    PORT
      LAYER M5 ;
        RECT  54.672 69.036 54.696 69.12 ;
    END
  END wa[3]
  PIN wa[4]
    DIRECTION INPUT ;
    USE SIGNAL ;
    PORT
      LAYER M5 ;
        RECT  54.768 69.036 54.792 69.12 ;
    END
  END wa[4]
  PIN wa[5]
    DIRECTION INPUT ;
    USE SIGNAL ;
    PORT
      LAYER M5 ;
        RECT  54.864 69.036 54.888 69.12 ;
    END
  END wa[5]
  PIN wa[6]
    DIRECTION INPUT ;
    USE SIGNAL ;
    PORT
      LAYER M5 ;
        RECT  54.96 69.036 54.984 69.12 ;
    END
  END wa[6]
  PIN wa[7]
    DIRECTION INPUT ;
    USE SIGNAL ;
    PORT
      LAYER M5 ;
        RECT  55.056 69.036 55.08 69.12 ;
    END
  END wa[7]
  PIN wa[8]
    DIRECTION INPUT ;
    USE SIGNAL ;
    PORT
      LAYER M5 ;
        RECT  55.152 69.036 55.176 69.12 ;
    END
  END wa[8]
  PIN wa[9]
    DIRECTION INPUT ;
    USE SIGNAL ;
    PORT
      LAYER M5 ;
        RECT  55.248 69.036 55.272 69.12 ;
    END
  END wa[9]
  PIN wb_fill_bank
    DIRECTION OUTPUT ;
    USE SIGNAL ;
    PORT
      LAYER M5 ;
        RECT  55.536 69.036 55.56 69.12 ;
    END
  END wb_fill_bank
  PIN wb_fill_epoch[0]
    DIRECTION OUTPUT ;
    USE SIGNAL ;
    PORT
      LAYER M5 ;
        RECT  55.632 69.036 55.656 69.12 ;
    END
  END wb_fill_epoch[0]
  PIN wb_fill_epoch[10]
    DIRECTION OUTPUT ;
    USE SIGNAL ;
    PORT
      LAYER M5 ;
        RECT  50.448 69.036 50.472 69.12 ;
    END
  END wb_fill_epoch[10]
  PIN wb_fill_epoch[11]
    DIRECTION OUTPUT ;
    USE SIGNAL ;
    PORT
      LAYER M5 ;
        RECT  50.544 69.036 50.568 69.12 ;
    END
  END wb_fill_epoch[11]
  PIN wb_fill_epoch[12]
    DIRECTION OUTPUT ;
    USE SIGNAL ;
    PORT
      LAYER M5 ;
        RECT  50.64 69.036 50.664 69.12 ;
    END
  END wb_fill_epoch[12]
  PIN wb_fill_epoch[13]
    DIRECTION OUTPUT ;
    USE SIGNAL ;
    PORT
      LAYER M5 ;
        RECT  50.736 69.036 50.76 69.12 ;
    END
  END wb_fill_epoch[13]
  PIN wb_fill_epoch[14]
    DIRECTION OUTPUT ;
    USE SIGNAL ;
    PORT
      LAYER M5 ;
        RECT  50.832 69.036 50.856 69.12 ;
    END
  END wb_fill_epoch[14]
  PIN wb_fill_epoch[15]
    DIRECTION OUTPUT ;
    USE SIGNAL ;
    PORT
      LAYER M5 ;
        RECT  50.928 69.036 50.952 69.12 ;
    END
  END wb_fill_epoch[15]
  PIN wb_fill_epoch[1]
    DIRECTION OUTPUT ;
    USE SIGNAL ;
    PORT
      LAYER M5 ;
        RECT  55.728 69.036 55.752 69.12 ;
    END
  END wb_fill_epoch[1]
  PIN wb_fill_epoch[2]
    DIRECTION OUTPUT ;
    USE SIGNAL ;
    PORT
      LAYER M5 ;
        RECT  55.824 69.036 55.848 69.12 ;
    END
  END wb_fill_epoch[2]
  PIN wb_fill_epoch[3]
    DIRECTION OUTPUT ;
    USE SIGNAL ;
    PORT
      LAYER M5 ;
        RECT  55.92 69.036 55.944 69.12 ;
    END
  END wb_fill_epoch[3]
  PIN wb_fill_epoch[4]
    DIRECTION OUTPUT ;
    USE SIGNAL ;
    PORT
      LAYER M5 ;
        RECT  56.016 69.036 56.04 69.12 ;
    END
  END wb_fill_epoch[4]
  PIN wb_fill_epoch[5]
    DIRECTION OUTPUT ;
    USE SIGNAL ;
    PORT
      LAYER M5 ;
        RECT  49.968 69.036 49.992 69.12 ;
    END
  END wb_fill_epoch[5]
  PIN wb_fill_epoch[6]
    DIRECTION OUTPUT ;
    USE SIGNAL ;
    PORT
      LAYER M5 ;
        RECT  50.064 69.036 50.088 69.12 ;
    END
  END wb_fill_epoch[6]
  PIN wb_fill_epoch[7]
    DIRECTION OUTPUT ;
    USE SIGNAL ;
    PORT
      LAYER M5 ;
        RECT  50.16 69.036 50.184 69.12 ;
    END
  END wb_fill_epoch[7]
  PIN wb_fill_epoch[8]
    DIRECTION OUTPUT ;
    USE SIGNAL ;
    PORT
      LAYER M5 ;
        RECT  50.256 69.036 50.28 69.12 ;
    END
  END wb_fill_epoch[8]
  PIN wb_fill_epoch[9]
    DIRECTION OUTPUT ;
    USE SIGNAL ;
    PORT
      LAYER M5 ;
        RECT  50.352 69.036 50.376 69.12 ;
    END
  END wb_fill_epoch[9]
  PIN wb_fill_start
    DIRECTION OUTPUT ;
    USE SIGNAL ;
    PORT
      LAYER M5 ;
        RECT  51.024 69.036 51.048 69.12 ;
    END
  END wb_fill_start
  PIN wb_ready
    DIRECTION INPUT ;
    USE SIGNAL ;
    PORT
      LAYER M5 ;
        RECT  51.12 69.036 51.144 69.12 ;
    END
  END wb_ready
  PIN wb_reserve_bank
    DIRECTION OUTPUT ;
    USE SIGNAL ;
    PORT
      LAYER M5 ;
        RECT  51.216 69.036 51.24 69.12 ;
    END
  END wb_reserve_bank
  PIN wb_reserve_base[0]
    DIRECTION OUTPUT ;
    USE SIGNAL ;
    PORT
      LAYER M5 ;
        RECT  51.312 69.036 51.336 69.12 ;
    END
  END wb_reserve_base[0]
  PIN wb_reserve_base[10]
    DIRECTION OUTPUT ;
    USE SIGNAL ;
    PORT
      LAYER M5 ;
        RECT  52.272 69.036 52.296 69.12 ;
    END
  END wb_reserve_base[10]
  PIN wb_reserve_base[11]
    DIRECTION OUTPUT ;
    USE SIGNAL ;
    PORT
      LAYER M5 ;
        RECT  52.368 69.036 52.392 69.12 ;
    END
  END wb_reserve_base[11]
  PIN wb_reserve_base[12]
    DIRECTION OUTPUT ;
    USE SIGNAL ;
    PORT
      LAYER M5 ;
        RECT  52.464 69.036 52.488 69.12 ;
    END
  END wb_reserve_base[12]
  PIN wb_reserve_base[13]
    DIRECTION OUTPUT ;
    USE SIGNAL ;
    PORT
      LAYER M5 ;
        RECT  52.56 69.036 52.584 69.12 ;
    END
  END wb_reserve_base[13]
  PIN wb_reserve_base[14]
    DIRECTION OUTPUT ;
    USE SIGNAL ;
    PORT
      LAYER M5 ;
        RECT  52.656 69.036 52.68 69.12 ;
    END
  END wb_reserve_base[14]
  PIN wb_reserve_base[15]
    DIRECTION OUTPUT ;
    USE SIGNAL ;
    PORT
      LAYER M5 ;
        RECT  52.752 69.036 52.776 69.12 ;
    END
  END wb_reserve_base[15]
  PIN wb_reserve_base[16]
    DIRECTION OUTPUT ;
    USE SIGNAL ;
    PORT
      LAYER M5 ;
        RECT  52.848 69.036 52.872 69.12 ;
    END
  END wb_reserve_base[16]
  PIN wb_reserve_base[17]
    DIRECTION OUTPUT ;
    USE SIGNAL ;
    PORT
      LAYER M5 ;
        RECT  52.944 69.036 52.968 69.12 ;
    END
  END wb_reserve_base[17]
  PIN wb_reserve_base[18]
    DIRECTION OUTPUT ;
    USE SIGNAL ;
    PORT
      LAYER M5 ;
        RECT  65.328 69.036 65.352 69.12 ;
    END
  END wb_reserve_base[18]
  PIN wb_reserve_base[19]
    DIRECTION OUTPUT ;
    USE SIGNAL ;
    PORT
      LAYER M5 ;
        RECT  65.424 69.036 65.448 69.12 ;
    END
  END wb_reserve_base[19]
  PIN wb_reserve_base[1]
    DIRECTION OUTPUT ;
    USE SIGNAL ;
    PORT
      LAYER M5 ;
        RECT  51.408 69.036 51.432 69.12 ;
    END
  END wb_reserve_base[1]
  PIN wb_reserve_base[20]
    DIRECTION OUTPUT ;
    USE SIGNAL ;
    PORT
      LAYER M5 ;
        RECT  65.52 69.036 65.544 69.12 ;
    END
  END wb_reserve_base[20]
  PIN wb_reserve_base[21]
    DIRECTION OUTPUT ;
    USE SIGNAL ;
    PORT
      LAYER M5 ;
        RECT  65.616 69.036 65.64 69.12 ;
    END
  END wb_reserve_base[21]
  PIN wb_reserve_base[22]
    DIRECTION OUTPUT ;
    USE SIGNAL ;
    PORT
      LAYER M5 ;
        RECT  65.712 69.036 65.736 69.12 ;
    END
  END wb_reserve_base[22]
  PIN wb_reserve_base[23]
    DIRECTION OUTPUT ;
    USE SIGNAL ;
    PORT
      LAYER M5 ;
        RECT  65.808 69.036 65.832 69.12 ;
    END
  END wb_reserve_base[23]
  PIN wb_reserve_base[24]
    DIRECTION OUTPUT ;
    USE SIGNAL ;
    PORT
      LAYER M5 ;
        RECT  65.904 69.036 65.928 69.12 ;
    END
  END wb_reserve_base[24]
  PIN wb_reserve_base[25]
    DIRECTION OUTPUT ;
    USE SIGNAL ;
    PORT
      LAYER M5 ;
        RECT  66 69.036 66.024 69.12 ;
    END
  END wb_reserve_base[25]
  PIN wb_reserve_base[26]
    DIRECTION OUTPUT ;
    USE SIGNAL ;
    PORT
      LAYER M5 ;
        RECT  66.096 69.036 66.12 69.12 ;
    END
  END wb_reserve_base[26]
  PIN wb_reserve_base[27]
    DIRECTION OUTPUT ;
    USE SIGNAL ;
    PORT
      LAYER M5 ;
        RECT  66.192 69.036 66.216 69.12 ;
    END
  END wb_reserve_base[27]
  PIN wb_reserve_base[28]
    DIRECTION OUTPUT ;
    USE SIGNAL ;
    PORT
      LAYER M5 ;
        RECT  66.288 69.036 66.312 69.12 ;
    END
  END wb_reserve_base[28]
  PIN wb_reserve_base[29]
    DIRECTION OUTPUT ;
    USE SIGNAL ;
    PORT
      LAYER M5 ;
        RECT  66.384 69.036 66.408 69.12 ;
    END
  END wb_reserve_base[29]
  PIN wb_reserve_base[2]
    DIRECTION OUTPUT ;
    USE SIGNAL ;
    PORT
      LAYER M5 ;
        RECT  51.504 69.036 51.528 69.12 ;
    END
  END wb_reserve_base[2]
  PIN wb_reserve_base[30]
    DIRECTION OUTPUT ;
    USE SIGNAL ;
    PORT
      LAYER M5 ;
        RECT  66.48 69.036 66.504 69.12 ;
    END
  END wb_reserve_base[30]
  PIN wb_reserve_base[31]
    DIRECTION OUTPUT ;
    USE SIGNAL ;
    PORT
      LAYER M5 ;
        RECT  66.576 69.036 66.6 69.12 ;
    END
  END wb_reserve_base[31]
  PIN wb_reserve_base[3]
    DIRECTION OUTPUT ;
    USE SIGNAL ;
    PORT
      LAYER M5 ;
        RECT  51.6 69.036 51.624 69.12 ;
    END
  END wb_reserve_base[3]
  PIN wb_reserve_base[4]
    DIRECTION OUTPUT ;
    USE SIGNAL ;
    PORT
      LAYER M5 ;
        RECT  51.696 69.036 51.72 69.12 ;
    END
  END wb_reserve_base[4]
  PIN wb_reserve_base[5]
    DIRECTION OUTPUT ;
    USE SIGNAL ;
    PORT
      LAYER M5 ;
        RECT  51.792 69.036 51.816 69.12 ;
    END
  END wb_reserve_base[5]
  PIN wb_reserve_base[6]
    DIRECTION OUTPUT ;
    USE SIGNAL ;
    PORT
      LAYER M5 ;
        RECT  51.888 69.036 51.912 69.12 ;
    END
  END wb_reserve_base[6]
  PIN wb_reserve_base[7]
    DIRECTION OUTPUT ;
    USE SIGNAL ;
    PORT
      LAYER M5 ;
        RECT  51.984 69.036 52.008 69.12 ;
    END
  END wb_reserve_base[7]
  PIN wb_reserve_base[8]
    DIRECTION OUTPUT ;
    USE SIGNAL ;
    PORT
      LAYER M5 ;
        RECT  52.08 69.036 52.104 69.12 ;
    END
  END wb_reserve_base[8]
  PIN wb_reserve_base[9]
    DIRECTION OUTPUT ;
    USE SIGNAL ;
    PORT
      LAYER M5 ;
        RECT  52.176 69.036 52.2 69.12 ;
    END
  END wb_reserve_base[9]
  PIN wb_reserve_epoch[0]
    DIRECTION OUTPUT ;
    USE SIGNAL ;
    PORT
      LAYER M5 ;
        RECT  66.672 69.036 66.696 69.12 ;
    END
  END wb_reserve_epoch[0]
  PIN wb_reserve_epoch[10]
    DIRECTION OUTPUT ;
    USE SIGNAL ;
    PORT
      LAYER M5 ;
        RECT  67.632 69.036 67.656 69.12 ;
    END
  END wb_reserve_epoch[10]
  PIN wb_reserve_epoch[11]
    DIRECTION OUTPUT ;
    USE SIGNAL ;
    PORT
      LAYER M5 ;
        RECT  67.728 69.036 67.752 69.12 ;
    END
  END wb_reserve_epoch[11]
  PIN wb_reserve_epoch[12]
    DIRECTION OUTPUT ;
    USE SIGNAL ;
    PORT
      LAYER M5 ;
        RECT  67.824 69.036 67.848 69.12 ;
    END
  END wb_reserve_epoch[12]
  PIN wb_reserve_epoch[13]
    DIRECTION OUTPUT ;
    USE SIGNAL ;
    PORT
      LAYER M5 ;
        RECT  67.92 69.036 67.944 69.12 ;
    END
  END wb_reserve_epoch[13]
  PIN wb_reserve_epoch[14]
    DIRECTION OUTPUT ;
    USE SIGNAL ;
    PORT
      LAYER M5 ;
        RECT  68.016 69.036 68.04 69.12 ;
    END
  END wb_reserve_epoch[14]
  PIN wb_reserve_epoch[15]
    DIRECTION OUTPUT ;
    USE SIGNAL ;
    PORT
      LAYER M5 ;
        RECT  68.112 69.036 68.136 69.12 ;
    END
  END wb_reserve_epoch[15]
  PIN wb_reserve_epoch[1]
    DIRECTION OUTPUT ;
    USE SIGNAL ;
    PORT
      LAYER M5 ;
        RECT  66.768 69.036 66.792 69.12 ;
    END
  END wb_reserve_epoch[1]
  PIN wb_reserve_epoch[2]
    DIRECTION OUTPUT ;
    USE SIGNAL ;
    PORT
      LAYER M5 ;
        RECT  66.864 69.036 66.888 69.12 ;
    END
  END wb_reserve_epoch[2]
  PIN wb_reserve_epoch[3]
    DIRECTION OUTPUT ;
    USE SIGNAL ;
    PORT
      LAYER M5 ;
        RECT  66.96 69.036 66.984 69.12 ;
    END
  END wb_reserve_epoch[3]
  PIN wb_reserve_epoch[4]
    DIRECTION OUTPUT ;
    USE SIGNAL ;
    PORT
      LAYER M5 ;
        RECT  67.056 69.036 67.08 69.12 ;
    END
  END wb_reserve_epoch[4]
  PIN wb_reserve_epoch[5]
    DIRECTION OUTPUT ;
    USE SIGNAL ;
    PORT
      LAYER M5 ;
        RECT  67.152 69.036 67.176 69.12 ;
    END
  END wb_reserve_epoch[5]
  PIN wb_reserve_epoch[6]
    DIRECTION OUTPUT ;
    USE SIGNAL ;
    PORT
      LAYER M5 ;
        RECT  67.248 69.036 67.272 69.12 ;
    END
  END wb_reserve_epoch[6]
  PIN wb_reserve_epoch[7]
    DIRECTION OUTPUT ;
    USE SIGNAL ;
    PORT
      LAYER M5 ;
        RECT  67.344 69.036 67.368 69.12 ;
    END
  END wb_reserve_epoch[7]
  PIN wb_reserve_epoch[8]
    DIRECTION OUTPUT ;
    USE SIGNAL ;
    PORT
      LAYER M5 ;
        RECT  67.44 69.036 67.464 69.12 ;
    END
  END wb_reserve_epoch[8]
  PIN wb_reserve_epoch[9]
    DIRECTION OUTPUT ;
    USE SIGNAL ;
    PORT
      LAYER M5 ;
        RECT  67.536 69.036 67.56 69.12 ;
    END
  END wb_reserve_epoch[9]
  PIN wb_reserve_sectors[0]
    DIRECTION OUTPUT ;
    USE SIGNAL ;
    PORT
      LAYER M5 ;
        RECT  68.208 69.036 68.232 69.12 ;
    END
  END wb_reserve_sectors[0]
  PIN wb_reserve_sectors[10]
    DIRECTION OUTPUT ;
    USE SIGNAL ;
    PORT
      LAYER M5 ;
        RECT  48.912 69.036 48.936 69.12 ;
    END
  END wb_reserve_sectors[10]
  PIN wb_reserve_sectors[11]
    DIRECTION OUTPUT ;
    USE SIGNAL ;
    PORT
      LAYER M5 ;
        RECT  49.008 69.036 49.032 69.12 ;
    END
  END wb_reserve_sectors[11]
  PIN wb_reserve_sectors[1]
    DIRECTION OUTPUT ;
    USE SIGNAL ;
    PORT
      LAYER M5 ;
        RECT  68.304 69.036 68.328 69.12 ;
    END
  END wb_reserve_sectors[1]
  PIN wb_reserve_sectors[2]
    DIRECTION OUTPUT ;
    USE SIGNAL ;
    PORT
      LAYER M5 ;
        RECT  48.144 69.036 48.168 69.12 ;
    END
  END wb_reserve_sectors[2]
  PIN wb_reserve_sectors[3]
    DIRECTION OUTPUT ;
    USE SIGNAL ;
    PORT
      LAYER M5 ;
        RECT  48.24 69.036 48.264 69.12 ;
    END
  END wb_reserve_sectors[3]
  PIN wb_reserve_sectors[4]
    DIRECTION OUTPUT ;
    USE SIGNAL ;
    PORT
      LAYER M5 ;
        RECT  48.336 69.036 48.36 69.12 ;
    END
  END wb_reserve_sectors[4]
  PIN wb_reserve_sectors[5]
    DIRECTION OUTPUT ;
    USE SIGNAL ;
    PORT
      LAYER M5 ;
        RECT  48.432 69.036 48.456 69.12 ;
    END
  END wb_reserve_sectors[5]
  PIN wb_reserve_sectors[6]
    DIRECTION OUTPUT ;
    USE SIGNAL ;
    PORT
      LAYER M5 ;
        RECT  48.528 69.036 48.552 69.12 ;
    END
  END wb_reserve_sectors[6]
  PIN wb_reserve_sectors[7]
    DIRECTION OUTPUT ;
    USE SIGNAL ;
    PORT
      LAYER M5 ;
        RECT  48.624 69.036 48.648 69.12 ;
    END
  END wb_reserve_sectors[7]
  PIN wb_reserve_sectors[8]
    DIRECTION OUTPUT ;
    USE SIGNAL ;
    PORT
      LAYER M5 ;
        RECT  48.72 69.036 48.744 69.12 ;
    END
  END wb_reserve_sectors[8]
  PIN wb_reserve_sectors[9]
    DIRECTION OUTPUT ;
    USE SIGNAL ;
    PORT
      LAYER M5 ;
        RECT  48.816 69.036 48.84 69.12 ;
    END
  END wb_reserve_sectors[9]
  PIN wb_reserve_v
    DIRECTION OUTPUT ;
    USE SIGNAL ;
    PORT
      LAYER M5 ;
        RECT  49.104 69.036 49.128 69.12 ;
    END
  END wb_reserve_v
  PIN VDD
    DIRECTION INOUT ;
    USE POWER ;
    PORT
      LAYER M5 ;
        RECT  61.992 2.151 62.112 66.969 ;
        RECT  56.592 2.151 56.712 66.969 ;
        RECT  51.192 2.151 51.312 66.969 ;
        RECT  45.792 2.151 45.912 66.969 ;
        RECT  40.392 2.151 40.512 66.969 ;
        RECT  34.992 2.151 35.112 66.969 ;
        RECT  29.592 2.151 29.712 66.969 ;
        RECT  24.192 2.151 24.312 66.969 ;
        RECT  18.792 2.151 18.912 66.969 ;
        RECT  13.392 2.151 13.512 66.969 ;
        RECT  7.992 2.151 8.112 66.969 ;
        RECT  2.592 2.151 2.712 66.969 ;
    END
  END VDD
  PIN VSS
    DIRECTION INOUT ;
    USE GROUND ;
    PORT
      LAYER M5 ;
        RECT  61.8 2.137 61.92 66.983 ;
        RECT  56.4 2.137 56.52 66.983 ;
        RECT  51 2.137 51.12 66.983 ;
        RECT  45.6 2.137 45.72 66.983 ;
        RECT  40.2 2.137 40.32 66.983 ;
        RECT  34.8 2.137 34.92 66.983 ;
        RECT  29.4 2.137 29.52 66.983 ;
        RECT  24 2.137 24.12 66.983 ;
        RECT  18.6 2.137 18.72 66.983 ;
        RECT  13.2 2.137 13.32 66.983 ;
        RECT  7.8 2.137 7.92 66.983 ;
        RECT  2.4 2.137 2.52 66.983 ;
    END
  END VSS
  OBS
    LAYER RVTN ;
     RECT  2.16 2.16 66.96 2.295 ;
     RECT  2.16 2.565 66.96 2.835 ;
     RECT  2.16 3.105 66.96 3.375 ;
     RECT  2.16 3.645 66.96 3.915 ;
     RECT  2.16 4.185 66.96 4.455 ;
     RECT  2.16 4.725 66.96 4.995 ;
     RECT  2.16 5.265 66.96 5.535 ;
     RECT  2.16 5.805 66.96 6.075 ;
     RECT  2.16 6.345 66.96 6.615 ;
     RECT  2.16 6.885 66.96 7.155 ;
     RECT  2.16 7.425 66.96 7.695 ;
     RECT  2.16 7.965 66.96 8.235 ;
     RECT  2.16 8.505 66.96 8.775 ;
     RECT  2.16 9.045 66.96 9.315 ;
     RECT  2.16 9.585 66.96 9.855 ;
     RECT  2.16 10.125 66.96 10.395 ;
     RECT  2.16 10.665 66.96 10.935 ;
     RECT  2.16 11.205 66.96 11.475 ;
     RECT  2.16 11.745 66.96 12.015 ;
     RECT  2.16 12.285 66.96 12.555 ;
     RECT  2.16 12.825 66.96 13.095 ;
     RECT  2.16 13.365 66.96 13.635 ;
     RECT  2.16 13.905 66.96 14.175 ;
     RECT  2.16 14.445 66.96 14.715 ;
     RECT  2.16 14.985 66.96 15.255 ;
     RECT  2.16 15.525 66.96 15.795 ;
     RECT  2.16 16.065 66.96 16.335 ;
     RECT  2.16 16.605 66.96 16.875 ;
     RECT  2.16 17.145 66.96 17.415 ;
     RECT  2.16 17.685 66.96 17.955 ;
     RECT  2.16 18.225 66.96 18.495 ;
     RECT  2.16 18.765 66.96 19.035 ;
     RECT  2.16 19.305 66.96 19.575 ;
     RECT  2.16 19.845 66.96 20.115 ;
     RECT  2.16 20.385 66.96 20.655 ;
     RECT  2.16 20.925 66.96 21.195 ;
     RECT  2.16 21.465 66.96 21.735 ;
     RECT  2.16 22.005 66.96 22.275 ;
     RECT  2.16 22.545 66.96 22.815 ;
     RECT  2.16 23.085 66.96 23.355 ;
     RECT  2.16 23.625 66.96 23.895 ;
     RECT  2.16 24.165 66.96 24.435 ;
     RECT  2.16 24.705 66.96 24.975 ;
     RECT  2.16 25.245 66.96 25.515 ;
     RECT  2.16 25.785 66.96 26.055 ;
     RECT  2.16 26.325 66.96 26.595 ;
     RECT  2.16 26.865 66.96 27.135 ;
     RECT  2.16 27.405 66.96 27.675 ;
     RECT  2.16 27.945 66.96 28.215 ;
     RECT  2.16 28.485 66.96 28.755 ;
     RECT  2.16 29.025 66.96 29.295 ;
     RECT  2.16 29.565 66.96 29.835 ;
     RECT  2.16 30.105 66.96 30.375 ;
     RECT  2.16 30.645 66.96 30.915 ;
     RECT  2.16 31.185 66.96 31.455 ;
     RECT  2.16 31.725 66.96 31.995 ;
     RECT  2.16 32.265 66.96 32.535 ;
     RECT  2.16 32.805 66.96 33.075 ;
     RECT  2.16 33.345 66.96 33.615 ;
     RECT  2.16 33.885 66.96 34.155 ;
     RECT  2.16 34.425 66.96 34.695 ;
     RECT  2.16 34.965 66.96 35.235 ;
     RECT  2.16 35.505 66.96 35.775 ;
     RECT  2.16 36.045 66.96 36.315 ;
     RECT  2.16 36.585 66.96 36.855 ;
     RECT  2.16 37.125 66.96 37.395 ;
     RECT  2.16 37.665 66.96 37.935 ;
     RECT  2.16 38.205 66.96 38.475 ;
     RECT  2.16 38.745 66.96 39.015 ;
     RECT  2.16 39.285 66.96 39.555 ;
     RECT  2.16 39.825 66.96 40.095 ;
     RECT  2.16 40.365 66.96 40.635 ;
     RECT  2.16 40.905 66.96 41.175 ;
     RECT  2.16 41.445 66.96 41.715 ;
     RECT  2.16 41.985 66.96 42.255 ;
     RECT  2.16 42.525 66.96 42.795 ;
     RECT  2.16 43.065 66.96 43.335 ;
     RECT  2.16 43.605 66.96 43.875 ;
     RECT  2.16 44.145 66.96 44.415 ;
     RECT  2.16 44.685 66.96 44.955 ;
     RECT  2.16 45.225 66.96 45.495 ;
     RECT  2.16 45.765 66.96 46.035 ;
     RECT  2.16 46.305 66.96 46.575 ;
     RECT  2.16 46.845 66.96 47.115 ;
     RECT  2.16 47.385 66.96 47.655 ;
     RECT  2.16 47.925 66.96 48.195 ;
     RECT  2.16 48.465 66.96 48.735 ;
     RECT  2.16 49.005 66.96 49.275 ;
     RECT  2.16 49.545 66.96 49.815 ;
     RECT  2.16 50.085 66.96 50.355 ;
     RECT  2.16 50.625 66.96 50.895 ;
     RECT  2.16 51.165 66.96 51.435 ;
     RECT  2.16 51.705 66.96 51.975 ;
     RECT  2.16 52.245 66.96 52.515 ;
     RECT  2.16 52.785 66.96 53.055 ;
     RECT  2.16 53.325 66.96 53.595 ;
     RECT  2.16 53.865 66.96 54.135 ;
     RECT  2.16 54.405 66.96 54.675 ;
     RECT  2.16 54.945 66.96 55.215 ;
     RECT  2.16 55.485 66.96 55.755 ;
     RECT  2.16 56.025 66.96 56.295 ;
     RECT  2.16 56.565 66.96 56.835 ;
     RECT  2.16 57.105 66.96 57.375 ;
     RECT  2.16 57.645 66.96 57.915 ;
     RECT  2.16 58.185 66.96 58.455 ;
     RECT  2.16 58.725 66.96 58.995 ;
     RECT  2.16 59.265 66.96 59.535 ;
     RECT  2.16 59.805 66.96 60.075 ;
     RECT  2.16 60.345 66.96 60.615 ;
     RECT  2.16 60.885 66.96 61.155 ;
     RECT  2.16 61.425 66.96 61.695 ;
     RECT  2.16 61.965 66.96 62.235 ;
     RECT  2.16 62.505 66.96 62.775 ;
     RECT  2.16 63.045 66.96 63.315 ;
     RECT  2.16 63.585 66.96 63.855 ;
     RECT  2.16 64.125 66.96 64.395 ;
     RECT  2.16 64.665 66.96 64.935 ;
     RECT  2.16 65.205 66.96 65.475 ;
     RECT  2.16 65.745 66.96 66.015 ;
     RECT  2.16 66.285 66.96 66.555 ;
     RECT  2.16 66.825 66.96 66.96 ;
    LAYER RVTP ;
     RECT  2.16 2.295 66.96 2.565 ;
     RECT  2.16 2.835 66.96 3.105 ;
     RECT  2.16 3.375 66.96 3.645 ;
     RECT  2.16 3.915 66.96 4.185 ;
     RECT  2.16 4.455 66.96 4.725 ;
     RECT  2.16 4.995 66.96 5.265 ;
     RECT  2.16 5.535 66.96 5.805 ;
     RECT  2.16 6.075 66.96 6.345 ;
     RECT  2.16 6.615 66.96 6.885 ;
     RECT  2.16 7.155 66.96 7.425 ;
     RECT  2.16 7.695 66.96 7.965 ;
     RECT  2.16 8.235 66.96 8.505 ;
     RECT  2.16 8.775 66.96 9.045 ;
     RECT  2.16 9.315 66.96 9.585 ;
     RECT  2.16 9.855 66.96 10.125 ;
     RECT  2.16 10.395 66.96 10.665 ;
     RECT  2.16 10.935 66.96 11.205 ;
     RECT  2.16 11.475 66.96 11.745 ;
     RECT  2.16 12.015 66.96 12.285 ;
     RECT  2.16 12.555 66.96 12.825 ;
     RECT  2.16 13.095 66.96 13.365 ;
     RECT  2.16 13.635 66.96 13.905 ;
     RECT  2.16 14.175 66.96 14.445 ;
     RECT  2.16 14.715 66.96 14.985 ;
     RECT  2.16 15.255 66.96 15.525 ;
     RECT  2.16 15.795 66.96 16.065 ;
     RECT  2.16 16.335 66.96 16.605 ;
     RECT  2.16 16.875 66.96 17.145 ;
     RECT  2.16 17.415 66.96 17.685 ;
     RECT  2.16 17.955 66.96 18.225 ;
     RECT  2.16 18.495 66.96 18.765 ;
     RECT  2.16 19.035 66.96 19.305 ;
     RECT  2.16 19.575 66.96 19.845 ;
     RECT  2.16 20.115 66.96 20.385 ;
     RECT  2.16 20.655 66.96 20.925 ;
     RECT  2.16 21.195 66.96 21.465 ;
     RECT  2.16 21.735 66.96 22.005 ;
     RECT  2.16 22.275 66.96 22.545 ;
     RECT  2.16 22.815 66.96 23.085 ;
     RECT  2.16 23.355 66.96 23.625 ;
     RECT  2.16 23.895 66.96 24.165 ;
     RECT  2.16 24.435 66.96 24.705 ;
     RECT  2.16 24.975 66.96 25.245 ;
     RECT  2.16 25.515 66.96 25.785 ;
     RECT  2.16 26.055 66.96 26.325 ;
     RECT  2.16 26.595 66.96 26.865 ;
     RECT  2.16 27.135 66.96 27.405 ;
     RECT  2.16 27.675 66.96 27.945 ;
     RECT  2.16 28.215 66.96 28.485 ;
     RECT  2.16 28.755 66.96 29.025 ;
     RECT  2.16 29.295 66.96 29.565 ;
     RECT  2.16 29.835 66.96 30.105 ;
     RECT  2.16 30.375 66.96 30.645 ;
     RECT  2.16 30.915 66.96 31.185 ;
     RECT  2.16 31.455 66.96 31.725 ;
     RECT  2.16 31.995 66.96 32.265 ;
     RECT  2.16 32.535 66.96 32.805 ;
     RECT  2.16 33.075 66.96 33.345 ;
     RECT  2.16 33.615 66.96 33.885 ;
     RECT  2.16 34.155 66.96 34.425 ;
     RECT  2.16 34.695 66.96 34.965 ;
     RECT  2.16 35.235 66.96 35.505 ;
     RECT  2.16 35.775 66.96 36.045 ;
     RECT  2.16 36.315 66.96 36.585 ;
     RECT  2.16 36.855 66.96 37.125 ;
     RECT  2.16 37.395 66.96 37.665 ;
     RECT  2.16 37.935 66.96 38.205 ;
     RECT  2.16 38.475 66.96 38.745 ;
     RECT  2.16 39.015 66.96 39.285 ;
     RECT  2.16 39.555 66.96 39.825 ;
     RECT  2.16 40.095 66.96 40.365 ;
     RECT  2.16 40.635 66.96 40.905 ;
     RECT  2.16 41.175 66.96 41.445 ;
     RECT  2.16 41.715 66.96 41.985 ;
     RECT  2.16 42.255 66.96 42.525 ;
     RECT  2.16 42.795 66.96 43.065 ;
     RECT  2.16 43.335 66.96 43.605 ;
     RECT  2.16 43.875 66.96 44.145 ;
     RECT  2.16 44.415 66.96 44.685 ;
     RECT  2.16 44.955 66.96 45.225 ;
     RECT  2.16 45.495 66.96 45.765 ;
     RECT  2.16 46.035 66.96 46.305 ;
     RECT  2.16 46.575 66.96 46.845 ;
     RECT  2.16 47.115 66.96 47.385 ;
     RECT  2.16 47.655 66.96 47.925 ;
     RECT  2.16 48.195 66.96 48.465 ;
     RECT  2.16 48.735 66.96 49.005 ;
     RECT  2.16 49.275 66.96 49.545 ;
     RECT  2.16 49.815 66.96 50.085 ;
     RECT  2.16 50.355 66.96 50.625 ;
     RECT  2.16 50.895 66.96 51.165 ;
     RECT  2.16 51.435 66.96 51.705 ;
     RECT  2.16 51.975 66.96 52.245 ;
     RECT  2.16 52.515 66.96 52.785 ;
     RECT  2.16 53.055 66.96 53.325 ;
     RECT  2.16 53.595 66.96 53.865 ;
     RECT  2.16 54.135 66.96 54.405 ;
     RECT  2.16 54.675 66.96 54.945 ;
     RECT  2.16 55.215 66.96 55.485 ;
     RECT  2.16 55.755 66.96 56.025 ;
     RECT  2.16 56.295 66.96 56.565 ;
     RECT  2.16 56.835 66.96 57.105 ;
     RECT  2.16 57.375 66.96 57.645 ;
     RECT  2.16 57.915 66.96 58.185 ;
     RECT  2.16 58.455 66.96 58.725 ;
     RECT  2.16 58.995 66.96 59.265 ;
     RECT  2.16 59.535 66.96 59.805 ;
     RECT  2.16 60.075 66.96 60.345 ;
     RECT  2.16 60.615 66.96 60.885 ;
     RECT  2.16 61.155 66.96 61.425 ;
     RECT  2.16 61.695 66.96 61.965 ;
     RECT  2.16 62.235 66.96 62.505 ;
     RECT  2.16 62.775 66.96 63.045 ;
     RECT  2.16 63.315 66.96 63.585 ;
     RECT  2.16 63.855 66.96 64.125 ;
     RECT  2.16 64.395 66.96 64.665 ;
     RECT  2.16 64.935 66.96 65.205 ;
     RECT  2.16 65.475 66.96 65.745 ;
     RECT  2.16 66.015 66.96 66.285 ;
     RECT  2.16 66.555 66.96 66.825 ;
    LAYER M1 ;
     RECT  2.16 2.151 66.96 66.969 ;
    LAYER M2 ;
     RECT  0.031 10.746 0.103 10.764 ;
     RECT  0.031 11.646 0.103 11.664 ;
     RECT  0.067 30.384 0.103 30.402 ;
     RECT  0.103 18.846 0.139 19.26 ;
     RECT  0.067 32.202 0.167 32.22 ;
     RECT  0.103 13.068 0.203 13.086 ;
     RECT  0.103 33.471 0.203 34.11 ;
     RECT  0.103 36.252 0.203 36.378 ;
     RECT  0.103 37.332 0.203 37.35 ;
     RECT  0.103 41.571 0.203 42.588 ;
     RECT  0.103 17.046 0.211 17.064 ;
     RECT  0.139 18.846 0.211 19.332 ;
     RECT  0.139 44.496 0.239 44.514 ;
     RECT  0.103 10.746 0.247 11.664 ;
     RECT  0.211 18.576 0.311 19.332 ;
     RECT  0.211 16.776 0.319 17.064 ;
     RECT  0.103 38.106 0.319 38.124 ;
     RECT  0.311 19.314 0.347 19.332 ;
     RECT  0.211 20.196 0.347 20.214 ;
     RECT  0.203 41.796 0.347 42.084 ;
     RECT  0.103 30.384 0.355 31.212 ;
     RECT  0.347 41.922 0.383 42.084 ;
     RECT  0.319 38.106 0.419 38.844 ;
     RECT  0.319 16.776 0.427 17.334 ;
     RECT  0.427 16.776 0.463 18.054 ;
     RECT  0.103 28.116 0.463 28.134 ;
     RECT  0.103 28.962 0.463 28.98 ;
     RECT  0.463 28.116 0.499 28.98 ;
     RECT  0.203 33.516 0.535 34.11 ;
     RECT  1.147 47.088 1.219 47.106 ;
     RECT  1.219 47.088 1.327 47.484 ;
     RECT  1.327 46.89 1.399 47.484 ;
     RECT  1.291 45.504 1.723 45.522 ;
     RECT  1.723 21.276 1.759 21.294 ;
     RECT  1.759 21.132 1.795 21.294 ;
     RECT  1.399 46.89 1.975 47.952 ;
     RECT  0.247 10.746 2.16 11.844 ;
     RECT  0.463 16.686 2.16 18.054 ;
     RECT  1.795 21.132 2.16 21.564 ;
     RECT  0.535 22.554 2.16 22.572 ;
     RECT  0.499 27.648 2.16 28.98 ;
     RECT  0.355 30.384 2.16 31.284 ;
     RECT  0.535 32.346 2.16 32.364 ;
     RECT  0.535 33.516 2.16 34.488 ;
     RECT  0.203 36.36 2.16 36.378 ;
     RECT  0.419 38.106 2.16 38.124 ;
     RECT  0.103 40.41 2.16 40.428 ;
     RECT  0.383 42.066 2.16 42.084 ;
     RECT  1.723 45.036 2.16 45.522 ;
     RECT  1.975 46.89 2.16 48.384 ;
     RECT  2.16 2.151 14.215 66.969 ;
     RECT  14.215 2.151 17.347 67.014 ;
     RECT  17.347 2.151 18.311 67.086 ;
     RECT  18.311 2.151 19.031 67.014 ;
     RECT  19.031 2.151 46.831 66.969 ;
     RECT  46.831 2.151 48.019 67.014 ;
     RECT  48.019 2.151 48.415 67.05 ;
     RECT  48.415 2.034 49.055 67.05 ;
     RECT  49.055 2.034 50.027 67.014 ;
     RECT  50.027 2.106 50.251 67.014 ;
     RECT  50.251 2.106 50.387 67.05 ;
     RECT  50.387 2.151 51.323 67.05 ;
     RECT  51.323 2.151 55.363 67.014 ;
     RECT  55.363 2.106 55.867 67.014 ;
     RECT  55.867 1.881 56.335 67.014 ;
     RECT  56.335 1.422 56.371 67.014 ;
     RECT  56.371 0.846 57.731 67.014 ;
     RECT  57.811 0.072 57.883 0.09 ;
     RECT  57.883 0.036 58.387 0.09 ;
     RECT  57.731 0.846 58.387 66.969 ;
     RECT  58.387 0.036 59.575 66.969 ;
     RECT  59.575 0.036 60.755 67.014 ;
     RECT  60.755 0.036 61.079 66.969 ;
     RECT  61.079 0.036 62.267 0.054 ;
     RECT  61.079 0.846 63.311 66.969 ;
     RECT  63.311 0.882 63.995 66.969 ;
     RECT  63.995 0.882 64.031 0.936 ;
     RECT  64.031 0.882 64.103 0.9 ;
     RECT  63.995 1.926 64.643 66.969 ;
     RECT  64.643 2.151 66.96 66.969 ;
     RECT  66.96 19.818 67.091 20.106 ;
     RECT  66.96 48.096 67.091 49.302 ;
     RECT  66.96 25.83 67.271 36.306 ;
     RECT  66.96 42.534 67.271 46.296 ;
     RECT  66.96 64.71 67.271 66.888 ;
     RECT  66.96 51.408 67.307 63.612 ;
     RECT  66.96 8.046 67.343 14.166 ;
     RECT  67.271 25.83 67.343 26.586 ;
     RECT  67.271 27.342 67.739 33.444 ;
     RECT  67.271 44.19 67.739 46.296 ;
     RECT  67.343 8.046 67.775 13.968 ;
     RECT  66.96 14.958 67.775 19.062 ;
     RECT  67.739 44.658 67.775 46.296 ;
     RECT  67.775 8.046 67.811 13.932 ;
     RECT  67.775 15.264 67.811 17.946 ;
     RECT  67.775 18.738 67.811 19.062 ;
     RECT  67.091 19.818 67.811 19.836 ;
     RECT  67.739 27.918 67.811 33.444 ;
     RECT  67.271 34.236 67.811 36.306 ;
     RECT  67.775 44.928 67.811 46.296 ;
     RECT  67.811 9.054 67.847 13.932 ;
     RECT  67.811 17.496 67.847 17.514 ;
     RECT  67.343 25.83 67.847 26.082 ;
     RECT  67.811 30.618 67.847 33.444 ;
     RECT  67.271 42.534 67.847 43.362 ;
     RECT  67.307 52.056 67.847 63.27 ;
     RECT  67.847 26.064 67.883 26.082 ;
     RECT  67.847 42.534 67.883 42.552 ;
     RECT  67.847 52.326 67.919 54.702 ;
     RECT  67.847 55.998 67.919 63.144 ;
     RECT  67.271 64.71 67.919 66.816 ;
     RECT  67.919 65.016 67.955 66.816 ;
     RECT  67.919 55.998 67.991 62.766 ;
     RECT  67.847 30.924 68.351 33.444 ;
     RECT  67.091 48.096 68.351 48.726 ;
     RECT  67.811 8.046 68.387 8.064 ;
     RECT  67.847 10.98 68.387 13.194 ;
     RECT  67.811 18.846 68.387 19.062 ;
     RECT  68.351 30.924 68.387 31.482 ;
     RECT  68.351 32.274 68.387 32.364 ;
     RECT  67.811 34.236 68.387 35.802 ;
     RECT  67.811 45.54 68.387 46.296 ;
     RECT  68.387 12.294 68.423 13.194 ;
     RECT  67.811 15.3 68.423 16.704 ;
     RECT  67.811 28.296 68.423 29.628 ;
     RECT  66.96 40.878 68.423 40.896 ;
     RECT  68.351 48.096 68.423 48.114 ;
     RECT  67.991 55.998 68.423 62.568 ;
     RECT  67.955 65.016 68.423 66.006 ;
     RECT  68.423 28.881 68.459 29.016 ;
     RECT  67.919 52.488 68.459 54.702 ;
     RECT  68.423 56.646 68.459 62.154 ;
     RECT  68.423 65.25 68.495 65.736 ;
     RECT  68.459 52.488 68.531 54.468 ;
     RECT  68.495 65.331 68.531 65.736 ;
     RECT  68.531 65.331 68.567 65.502 ;
     RECT  67.819 50.751 68.603 50.769 ;
     RECT  68.531 52.488 68.603 53.694 ;
     RECT  68.459 56.646 68.603 59.634 ;
     RECT  68.459 60.516 68.603 62.154 ;
     RECT  68.567 65.484 68.603 65.502 ;
     RECT  68.603 52.488 68.639 53.046 ;
     RECT  68.639 53.028 68.675 53.046 ;
     RECT  68.575 55.611 68.675 55.629 ;
     RECT  68.603 60.516 68.675 62.028 ;
     RECT  68.603 56.646 68.747 57.096 ;
     RECT  68.675 60.588 68.747 62.028 ;
     RECT  67.847 9.09 68.791 10.188 ;
     RECT  68.387 10.98 68.791 11.538 ;
     RECT  68.387 32.31 68.855 32.364 ;
     RECT  67.847 43.344 68.863 43.362 ;
     RECT  68.603 58.428 68.891 59.634 ;
     RECT  66.96 7.164 68.899 7.254 ;
     RECT  68.387 35.55 68.927 35.802 ;
     RECT  68.899 7.128 68.935 7.254 ;
     RECT  68.423 12.366 68.935 13.194 ;
     RECT  68.423 16.344 68.935 16.704 ;
     RECT  68.387 34.236 68.963 34.794 ;
     RECT  68.863 43.344 68.963 43.479 ;
     RECT  68.531 54.45 68.963 54.468 ;
     RECT  68.935 7.128 68.999 7.686 ;
     RECT  68.791 9.09 68.999 11.538 ;
     RECT  68.855 32.346 68.999 32.364 ;
     RECT  68.927 35.55 68.999 35.568 ;
     RECT  68.387 45.54 68.999 46.098 ;
     RECT  68.747 61.2 68.999 62.028 ;
     RECT  68.999 7.236 69.035 7.686 ;
     RECT  68.999 9.9 69.035 10.458 ;
     RECT  68.999 11.52 69.035 11.538 ;
     RECT  68.935 12.366 69.035 13.284 ;
     RECT  68.423 15.3 69.035 15.588 ;
     RECT  68.935 16.344 69.035 16.938 ;
     RECT  68.387 18.846 69.035 18.99 ;
     RECT  68.459 28.998 69.035 29.016 ;
     RECT  68.387 31.464 69.035 31.482 ;
     RECT  68.351 33.12 69.035 33.444 ;
     RECT  68.963 34.236 69.035 34.254 ;
     RECT  68.963 43.344 69.035 43.362 ;
     RECT  68.999 46.08 69.035 46.098 ;
     RECT  68.747 56.646 69.035 56.664 ;
     RECT  68.891 58.428 69.035 58.716 ;
     RECT  68.891 59.616 69.035 59.634 ;
     RECT  68.999 61.2 69.035 61.218 ;
     RECT  68.999 62.01 69.035 62.028 ;
     RECT  67.955 66.798 69.035 66.816 ;
     RECT  69.035 10.44 69.107 10.458 ;
     RECT  69.035 12.906 69.107 12.924 ;
    LAYER M3 ;
     RECT  57.888 0.031 57.906 0.067 ;
     RECT  57.816 0.067 57.906 0.091 ;
     RECT  60.048 0.043 60.066 0.091 ;
     RECT  61.02 0.067 61.038 0.091 ;
     RECT  62.244 0.031 62.262 0.091 ;
     RECT  57.816 0.091 57.978 0.103 ;
     RECT  60.804 0.091 63.99 0.125 ;
     RECT  57.816 0.103 58.626 0.139 ;
     RECT  62.424 0.125 63.99 0.139 ;
     RECT  66.204 0.091 66.222 0.221 ;
     RECT  62.424 0.139 64.098 0.235 ;
     RECT  59.724 0.091 60.066 0.283 ;
     RECT  60.804 0.125 61.578 0.283 ;
     RECT  59.724 0.283 61.578 0.317 ;
     RECT  57.636 0.139 58.626 0.331 ;
     RECT  59.724 0.317 59.886 0.331 ;
     RECT  60.66 0.317 61.578 0.365 ;
     RECT  62.424 0.235 64.314 0.413 ;
     RECT  67.176 0.091 67.194 0.523 ;
     RECT  57.636 0.331 59.886 0.571 ;
     RECT  55.98 0.043 55.998 0.811 ;
     RECT  55.8 0.811 55.998 0.841 ;
     RECT  56.952 0.571 59.886 0.841 ;
     RECT  62.424 0.413 64.098 0.869 ;
     RECT  63.576 0.869 64.098 0.905 ;
     RECT  63.576 0.905 64.026 0.941 ;
     RECT  55.8 0.841 59.886 0.955 ;
     RECT  48.528 1.099 48.834 1.147 ;
     RECT  48.528 1.147 49.518 1.723 ;
     RECT  64.764 1.195 64.782 1.723 ;
     RECT  65.52 0.619 65.538 1.723 ;
     RECT  60.876 0.365 61.578 1.795 ;
     RECT  64.764 1.723 65.754 1.819 ;
     RECT  62.424 0.869 62.73 1.876 ;
     RECT  63.576 0.941 63.99 1.876 ;
     RECT  62.424 1.876 63.99 1.915 ;
     RECT  64.764 1.819 65.934 1.915 ;
     RECT  55.584 0.955 59.886 1.921 ;
     RECT  60.624 1.795 61.578 1.921 ;
     RECT  48.528 1.723 50.094 2.029 ;
     RECT  48.42 2.029 50.094 2.101 ;
     RECT  55.584 1.921 61.578 2.101 ;
     RECT  48.42 2.101 50.382 2.143 ;
     RECT  55.368 2.101 61.578 2.143 ;
     RECT  62.424 1.915 65.934 2.143 ;
     RECT  13.215 2.143 13.305 2.191 ;
     RECT  24.015 2.143 24.105 2.191 ;
     RECT  40.215 2.143 40.305 2.191 ;
     RECT  45.615 2.143 45.705 2.191 ;
     RECT  48.42 2.143 51.105 2.191 ;
     RECT  12.996 2.191 13.698 2.227 ;
     RECT  24.015 2.191 24.426 2.227 ;
     RECT  33.3 2.191 33.318 2.227 ;
     RECT  39.024 2.191 39.042 2.227 ;
     RECT  41.868 2.191 41.886 2.227 ;
     RECT  55.368 2.143 65.934 2.227 ;
     RECT  66.672 0.523 67.194 2.227 ;
     RECT  55.368 2.227 67.194 2.255 ;
     RECT  12.168 2.227 12.186 2.263 ;
     RECT  12.996 2.227 14.166 2.263 ;
     RECT  33.156 2.227 33.318 2.263 ;
     RECT  41.868 2.227 42.138 2.263 ;
     RECT  42.948 2.191 42.966 2.263 ;
     RECT  47.88 2.191 51.105 2.263 ;
     RECT  24.015 2.227 25.002 2.299 ;
     RECT  33.156 2.263 33.462 2.299 ;
     RECT  4.716 2.263 4.734 2.335 ;
     RECT  10.692 2.299 10.71 2.335 ;
     RECT  12.168 2.263 14.166 2.335 ;
     RECT  23.832 2.299 25.002 2.335 ;
     RECT  32.868 2.299 33.462 2.335 ;
     RECT  45.216 2.191 45.99 2.335 ;
     RECT  9.756 2.335 9.774 2.371 ;
     RECT  10.584 2.335 10.71 2.371 ;
     RECT  11.7 2.335 14.166 2.371 ;
     RECT  18.615 2.143 18.705 2.371 ;
     RECT  22.284 2.227 22.302 2.371 ;
     RECT  23.616 2.335 25.11 2.371 ;
     RECT  25.956 2.191 25.974 2.371 ;
     RECT  40.215 2.191 41.022 2.371 ;
     RECT  41.868 2.263 43.074 2.371 ;
     RECT  47.88 2.263 51.39 2.371 ;
     RECT  2.415 2.143 2.505 2.413 ;
     RECT  7.815 2.143 7.905 2.413 ;
     RECT  29.415 2.143 29.505 2.413 ;
     RECT  34.815 2.143 34.905 2.413 ;
     RECT  35.712 2.335 36.198 2.413 ;
     RECT  23.544 2.371 26.766 2.461 ;
     RECT  44.748 2.335 45.99 2.461 ;
     RECT  32.508 2.335 33.462 2.488 ;
     RECT  9.756 2.371 14.274 2.489 ;
     RECT  7.815 2.413 8.097 2.491 ;
     RECT  21.096 2.371 21.114 2.491 ;
     RECT  22.284 2.371 22.446 2.491 ;
     RECT  4.716 2.335 4.95 2.497 ;
     RECT  7.815 2.491 8.514 2.497 ;
     RECT  16.344 2.461 16.722 2.497 ;
     RECT  18.615 2.371 19.206 2.497 ;
     RECT  30.852 2.335 30.87 2.497 ;
     RECT  55.584 2.255 67.194 2.525 ;
     RECT  4.716 2.497 5.418 2.533 ;
     RECT  7.815 2.497 8.91 2.533 ;
     RECT  16.344 2.497 19.206 2.533 ;
     RECT  29.415 2.413 29.697 2.533 ;
     RECT  34.815 2.413 36.198 2.533 ;
     RECT  40.215 2.371 43.074 2.533 ;
     RECT  44.748 2.461 46.026 2.533 ;
     RECT  4.716 2.533 5.598 2.569 ;
     RECT  30.852 2.497 31.338 2.569 ;
     RECT  38.736 2.227 39.042 2.569 ;
     RECT  39.996 2.533 43.146 2.569 ;
     RECT  44.748 2.533 46.098 2.569 ;
     RECT  44.748 2.569 46.53 2.582 ;
     RECT  39.996 2.569 43.254 2.587 ;
     RECT  23.544 2.461 27.018 2.597 ;
     RECT  3.78 2.569 3.798 2.605 ;
     RECT  4.608 2.569 5.598 2.605 ;
     RECT  21.096 2.491 22.446 2.605 ;
     RECT  23.868 2.597 27.018 2.605 ;
     RECT  32.508 2.488 33.894 2.605 ;
     RECT  47.88 2.371 52.434 2.605 ;
     RECT  3.78 2.605 5.85 2.641 ;
     RECT  7.815 2.533 9.018 2.641 ;
     RECT  9.756 2.489 9.99 2.641 ;
     RECT  10.836 2.489 14.274 2.641 ;
     RECT  29.415 2.533 30.042 2.641 ;
     RECT  30.78 2.569 31.338 2.641 ;
     RECT  32.364 2.605 33.894 2.641 ;
     RECT  34.815 2.533 36.306 2.641 ;
     RECT  38.628 2.569 39.042 2.641 ;
     RECT  39.996 2.587 43.974 2.641 ;
     RECT  47.88 2.605 52.47 2.641 ;
     RECT  53.208 2.227 53.226 2.641 ;
     RECT  38.628 2.641 43.974 2.731 ;
     RECT  44.748 2.582 46.854 2.731 ;
     RECT  38.628 2.731 46.854 2.767 ;
     RECT  23.868 2.605 27.09 2.795 ;
     RECT  3.744 2.641 6.066 2.803 ;
     RECT  29.415 2.641 31.338 2.803 ;
     RECT  2.415 2.413 2.697 2.827 ;
     RECT  16.236 2.533 19.746 2.839 ;
     RECT  32.364 2.641 36.306 2.839 ;
     RECT  38.376 2.767 46.854 2.839 ;
     RECT  38.376 2.839 46.962 2.867 ;
     RECT  23.94 2.795 27.09 2.903 ;
     RECT  7.815 2.641 9.99 2.911 ;
     RECT  10.836 2.641 14.562 2.911 ;
     RECT  46.944 2.867 46.962 2.911 ;
     RECT  47.736 2.641 53.262 2.911 ;
     RECT  32.256 2.839 36.306 3.019 ;
     RECT  2.376 2.827 2.697 3.037 ;
     RECT  3.636 2.803 6.066 3.037 ;
     RECT  23.976 2.903 27.09 3.037 ;
     RECT  38.376 2.867 46.206 3.053 ;
     RECT  55.98 2.525 67.194 3.065 ;
     RECT  2.376 3.037 6.102 3.109 ;
     RECT  16.02 2.839 19.746 3.109 ;
     RECT  20.844 2.605 22.842 3.109 ;
     RECT  16.02 3.109 22.842 3.145 ;
     RECT  29.196 2.803 31.338 3.145 ;
     RECT  38.376 3.053 38.43 3.145 ;
     RECT  2.34 3.109 6.102 3.181 ;
     RECT  28.944 3.145 31.338 3.181 ;
     RECT  32.256 3.019 36.882 3.181 ;
     RECT  46.944 2.911 53.262 3.299 ;
     RECT  23.976 3.037 27.414 3.301 ;
     RECT  28.944 3.181 37.026 3.307 ;
     RECT  56.196 3.065 67.194 3.335 ;
     RECT  23.976 3.301 28.026 3.341 ;
     RECT  7.524 2.911 9.99 3.379 ;
     RECT  10.836 2.911 14.742 3.379 ;
     RECT  28.944 3.307 37.278 3.379 ;
     RECT  38.124 3.145 38.43 3.379 ;
     RECT  2.34 3.181 6.57 3.403 ;
     RECT  7.524 3.379 14.814 3.403 ;
     RECT  2.34 3.403 14.814 3.407 ;
     RECT  15.984 3.145 22.842 3.415 ;
     RECT  15.696 3.415 22.842 3.451 ;
     RECT  47.736 3.299 53.262 3.451 ;
     RECT  54.864 3.415 54.882 3.451 ;
     RECT  23.976 3.341 27.702 3.569 ;
     RECT  47.736 3.451 53.442 3.577 ;
     RECT  28.944 3.379 38.43 3.613 ;
     RECT  15.696 3.451 22.878 3.641 ;
     RECT  23.976 3.569 27.558 3.643 ;
     RECT  15.696 3.641 17.694 3.677 ;
     RECT  39.456 3.053 46.206 3.685 ;
     RECT  46.944 3.299 46.962 3.685 ;
     RECT  47.736 3.577 53.55 3.685 ;
     RECT  18.432 3.641 22.878 3.721 ;
     RECT  23.724 3.643 27.558 3.721 ;
     RECT  47.736 3.685 53.946 3.721 ;
     RECT  54.864 3.451 55.242 3.721 ;
     RECT  47.736 3.721 55.422 3.847 ;
     RECT  2.415 3.407 14.814 3.955 ;
     RECT  47.736 3.847 55.53 4.109 ;
     RECT  39.456 3.685 46.962 4.117 ;
     RECT  47.736 4.109 54.198 4.117 ;
     RECT  18.432 3.721 27.558 4.145 ;
     RECT  39.456 4.117 54.198 4.145 ;
     RECT  28.728 3.613 38.43 4.153 ;
     RECT  28.656 4.153 38.43 4.261 ;
     RECT  39.456 4.145 53.946 4.261 ;
     RECT  15.84 3.677 17.694 4.423 ;
     RECT  28.656 4.261 53.946 4.451 ;
     RECT  2.415 3.955 14.994 4.531 ;
     RECT  15.732 4.423 17.694 4.531 ;
     RECT  18.432 4.145 24.894 4.531 ;
     RECT  25.668 4.145 27.558 4.531 ;
     RECT  28.656 4.451 38.862 4.649 ;
     RECT  55.152 4.109 55.53 4.657 ;
     RECT  56.268 3.335 67.194 4.657 ;
     RECT  2.415 4.531 24.894 4.685 ;
     RECT  39.636 4.451 53.946 4.685 ;
     RECT  25.668 4.531 27.846 4.801 ;
     RECT  28.656 4.649 31.734 4.801 ;
     RECT  14.832 4.685 24.894 4.927 ;
     RECT  25.668 4.801 31.734 4.927 ;
     RECT  55.152 4.657 67.194 4.999 ;
     RECT  2.415 4.685 14.094 5.035 ;
     RECT  41.652 4.685 53.946 5.189 ;
     RECT  32.544 4.649 38.862 5.269 ;
     RECT  39.636 4.685 40.842 5.269 ;
     RECT  54.828 4.999 67.194 5.341 ;
     RECT  2.376 5.035 14.094 5.467 ;
     RECT  14.832 4.927 31.734 5.467 ;
     RECT  32.544 5.269 40.842 5.563 ;
     RECT  42.084 5.189 53.946 5.611 ;
     RECT  54.72 5.341 67.194 5.611 ;
     RECT  2.376 5.467 31.734 5.737 ;
     RECT  32.544 5.563 41.31 5.737 ;
     RECT  2.376 5.737 41.31 6.235 ;
     RECT  42.084 5.611 67.194 6.235 ;
     RECT  2.376 6.235 67.194 6.683 ;
     RECT  68.94 6.859 68.958 7.051 ;
     RECT  68.94 7.051 69.03 7.099 ;
     RECT  68.904 7.099 69.03 7.159 ;
     RECT  68.472 7.159 69.03 7.195 ;
     RECT  68.4 7.195 69.03 7.435 ;
     RECT  68.364 7.435 69.03 7.691 ;
     RECT  68.364 7.691 68.958 7.709 ;
     RECT  2.415 6.683 67.194 8.107 ;
     RECT  68.364 7.709 68.922 8.107 ;
     RECT  2.415 8.107 68.922 8.237 ;
     RECT  2.415 8.237 67.806 8.573 ;
     RECT  3.6 8.573 67.806 9.005 ;
     RECT  25.632 9.005 67.806 9.049 ;
     RECT  68.94 8.491 69.03 9.163 ;
     RECT  3.6 9.005 24.786 9.197 ;
     RECT  25.632 9.049 67.842 9.319 ;
     RECT  68.832 9.163 69.03 9.319 ;
     RECT  3.6 9.197 24.75 9.689 ;
     RECT  25.632 9.319 69.03 9.689 ;
     RECT  3.6 9.689 19.458 9.851 ;
     RECT  25.632 9.689 42.966 9.895 ;
     RECT  2.415 8.573 2.697 9.931 ;
     RECT  3.6 9.851 19.386 9.931 ;
     RECT  20.34 9.689 24.75 9.931 ;
     RECT  25.56 9.895 42.966 9.931 ;
     RECT  2.415 9.931 19.386 10.013 ;
     RECT  20.34 9.931 42.966 10.435 ;
     RECT  44.028 9.689 69.03 10.435 ;
     RECT  3.888 10.013 19.386 10.597 ;
     RECT  20.34 10.435 69.102 10.597 ;
     RECT  0.036 10.741 0.054 10.831 ;
     RECT  2.415 10.013 3.078 10.867 ;
     RECT  3.888 10.597 69.102 10.867 ;
     RECT  0.036 10.831 0.234 10.939 ;
     RECT  2.415 10.867 69.102 10.975 ;
     RECT  0.036 10.939 0.522 11.209 ;
     RECT  2.304 10.975 69.102 11.435 ;
     RECT  0.036 11.209 0.558 11.669 ;
     RECT  2.304 11.435 18.954 11.677 ;
     RECT  0.108 11.669 0.558 11.789 ;
     RECT  0.108 11.789 0.522 11.885 ;
     RECT  0.108 11.885 0.27 12.173 ;
     RECT  2.268 11.677 18.954 12.281 ;
     RECT  15.804 12.281 18.954 12.289 ;
     RECT  19.728 11.435 69.102 12.289 ;
     RECT  15.804 12.289 69.102 12.557 ;
     RECT  2.268 12.281 15.066 12.821 ;
     RECT  67.788 12.557 69.102 12.929 ;
     RECT  0.144 12.173 0.27 12.941 ;
     RECT  15.804 12.557 66.762 13.055 ;
     RECT  0.144 12.941 0.198 13.063 ;
     RECT  2.304 12.821 15.066 13.099 ;
     RECT  15.804 13.055 44.118 13.099 ;
     RECT  0.108 13.063 0.198 13.181 ;
     RECT  0.108 13.181 0.126 13.229 ;
     RECT  67.788 12.929 69.03 13.325 ;
     RECT  67.788 13.325 68.958 13.387 ;
     RECT  67.752 13.387 68.958 13.405 ;
     RECT  1.152 13.339 1.17 13.483 ;
     RECT  44.856 13.055 66.762 13.483 ;
     RECT  67.716 13.405 68.958 13.483 ;
     RECT  1.152 13.483 1.278 13.613 ;
     RECT  2.304 13.099 44.118 13.837 ;
     RECT  44.856 13.483 68.958 13.837 ;
     RECT  2.304 13.837 68.958 13.963 ;
     RECT  1.26 14.443 1.278 14.635 ;
     RECT  0.108 14.539 0.126 14.669 ;
     RECT  1.152 14.635 1.278 14.669 ;
     RECT  1.152 14.669 1.17 14.765 ;
     RECT  2.268 13.963 68.958 15.019 ;
     RECT  2.268 15.019 69.03 15.629 ;
     RECT  2.304 15.629 66.834 16.375 ;
     RECT  67.716 15.629 69.03 16.375 ;
     RECT  2.304 16.375 69.03 16.709 ;
     RECT  0.468 16.681 0.486 16.771 ;
     RECT  0.216 16.771 0.486 16.879 ;
     RECT  0.216 16.879 0.522 16.951 ;
     RECT  68.94 16.709 69.03 16.973 ;
     RECT  0.216 16.951 0.558 17.041 ;
     RECT  2.304 16.709 67.842 17.105 ;
     RECT  2.304 17.105 20.502 17.185 ;
     RECT  21.348 17.105 67.842 17.549 ;
     RECT  68.94 16.973 68.958 17.645 ;
     RECT  21.348 17.549 67.806 17.681 ;
     RECT  0.108 17.041 0.558 17.707 ;
     RECT  0.108 17.707 0.666 17.837 ;
     RECT  2.268 17.185 20.502 17.851 ;
     RECT  21.348 17.681 41.454 17.851 ;
     RECT  0.108 17.837 0.558 18.413 ;
     RECT  2.268 17.851 41.454 18.419 ;
     RECT  27.216 18.419 41.454 18.535 ;
     RECT  42.264 17.681 67.806 18.535 ;
     RECT  0.108 18.413 0.45 18.701 ;
     RECT  27.216 18.535 67.806 18.763 ;
     RECT  69.012 18.187 69.03 18.763 ;
     RECT  27.216 18.763 69.03 18.995 ;
     RECT  27.216 18.995 68.958 19.037 ;
     RECT  27.216 19.037 68.382 19.067 ;
     RECT  2.268 18.419 26.478 19.139 ;
     RECT  2.304 19.139 26.478 19.201 ;
     RECT  27.216 19.067 67.806 19.201 ;
     RECT  0.108 18.701 0.342 19.373 ;
     RECT  2.304 19.201 67.806 19.841 ;
     RECT  0.144 19.373 0.342 19.915 ;
     RECT  2.304 19.841 67.086 20.039 ;
     RECT  43.524 20.039 67.086 20.111 ;
     RECT  2.304 20.039 42.75 20.147 ;
     RECT  2.304 20.147 42.678 20.309 ;
     RECT  2.304 20.309 42.606 20.381 ;
     RECT  2.304 20.381 42.57 20.395 ;
     RECT  1.8 20.395 42.57 20.443 ;
     RECT  0.144 19.915 0.558 20.477 ;
     RECT  1.728 20.443 42.57 21.104 ;
     RECT  43.524 20.111 66.762 21.104 ;
     RECT  1.728 21.104 66.762 21.299 ;
     RECT  1.8 21.299 66.762 21.569 ;
     RECT  2.268 21.569 66.762 21.631 ;
     RECT  2.268 21.631 66.798 21.965 ;
     RECT  2.304 21.965 66.798 22.009 ;
     RECT  2.304 22.009 66.834 22.109 ;
     RECT  2.376 22.109 66.834 22.199 ;
     RECT  2.415 22.199 66.834 22.469 ;
     RECT  0.54 20.477 0.558 22.577 ;
     RECT  2.415 22.469 66.798 23.125 ;
     RECT  2.376 23.125 66.798 23.287 ;
     RECT  2.376 23.287 66.834 24.475 ;
     RECT  2.376 24.475 66.87 24.935 ;
     RECT  43.884 24.935 66.87 25.043 ;
     RECT  2.376 24.935 43.146 25.439 ;
     RECT  2.376 25.439 43.11 25.591 ;
     RECT  67.824 25.825 67.842 26.059 ;
     RECT  43.92 25.043 66.87 26.131 ;
     RECT  2.34 25.591 43.11 26.203 ;
     RECT  43.92 26.131 66.906 26.251 ;
     RECT  67.824 26.059 67.878 26.251 ;
     RECT  43.92 26.251 67.878 26.491 ;
     RECT  43.884 26.491 67.878 26.669 ;
     RECT  2.34 26.203 43.146 26.671 ;
     RECT  43.884 26.669 67.806 26.671 ;
     RECT  68.94 26.011 68.958 26.765 ;
     RECT  2.34 26.671 67.806 27.365 ;
     RECT  2.376 27.365 67.806 27.779 ;
     RECT  67.716 27.779 67.806 27.979 ;
     RECT  68.94 27.883 68.958 27.979 ;
     RECT  0.504 27.643 0.522 28.111 ;
     RECT  0.108 28.111 0.522 28.183 ;
     RECT  2.376 27.779 66.834 28.255 ;
     RECT  67.716 27.979 68.958 28.555 ;
     RECT  2.304 28.255 66.834 28.561 ;
     RECT  67.716 28.555 69.03 28.561 ;
     RECT  0.108 28.183 0.558 28.973 ;
     RECT  2.304 28.561 69.03 29.021 ;
     RECT  0.108 28.973 0.522 29.069 ;
     RECT  0.108 29.069 0.486 29.165 ;
     RECT  0.108 29.165 0.126 29.261 ;
     RECT  2.304 29.021 68.418 29.645 ;
     RECT  2.304 29.645 68.346 29.707 ;
     RECT  0.072 30.379 0.09 30.451 ;
     RECT  2.268 29.707 68.346 30.577 ;
     RECT  0.072 30.451 0.234 30.649 ;
     RECT  2.232 30.577 68.346 30.667 ;
     RECT  2.232 30.667 68.382 30.763 ;
     RECT  0.072 30.649 0.27 30.919 ;
     RECT  2.232 30.763 68.958 31.051 ;
     RECT  2.232 31.051 69.03 31.109 ;
     RECT  0.072 30.919 0.306 31.117 ;
     RECT  2.232 31.109 43.866 31.217 ;
     RECT  2.268 31.217 43.866 31.229 ;
     RECT  44.604 31.109 69.03 31.487 ;
     RECT  44.604 31.487 68.994 31.891 ;
     RECT  44.46 31.891 68.994 32.063 ;
     RECT  0.072 31.117 0.45 32.225 ;
     RECT  0.144 32.225 0.45 32.237 ;
     RECT  2.268 31.229 43.686 32.269 ;
     RECT  44.46 32.063 67.302 32.269 ;
     RECT  0.36 32.237 0.45 32.341 ;
     RECT  2.268 32.269 67.302 32.369 ;
     RECT  68.292 32.063 68.994 32.495 ;
     RECT  0.36 32.341 0.558 32.525 ;
     RECT  0.36 32.525 0.486 32.717 ;
     RECT  42.372 32.369 67.302 32.971 ;
     RECT  0.36 32.717 0.45 33.115 ;
     RECT  2.268 32.369 41.634 33.115 ;
     RECT  42.372 32.971 67.806 33.115 ;
     RECT  0.18 33.115 0.45 33.163 ;
     RECT  2.268 33.115 67.806 33.269 ;
     RECT  44.028 33.269 67.806 33.305 ;
     RECT  44.064 33.305 67.806 33.349 ;
     RECT  69.012 32.587 69.03 33.448 ;
     RECT  2.268 33.269 43.29 33.539 ;
     RECT  44.064 33.349 67.878 33.539 ;
     RECT  44.1 33.539 67.878 33.581 ;
     RECT  44.1 33.581 67.806 33.611 ;
     RECT  2.268 33.539 43.254 33.773 ;
     RECT  44.1 33.611 66.834 33.809 ;
     RECT  68.976 33.448 69.03 34.123 ;
     RECT  68.94 34.123 69.03 34.219 ;
     RECT  0.108 33.163 0.45 34.253 ;
     RECT  68.904 34.219 69.03 34.259 ;
     RECT  2.304 33.773 43.254 34.321 ;
     RECT  44.1 33.809 66.798 34.321 ;
     RECT  2.304 34.321 66.798 34.421 ;
     RECT  0.144 34.253 0.45 34.465 ;
     RECT  2.34 34.421 66.798 34.619 ;
     RECT  2.415 34.619 66.798 34.735 ;
     RECT  0.144 34.465 0.558 34.829 ;
     RECT  67.788 33.611 67.806 34.891 ;
     RECT  67.752 34.891 67.806 34.987 ;
     RECT  68.904 34.259 68.994 34.987 ;
     RECT  67.752 34.987 68.994 35.033 ;
     RECT  2.415 34.735 66.834 35.195 ;
     RECT  2.415 35.195 41.778 35.267 ;
     RECT  67.752 35.033 67.806 35.303 ;
     RECT  2.415 35.267 41.634 35.515 ;
     RECT  68.904 35.033 68.994 35.573 ;
     RECT  0.144 34.829 0.234 35.693 ;
     RECT  68.904 35.573 68.922 35.807 ;
     RECT  42.588 35.195 66.834 35.941 ;
     RECT  2.304 35.515 41.634 35.969 ;
     RECT  2.415 35.969 41.634 36.121 ;
     RECT  42.408 35.941 66.834 36.121 ;
     RECT  0.144 35.693 0.198 36.139 ;
     RECT  0.108 36.139 0.198 36.284 ;
     RECT  67.788 35.303 67.806 36.311 ;
     RECT  2.415 36.121 66.834 36.419 ;
     RECT  34.74 36.419 66.834 36.545 ;
     RECT  2.415 36.419 34.002 36.715 ;
     RECT  37.656 36.545 66.834 37.049 ;
     RECT  2.304 36.715 34.002 37.129 ;
     RECT  0.108 36.284 0.162 37.324 ;
     RECT  0.108 37.324 0.198 37.469 ;
     RECT  34.74 36.545 36.738 37.471 ;
     RECT  37.656 37.049 66.762 37.471 ;
     RECT  2.268 37.129 34.002 37.561 ;
     RECT  34.74 37.471 66.762 37.561 ;
     RECT  2.268 37.561 66.762 37.625 ;
     RECT  2.268 37.625 44.262 38.039 ;
     RECT  45.072 37.625 66.762 38.101 ;
     RECT  0.108 37.469 0.162 38.381 ;
     RECT  33.588 38.039 44.262 38.551 ;
     RECT  45.072 38.101 66.834 38.551 ;
     RECT  2.268 38.039 32.85 38.587 ;
     RECT  0.216 38.635 0.342 38.779 ;
     RECT  2.232 38.587 32.85 38.821 ;
     RECT  33.588 38.551 66.834 38.821 ;
     RECT  0.216 38.779 0.414 38.849 ;
     RECT  2.232 38.821 66.906 38.939 ;
     RECT  2.232 38.939 36.774 39.047 ;
     RECT  0.216 38.849 0.378 39.053 ;
     RECT  0.216 39.053 0.234 39.149 ;
     RECT  2.268 39.047 36.774 39.437 ;
     RECT  2.304 39.437 36.774 39.793 ;
     RECT  37.512 38.939 66.906 39.793 ;
     RECT  2.304 39.793 66.906 39.857 ;
     RECT  0.144 39.691 0.162 39.883 ;
     RECT  29.088 39.857 66.906 39.893 ;
     RECT  0.144 39.883 0.234 39.979 ;
     RECT  0.144 39.979 0.306 40.267 ;
     RECT  34.524 39.893 66.906 40.361 ;
     RECT  0.144 40.267 0.342 40.397 ;
     RECT  0.108 40.405 0.126 40.493 ;
     RECT  2.304 39.857 28.242 40.675 ;
     RECT  29.088 39.893 33.642 40.675 ;
     RECT  2.304 40.675 33.642 40.711 ;
     RECT  34.524 40.361 66.87 40.711 ;
     RECT  2.304 40.711 66.87 41.035 ;
     RECT  2.268 41.035 66.87 41.135 ;
     RECT  2.268 41.135 26.55 41.171 ;
     RECT  2.304 41.171 26.55 41.369 ;
     RECT  0.108 41.323 0.126 41.371 ;
     RECT  0.108 41.371 0.198 41.611 ;
     RECT  2.376 41.369 26.55 41.881 ;
     RECT  27.324 41.135 66.87 41.881 ;
     RECT  0.108 41.611 0.342 41.917 ;
     RECT  0.108 41.917 0.378 42.061 ;
     RECT  2.376 41.881 66.87 42.091 ;
     RECT  68.4 40.873 68.418 42.283 ;
     RECT  67.788 42.283 68.418 42.605 ;
     RECT  0.108 42.061 0.558 42.701 ;
     RECT  0.18 42.701 0.558 42.749 ;
     RECT  2.304 42.091 66.87 43.033 ;
     RECT  67.788 42.605 67.878 43.033 ;
     RECT  0.54 42.749 0.558 43.085 ;
     RECT  69.012 42.763 69.03 43.339 ;
     RECT  1.296 43.243 1.314 43.435 ;
     RECT  2.304 43.033 67.878 43.435 ;
     RECT  68.832 43.339 69.03 43.469 ;
     RECT  1.296 43.435 67.878 44.203 ;
     RECT  68.868 43.469 69.03 44.203 ;
     RECT  0.144 44.011 0.162 44.299 ;
     RECT  0.144 44.299 0.342 44.528 ;
     RECT  0.324 44.528 0.342 44.717 ;
     RECT  1.296 44.203 69.03 44.971 ;
     RECT  1.152 44.971 69.03 45.023 ;
     RECT  67.716 45.023 69.03 45.221 ;
     RECT  68.292 45.221 69.03 45.725 ;
     RECT  1.152 45.023 66.726 45.731 ;
     RECT  68.328 45.725 69.03 45.797 ;
     RECT  25.632 45.731 66.726 45.841 ;
     RECT  0.324 45.931 0.342 46.027 ;
     RECT  0.108 46.027 0.342 46.061 ;
     RECT  68.364 45.797 69.03 46.103 ;
     RECT  0.108 46.061 0.126 46.157 ;
     RECT  68.364 46.103 68.382 46.301 ;
     RECT  25.632 45.841 66.834 46.381 ;
     RECT  1.152 45.731 24.642 46.921 ;
     RECT  1.152 46.921 24.714 47.047 ;
     RECT  25.632 46.381 66.942 47.047 ;
     RECT  1.152 47.047 66.942 47.111 ;
     RECT  1.224 47.111 66.942 47.489 ;
     RECT  1.404 47.489 66.942 47.957 ;
     RECT  68.4 48.091 68.418 48.361 ;
     RECT  1.98 47.957 66.942 48.389 ;
     RECT  2.376 48.389 66.942 48.433 ;
     RECT  2.376 48.433 67.05 48.659 ;
     RECT  25.416 48.659 67.05 48.731 ;
     RECT  25.452 48.731 67.05 49.279 ;
     RECT  2.376 48.659 24.678 49.783 ;
     RECT  25.452 49.279 67.086 49.783 ;
     RECT  2.376 49.783 67.086 50.009 ;
     RECT  2.415 50.009 67.086 50.153 ;
     RECT  45.504 50.153 67.086 50.333 ;
     RECT  67.824 48.361 68.418 50.746 ;
     RECT  2.415 50.153 44.766 50.863 ;
     RECT  2.34 50.863 44.766 51.061 ;
     RECT  45.576 50.333 67.086 51.061 ;
     RECT  2.34 51.061 67.086 51.403 ;
     RECT  67.824 50.746 68.598 51.403 ;
     RECT  2.34 51.403 68.598 52.205 ;
     RECT  2.415 52.205 68.598 52.483 ;
     RECT  2.415 52.483 68.634 53.018 ;
     RECT  2.415 53.018 68.67 53.519 ;
     RECT  44.1 53.519 68.67 53.699 ;
     RECT  44.172 53.699 68.67 54.331 ;
     RECT  44.172 54.331 69.03 54.605 ;
     RECT  2.415 53.519 43.326 54.715 ;
     RECT  44.172 54.605 68.958 54.715 ;
     RECT  2.415 54.715 68.958 55.291 ;
     RECT  2.376 55.291 68.958 55.679 ;
     RECT  2.415 55.679 68.958 55.757 ;
     RECT  2.415 55.757 68.634 56.491 ;
     RECT  2.415 56.491 69.03 57.065 ;
     RECT  2.415 57.065 5.454 57.877 ;
     RECT  6.228 57.065 69.03 57.877 ;
     RECT  2.415 57.877 69.03 58.145 ;
     RECT  2.415 58.145 8.838 58.157 ;
     RECT  9.684 58.145 69.03 58.733 ;
     RECT  2.415 58.157 8.586 58.891 ;
     RECT  2.415 58.891 8.838 58.927 ;
     RECT  9.684 58.733 68.886 58.927 ;
     RECT  2.415 58.927 68.886 59.071 ;
     RECT  2.376 59.071 68.886 59.563 ;
     RECT  2.376 59.563 69.03 59.765 ;
     RECT  2.415 59.765 69.03 59.873 ;
     RECT  2.415 59.873 19.278 60.655 ;
     RECT  20.016 59.873 69.03 60.655 ;
     RECT  2.415 60.655 69.03 61.223 ;
     RECT  2.415 61.223 68.994 62.005 ;
     RECT  2.415 62.005 69.03 62.429 ;
     RECT  2.415 62.429 10.098 62.779 ;
     RECT  2.34 62.779 10.098 62.816 ;
     RECT  2.415 62.816 10.098 63.247 ;
     RECT  10.944 62.429 69.03 63.247 ;
     RECT  2.415 63.247 69.03 63.617 ;
     RECT  2.415 63.617 44.55 63.787 ;
     RECT  2.34 63.787 44.55 63.821 ;
     RECT  2.34 63.821 9.666 63.851 ;
     RECT  2.415 63.851 9.666 63.923 ;
     RECT  10.584 63.821 44.55 64.561 ;
     RECT  45.288 63.617 69.03 64.561 ;
     RECT  10.584 64.561 69.03 64.589 ;
     RECT  3.456 63.923 9.666 64.669 ;
     RECT  10.584 64.589 68.49 64.669 ;
     RECT  3.456 64.669 68.49 65.129 ;
     RECT  2.415 63.923 2.697 65.137 ;
     RECT  3.456 65.129 11.07 65.137 ;
     RECT  11.952 65.129 68.49 65.165 ;
     RECT  2.415 65.137 11.07 65.201 ;
     RECT  12.096 65.165 68.49 65.201 ;
     RECT  13.068 65.201 68.49 65.323 ;
     RECT  13.068 65.323 69.03 65.435 ;
     RECT  22.284 65.435 69.03 65.543 ;
     RECT  22.284 65.543 36.45 65.549 ;
     RECT  37.296 65.543 69.03 65.549 ;
     RECT  10.584 65.201 11.07 65.669 ;
     RECT  13.068 65.435 21.546 65.669 ;
     RECT  37.296 65.549 37.674 65.669 ;
     RECT  2.415 65.201 9.666 65.705 ;
     RECT  37.296 65.669 37.53 65.705 ;
     RECT  3.672 65.705 9.666 65.741 ;
     RECT  10.584 65.669 11.034 65.741 ;
     RECT  10.584 65.741 10.818 65.777 ;
     RECT  38.52 65.549 69.03 65.813 ;
     RECT  3.672 65.741 3.69 65.849 ;
     RECT  38.52 65.813 43.614 65.849 ;
     RECT  44.388 65.813 69.03 65.933 ;
     RECT  22.284 65.549 36.162 65.939 ;
     RECT  37.296 65.705 37.422 65.939 ;
     RECT  44.388 65.933 44.406 65.939 ;
     RECT  13.215 65.669 21.546 65.975 ;
     RECT  37.296 65.939 37.314 65.975 ;
     RECT  38.52 65.849 42.93 65.975 ;
     RECT  45.396 65.933 69.03 66.119 ;
     RECT  10.584 65.777 10.71 66.209 ;
     RECT  22.284 65.939 35.097 66.209 ;
     RECT  4.428 65.741 9.666 66.245 ;
     RECT  14.22 65.975 21.546 66.245 ;
     RECT  22.284 66.209 27.522 66.269 ;
     RECT  38.7 65.975 42.93 66.281 ;
     RECT  22.824 66.269 27.522 66.317 ;
     RECT  14.22 66.245 20.574 66.353 ;
     RECT  36.144 65.939 36.162 66.353 ;
     RECT  4.608 66.245 9.666 66.389 ;
     RECT  28.368 66.209 33.894 66.461 ;
     RECT  4.896 66.389 7.074 66.479 ;
     RECT  7.815 66.389 9.666 66.479 ;
     RECT  16.38 66.353 20.574 66.479 ;
     RECT  28.368 66.461 33.786 66.479 ;
     RECT  38.7 66.281 42.678 66.479 ;
     RECT  45.615 66.119 69.03 66.479 ;
     RECT  14.22 66.353 15.642 66.515 ;
     RECT  20.556 66.479 20.574 66.515 ;
     RECT  22.932 66.317 27.522 66.515 ;
     RECT  28.368 66.479 31.626 66.515 ;
     RECT  38.808 66.479 40.914 66.515 ;
     RECT  38.808 66.515 38.826 66.551 ;
     RECT  41.652 66.479 42.678 66.551 ;
     RECT  5.688 66.479 7.038 66.587 ;
     RECT  7.815 66.479 8.478 66.587 ;
     RECT  39.672 66.515 40.914 66.587 ;
     RECT  42.228 66.551 42.678 66.587 ;
     RECT  4.896 66.479 4.914 66.623 ;
     RECT  5.688 66.587 6.174 66.623 ;
     RECT  6.984 66.587 7.038 66.623 ;
     RECT  7.815 66.587 8.154 66.623 ;
     RECT  14.22 66.515 15.426 66.623 ;
     RECT  16.452 66.479 19.71 66.623 ;
     RECT  42.228 66.587 42.246 66.623 ;
     RECT  17.352 66.623 19.71 66.659 ;
     RECT  21.528 66.245 21.546 66.659 ;
     RECT  40.215 66.587 40.914 66.659 ;
     RECT  2.415 65.705 2.697 66.707 ;
     RECT  7.815 66.623 8.097 66.707 ;
     RECT  34.815 66.209 35.097 66.707 ;
     RECT  40.215 66.659 40.497 66.707 ;
     RECT  45.615 66.479 45.897 66.707 ;
     RECT  9.252 66.479 9.666 66.749 ;
     RECT  10.692 66.209 10.71 66.749 ;
     RECT  14.22 66.623 15.138 66.749 ;
     RECT  23.472 66.515 27.522 66.749 ;
     RECT  28.476 66.515 31.626 66.749 ;
     RECT  32.4 66.479 32.418 66.749 ;
     RECT  46.836 66.479 69.03 66.749 ;
     RECT  13.215 65.975 13.497 66.757 ;
     RECT  14.22 66.749 14.814 66.757 ;
     RECT  6.156 66.623 6.174 66.785 ;
     RECT  6.984 66.623 7.002 66.785 ;
     RECT  9.648 66.749 9.666 66.785 ;
     RECT  17.352 66.659 19.026 66.785 ;
     RECT  25.848 66.749 27.45 66.785 ;
     RECT  30.384 66.749 31.446 66.785 ;
     RECT  13.215 66.757 14.814 66.797 ;
     RECT  27.108 66.785 27.45 66.797 ;
     RECT  59.58 66.749 69.03 66.797 ;
     RECT  27.108 66.797 27.126 66.821 ;
     RECT  28.512 66.749 29.505 66.821 ;
     RECT  66.708 66.797 69.03 66.821 ;
     RECT  26.28 66.785 26.298 66.857 ;
     RECT  23.472 66.749 24.714 66.893 ;
     RECT  23.472 66.893 24.105 66.929 ;
     RECT  28.728 66.821 29.505 66.929 ;
     RECT  46.836 66.749 58.662 66.929 ;
     RECT  66.708 66.821 68.958 66.929 ;
     RECT  2.415 66.707 2.505 66.977 ;
     RECT  7.815 66.707 7.905 66.977 ;
     RECT  13.215 66.797 13.305 66.977 ;
     RECT  24.015 66.929 24.105 66.977 ;
     RECT  29.415 66.929 29.505 66.977 ;
     RECT  34.815 66.707 34.905 66.977 ;
     RECT  40.215 66.707 40.305 66.977 ;
     RECT  45.615 66.707 45.705 66.977 ;
     RECT  55.872 66.929 58.662 66.977 ;
     RECT  67.284 66.929 68.958 66.989 ;
     RECT  14.22 66.797 14.814 67.019 ;
     RECT  17.352 66.785 17.442 67.019 ;
     RECT  18.288 66.785 19.026 67.019 ;
     RECT  46.836 66.929 46.854 67.019 ;
     RECT  56.952 66.977 58.662 67.019 ;
     RECT  59.58 66.797 65.862 67.019 ;
     RECT  17.352 67.019 17.37 67.091 ;
     RECT  18.288 67.019 18.306 67.091 ;
     RECT  67.968 66.989 68.958 67.181 ;
     RECT  59.616 67.019 65.862 67.229 ;
     RECT  47.916 66.929 55.134 67.277 ;
     RECT  59.616 67.229 63.918 67.277 ;
     RECT  59.616 67.277 62.154 67.325 ;
     RECT  67.968 67.181 68.598 67.469 ;
     RECT  67.968 67.469 68.346 67.517 ;
     RECT  61.488 67.325 62.154 67.853 ;
     RECT  62.892 67.277 63.918 67.853 ;
     RECT  48.096 67.277 54.99 68.381 ;
     RECT  64.764 67.229 65.862 68.381 ;
     RECT  48.096 68.381 50.418 68.429 ;
     RECT  51.84 68.381 54.99 68.429 ;
     RECT  57.888 67.019 58.662 68.429 ;
     RECT  62.136 67.853 62.154 68.429 ;
     RECT  63.288 67.853 63.918 68.429 ;
     RECT  64.908 68.381 65.862 68.429 ;
     RECT  48.096 68.429 49.446 68.477 ;
     RECT  63.9 68.429 63.918 68.477 ;
     RECT  56.952 67.019 57.15 68.491 ;
     RECT  58.14 68.429 58.662 68.491 ;
     RECT  59.616 67.325 60.462 68.491 ;
     RECT  48.096 68.477 48.114 68.525 ;
     RECT  55.872 66.977 56.034 68.525 ;
     RECT  56.952 68.491 57.258 68.539 ;
     RECT  58.14 68.491 58.734 68.539 ;
     RECT  59.616 68.491 60.93 68.539 ;
     RECT  52.236 68.429 54.99 68.621 ;
     RECT  56.808 68.539 57.258 68.669 ;
     RECT  58.14 68.539 60.93 68.669 ;
     RECT  52.236 68.621 54.738 68.717 ;
     RECT  58.14 68.669 60.39 68.717 ;
     RECT  48.888 68.477 49.374 68.813 ;
     RECT  58.14 68.717 58.158 68.813 ;
     RECT  65.844 68.429 65.862 68.875 ;
     RECT  59.292 68.717 60.39 68.909 ;
     RECT  56.808 68.669 57.15 68.957 ;
     RECT  48.888 68.813 48.906 69.005 ;
     RECT  52.236 68.717 54.378 69.005 ;
     RECT  55.692 68.635 55.71 69.005 ;
     RECT  57.132 68.957 57.15 69.005 ;
     RECT  59.364 68.909 60.39 69.005 ;
     RECT  65.844 68.875 66.798 69.005 ;
     RECT  68.328 67.517 68.346 69.005 ;
     RECT  54.36 69.005 54.378 69.053 ;
     RECT  59.688 69.005 59.706 69.053 ;
     RECT  61.2 68.971 61.218 69.101 ;
    LAYER M4 ;
     RECT  0.06 11.568 0.097 14.568 ;
     RECT  0.06 28.656 0.097 46.056 ;
     RECT  0.097 11.568 0.137 14.664 ;
     RECT  0.137 11.664 0.173 14.664 ;
     RECT  0.173 11.76 0.569 14.664 ;
     RECT  0.569 12.048 1.141 14.664 ;
     RECT  1.141 12.048 2.293 14.76 ;
     RECT  0.06 17.712 2.293 20.712 ;
     RECT  0.097 28.656 2.293 46.152 ;
     RECT  2.365 2.832 2.408 2.856 ;
     RECT  2.365 5.04 2.408 5.064 ;
     RECT  2.293 11.952 2.408 14.76 ;
     RECT  2.293 17.712 2.408 20.856 ;
     RECT  2.329 26.112 2.408 26.136 ;
     RECT  2.293 28.512 2.408 46.152 ;
     RECT  2.365 48.48 2.408 48.504 ;
     RECT  2.329 50.88 2.408 50.904 ;
     RECT  2.329 62.784 2.408 62.808 ;
     RECT  2.329 63.792 2.408 63.816 ;
     RECT  2.408 2.148 2.512 66.972 ;
     RECT  2.512 2.418 2.704 66.702 ;
     RECT  2.704 28.512 2.801 46.056 ;
     RECT  2.801 28.512 2.837 28.536 ;
     RECT  2.704 12.048 2.873 14.76 ;
     RECT  2.704 57.072 2.945 57.096 ;
     RECT  2.704 59.472 2.945 59.496 ;
     RECT  2.704 53.04 2.963 55.848 ;
     RECT  2.704 52.032 2.981 52.056 ;
     RECT  2.704 16.992 3.017 20.376 ;
     RECT  2.801 29.808 3.125 46.056 ;
     RECT  3.125 30.72 3.269 46.056 ;
     RECT  2.704 47.712 3.377 50.904 ;
     RECT  3.017 17.712 3.413 20.376 ;
     RECT  2.704 7.728 3.443 8.568 ;
     RECT  3.413 18.432 3.485 20.376 ;
     RECT  2.963 55.824 3.557 55.848 ;
     RECT  2.704 6.72 3.593 6.744 ;
     RECT  3.443 8.544 3.629 8.568 ;
     RECT  2.704 25.68 3.629 26.136 ;
     RECT  3.377 49.008 3.733 50.904 ;
     RECT  3.733 49.008 3.773 51.192 ;
     RECT  2.963 53.04 3.779 54.744 ;
     RECT  2.873 12.528 3.841 14.664 ;
     RECT  3.485 18.528 3.845 20.376 ;
     RECT  3.377 47.712 3.877 47.736 ;
     RECT  2.704 62.784 3.877 62.808 ;
     RECT  2.704 63.792 3.877 63.816 ;
     RECT  2.704 2.832 3.905 3.144 ;
     RECT  2.704 9.984 3.913 10.008 ;
     RECT  3.877 62.784 3.913 63.816 ;
     RECT  2.704 4.512 3.971 5.736 ;
     RECT  3.877 23.664 3.985 23.688 ;
     RECT  3.805 11.136 4.021 11.16 ;
     RECT  3.841 12.192 4.021 14.664 ;
     RECT  3.697 16.56 4.021 16.584 ;
     RECT  3.269 30.816 4.021 46.056 ;
     RECT  3.877 47.28 4.021 47.736 ;
     RECT  3.913 62.64 4.025 63.816 ;
     RECT  4.025 62.736 4.076 63.816 ;
     RECT  3.913 9.84 4.093 10.008 ;
     RECT  3.985 23.664 4.129 23.736 ;
     RECT  4.093 9.648 4.133 10.008 ;
     RECT  4.021 30.816 4.169 47.736 ;
     RECT  4.076 62.736 4.169 64.584 ;
     RECT  4.021 11.136 4.241 14.664 ;
     RECT  3.779 53.04 4.277 54.648 ;
     RECT  4.169 30.816 4.309 31.896 ;
     RECT  4.277 53.04 4.309 53.064 ;
     RECT  4.309 29.856 4.345 31.896 ;
     RECT  3.733 56.304 4.349 56.328 ;
     RECT  4.021 16.56 4.453 17.16 ;
     RECT  3.845 18.528 4.453 19.368 ;
     RECT  2.704 22.56 4.453 22.584 ;
     RECT  4.129 23.664 4.453 23.976 ;
     RECT  3.845 20.352 4.457 20.376 ;
     RECT  4.241 14.016 4.489 14.664 ;
     RECT  4.381 28.752 4.489 28.776 ;
     RECT  4.345 29.76 4.489 31.896 ;
     RECT  4.309 52.368 4.493 53.064 ;
     RECT  4.489 28.752 4.525 31.896 ;
     RECT  4.489 14.016 4.597 15.336 ;
     RECT  4.453 16.56 4.597 19.368 ;
     RECT  4.453 22.56 4.601 23.976 ;
     RECT  4.277 54.096 4.601 54.648 ;
     RECT  3.629 25.68 4.669 25.704 ;
     RECT  3.773 49.008 4.681 50.184 ;
     RECT  4.169 32.976 4.777 47.736 ;
     RECT  4.601 54.336 4.781 54.648 ;
     RECT  2.704 65.664 4.844 65.688 ;
     RECT  4.597 14.016 4.853 19.368 ;
     RECT  3.773 51.168 4.921 51.192 ;
     RECT  4.681 50.16 4.925 50.184 ;
     RECT  4.844 65.664 4.931 66.6 ;
     RECT  4.129 5.904 4.957 5.928 ;
     RECT  3.913 7.008 4.957 7.032 ;
     RECT  4.601 23.328 4.988 23.976 ;
     RECT  4.669 25.152 4.988 25.704 ;
     RECT  4.853 17.616 4.997 19.368 ;
     RECT  4.493 52.368 4.997 52.824 ;
     RECT  4.633 58.128 4.997 58.152 ;
     RECT  4.169 62.784 5.029 64.584 ;
     RECT  4.957 5.904 5.065 7.032 ;
     RECT  4.525 28.32 5.065 31.896 ;
     RECT  4.921 51.168 5.077 51.336 ;
     RECT  4.777 32.976 5.105 47.832 ;
     RECT  5.065 27.888 5.173 31.896 ;
     RECT  5.105 32.976 5.173 33.864 ;
     RECT  5.093 26.88 5.177 26.904 ;
     RECT  4.501 21.408 5.209 21.432 ;
     RECT  5.173 27.888 5.213 33.864 ;
     RECT  5.077 51.168 5.249 52.152 ;
     RECT  5.213 28.32 5.321 33.864 ;
     RECT  4.681 49.008 5.353 49.032 ;
     RECT  4.241 11.136 5.425 12.888 ;
     RECT  4.853 14.016 5.425 16.536 ;
     RECT  5.209 21.408 5.461 22.056 ;
     RECT  5.105 34.992 5.465 47.832 ;
     RECT  4.988 23.328 5.501 25.704 ;
     RECT  4.931 65.664 5.501 65.688 ;
     RECT  5.461 21.168 5.573 22.056 ;
     RECT  4.133 9.648 5.605 9.864 ;
     RECT  5.573 21.168 5.605 21.672 ;
     RECT  5.353 48.96 5.641 49.032 ;
     RECT  4.525 61.68 5.641 61.704 ;
     RECT  5.065 5.904 5.677 7.752 ;
     RECT  5.605 9.648 5.677 10.152 ;
     RECT  5.641 48.912 5.677 49.032 ;
     RECT  5.501 25.104 5.699 25.704 ;
     RECT  5.641 61.344 5.749 61.704 ;
     RECT  5.465 34.992 5.753 42.792 ;
     RECT  5.677 5.904 5.789 10.152 ;
     RECT  5.245 58.608 5.821 58.632 ;
     RECT  5.749 61.056 5.821 61.704 ;
     RECT  5.699 25.104 5.825 25.368 ;
     RECT  5.461 4.704 5.861 4.728 ;
     RECT  5.501 23.328 5.929 23.736 ;
     RECT  3.905 2.832 5.939 3.432 ;
     RECT  4.997 17.616 5.965 19.272 ;
     RECT  5.605 20.256 5.965 21.672 ;
     RECT  5.821 60.96 6.044 61.704 ;
     RECT  5.029 62.784 6.044 64.632 ;
     RECT  5.821 58.608 6.073 58.68 ;
     RECT  5.789 9.216 6.185 10.152 ;
     RECT  4.781 54.336 6.188 54.6 ;
     RECT  5.321 28.464 6.217 33.864 ;
     RECT  5.789 5.904 6.22 8.088 ;
     RECT  6.073 57.888 6.221 58.68 ;
     RECT  6.188 54.336 6.257 55.224 ;
     RECT  6.217 28.464 6.289 33.912 ;
     RECT  5.249 52.128 6.293 52.152 ;
     RECT  6.044 60.96 6.293 64.632 ;
     RECT  6.185 9.648 6.325 10.152 ;
     RECT  5.425 11.136 6.325 16.536 ;
     RECT  6.289 56.736 6.325 56.76 ;
     RECT  6.221 57.888 6.325 58.632 ;
     RECT  6.22 5.904 6.329 6.072 ;
     RECT  6.325 9.648 6.329 16.536 ;
     RECT  5.677 48.912 6.329 49.368 ;
     RECT  6.293 62.16 6.329 64.632 ;
     RECT  5.929 22.752 6.473 23.736 ;
     RECT  5.461 50.784 6.505 51 ;
     RECT  6.329 9.936 6.541 16.536 ;
     RECT  5.965 17.616 6.541 21.672 ;
     RECT  5.825 25.152 6.545 25.368 ;
     RECT  5.465 43.776 6.545 47.832 ;
     RECT  6.289 28.416 6.613 33.912 ;
     RECT  5.753 34.992 6.613 42.504 ;
     RECT  6.541 9.936 6.641 21.672 ;
     RECT  6.473 22.752 6.641 23.016 ;
     RECT  6.325 56.736 6.725 58.632 ;
     RECT  6.397 26.736 6.793 26.76 ;
     RECT  6.613 28.416 6.793 42.504 ;
     RECT  6.293 60.96 6.829 60.984 ;
     RECT  5.929 4.416 6.833 4.44 ;
     RECT  6.793 26.736 6.865 42.504 ;
     RECT  6.545 43.776 6.865 47.208 ;
     RECT  6.505 50.784 6.865 51.144 ;
     RECT  6.545 25.152 6.973 25.272 ;
     RECT  6.397 53.376 7.009 53.4 ;
     RECT  6.829 60.288 7.009 60.984 ;
     RECT  6.865 26.736 7.261 47.208 ;
     RECT  6.725 57.696 7.297 58.632 ;
     RECT  7.009 59.76 7.297 60.984 ;
     RECT  6.329 6.048 7.405 6.072 ;
     RECT  6.22 7.392 7.405 8.088 ;
     RECT  6.329 63.12 7.405 63.816 ;
     RECT  7.189 65.136 7.405 65.16 ;
     RECT  7.405 6.048 7.477 8.088 ;
     RECT  6.257 54.576 7.477 55.224 ;
     RECT  7.405 63.12 7.585 65.16 ;
     RECT  6.973 66.24 7.585 66.264 ;
     RECT  6.641 9.936 7.628 23.016 ;
     RECT  7.628 9.744 7.693 23.016 ;
     RECT  7.585 63.12 7.693 66.264 ;
     RECT  5.939 3.408 7.808 3.432 ;
     RECT  7.477 6.048 7.808 8.28 ;
     RECT  7.693 9.264 7.808 23.016 ;
     RECT  6.973 24.96 7.808 25.272 ;
     RECT  7.261 26.544 7.808 47.208 ;
     RECT  6.865 50.256 7.808 51.144 ;
     RECT  7.009 53.328 7.808 53.4 ;
     RECT  7.477 54.576 7.808 55.272 ;
     RECT  7.297 57.696 7.808 60.984 ;
     RECT  7.693 62.736 7.808 66.264 ;
     RECT  7.808 2.148 7.912 66.972 ;
     RECT  7.912 2.418 8.104 66.702 ;
     RECT  8.104 63.792 8.165 66.264 ;
     RECT  8.104 28.272 8.201 48.072 ;
     RECT  8.104 24.96 8.345 26.904 ;
     RECT  8.165 66.048 8.525 66.264 ;
     RECT  8.104 23.952 8.531 23.976 ;
     RECT  8.104 6.288 8.741 9.912 ;
     RECT  8.165 63.792 8.777 65.016 ;
     RECT  8.104 59.136 8.819 60.936 ;
     RECT  8.104 58.128 8.86 58.152 ;
     RECT  8.201 28.272 8.867 47.928 ;
     RECT  8.741 6.288 8.921 9.288 ;
     RECT  8.345 25.2 8.957 26.904 ;
     RECT  8.921 6.288 9.101 7.752 ;
     RECT  8.921 9.072 9.101 9.288 ;
     RECT  8.867 47.28 9.101 47.928 ;
     RECT  8.867 28.272 9.107 46.008 ;
     RECT  8.104 56.448 9.173 56.472 ;
     RECT  8.104 62.112 9.173 62.136 ;
     RECT  8.104 5.136 9.317 5.208 ;
     RECT  8.104 10.992 9.317 22.92 ;
     RECT  8.525 66.048 9.353 66.072 ;
     RECT  9.107 28.272 9.389 44.184 ;
     RECT  9.385 62.688 9.469 62.712 ;
     RECT  8.777 63.792 9.533 64.392 ;
     RECT  9.317 10.992 9.569 16.344 ;
     RECT  8.104 51.12 9.569 51.144 ;
     RECT  8.104 53.328 9.589 55.272 ;
     RECT  9.317 17.424 9.601 22.92 ;
     RECT  9.589 52.752 9.637 55.272 ;
     RECT  9.389 42.768 9.641 44.184 ;
     RECT  8.104 2.496 9.785 2.52 ;
     RECT  8.957 25.2 9.785 26.712 ;
     RECT  9.745 57.648 9.817 57.672 ;
     RECT  9.641 43.344 9.821 44.184 ;
     RECT  9.107 45.36 9.821 46.008 ;
     RECT  9.817 57.6 9.853 57.672 ;
     RECT  9.637 52.416 9.857 55.272 ;
     RECT  9.821 45.36 9.929 45.48 ;
     RECT  9.533 63.792 9.929 63.816 ;
     RECT  9.101 47.376 9.961 47.928 ;
     RECT  9.961 47.376 9.997 48.168 ;
     RECT  9.389 28.272 10.033 41.208 ;
     RECT  9.569 11.136 10.037 16.344 ;
     RECT  9.929 45.36 10.073 45.384 ;
     RECT  9.997 47.376 10.177 48.408 ;
     RECT  9.853 57.168 10.213 57.672 ;
     RECT  9.857 53.328 10.253 55.272 ;
     RECT  9.821 43.776 10.289 44.184 ;
     RECT  10.177 47.376 10.397 48.792 ;
     RECT  10.037 14.784 10.429 16.344 ;
     RECT  9.601 17.424 10.429 23.544 ;
     RECT  10.033 27.792 10.429 41.208 ;
     RECT  10.429 27.792 10.492 42.072 ;
     RECT  10.492 27.792 10.505 39.576 ;
     RECT  10.429 14.784 10.545 23.544 ;
     RECT  9.785 25.2 10.545 26.664 ;
     RECT  10.397 47.376 10.573 48.408 ;
     RECT  10.545 14.784 10.577 26.664 ;
     RECT  10.505 27.792 10.577 39.336 ;
     RECT  10.577 14.784 10.595 22.92 ;
     RECT  10.037 11.136 10.613 13.656 ;
     RECT  9.961 3.84 10.645 3.864 ;
     RECT  9.101 9.072 10.681 9.096 ;
     RECT  10.213 57.168 10.681 57.912 ;
     RECT  10.289 43.776 10.685 44.088 ;
     RECT  10.577 27.792 10.717 39.24 ;
     RECT  10.717 27.744 10.721 39.24 ;
     RECT  10.681 9.072 10.753 9.72 ;
     RECT  10.645 3.408 10.789 3.864 ;
     RECT  9.317 5.184 10.789 5.208 ;
     RECT  10.681 57.168 10.789 58.152 ;
     RECT  10.213 52.128 10.829 52.152 ;
     RECT  10.577 24.432 10.861 26.664 ;
     RECT  10.721 27.744 10.861 37.464 ;
     RECT  8.819 60.912 10.861 60.936 ;
     RECT  10.753 8.88 10.865 9.72 ;
     RECT  10.492 41.184 10.865 42.072 ;
     RECT  10.861 60.816 10.897 60.936 ;
     RECT  10.685 44.064 10.901 44.088 ;
     RECT  10.721 38.64 10.973 39.24 ;
     RECT  10.573 46.608 11.077 48.408 ;
     RECT  10.973 38.736 11.081 39.24 ;
     RECT  11.077 46.224 11.123 48.408 ;
     RECT  10.253 53.328 11.153 54.84 ;
     RECT  11.113 62.688 11.185 62.712 ;
     RECT  11.123 46.224 11.189 46.632 ;
     RECT  9.101 6.288 11.221 7.656 ;
     RECT  10.897 60.816 11.257 61.176 ;
     RECT  11.185 62.688 11.297 62.76 ;
     RECT  11.153 53.328 11.365 54.6 ;
     RECT  10.885 59.808 11.365 59.832 ;
     RECT  11.257 60.816 11.365 61.656 ;
     RECT  10.789 3.408 11.473 5.208 ;
     RECT  11.473 2.88 11.509 5.208 ;
     RECT  11.509 2.496 11.513 5.208 ;
     RECT  11.365 59.808 11.513 61.656 ;
     RECT  11.123 47.616 11.545 48.408 ;
     RECT  11.513 2.496 11.557 2.904 ;
     RECT  10.595 14.784 11.585 22.632 ;
     RECT  10.861 24.432 11.621 37.464 ;
     RECT  11.621 24.432 11.725 25.32 ;
     RECT  11.621 26.64 11.761 37.464 ;
     RECT  10.789 57.168 11.845 58.728 ;
     RECT  11.513 59.808 11.845 61.176 ;
     RECT  11.149 51.072 11.869 51.096 ;
     RECT  11.189 46.32 11.873 46.632 ;
     RECT  11.761 26.64 11.981 37.512 ;
     RECT  11.545 40.032 12.049 40.056 ;
     RECT  10.865 41.184 12.049 41.208 ;
     RECT  10.865 9.072 12.121 9.72 ;
     RECT  11.365 52.464 12.121 54.6 ;
     RECT  12.049 40.032 12.125 41.208 ;
     RECT  11.725 24.144 12.157 25.32 ;
     RECT  11.869 50.64 12.157 51.24 ;
     RECT  12.121 52.416 12.157 54.6 ;
     RECT  11.513 3.936 12.161 5.208 ;
     RECT  12.157 50.64 12.193 51.288 ;
     RECT  12.157 52.416 12.193 54.792 ;
     RECT  11.221 6.288 12.373 8.04 ;
     RECT  12.121 9.072 12.373 9.864 ;
     RECT  11.845 57.168 12.373 61.176 ;
     RECT  11.557 2.496 12.409 2.52 ;
     RECT  10.613 11.28 12.409 13.656 ;
     RECT  12.373 56.544 12.445 61.176 ;
     RECT  11.981 26.784 12.517 37.512 ;
     RECT  11.081 38.736 12.517 38.76 ;
     RECT  11.873 46.608 12.517 46.632 ;
     RECT  11.545 47.616 12.517 48.744 ;
     RECT  12.161 4.08 12.589 5.208 ;
     RECT  12.373 6.288 12.589 9.864 ;
     RECT  12.157 23.52 12.625 25.32 ;
     RECT  11.297 62.736 12.661 62.76 ;
     RECT  12.193 49.776 12.733 54.792 ;
     RECT  12.445 55.968 12.733 61.176 ;
     RECT  11.585 14.784 12.769 22.2 ;
     RECT  12.409 2.448 12.805 2.52 ;
     RECT  12.409 10.944 12.949 13.656 ;
     RECT  12.769 14.784 12.949 22.296 ;
     RECT  10.897 65.088 13.045 65.112 ;
     RECT  12.949 10.944 13.057 22.296 ;
     RECT  12.517 26.784 13.093 39.096 ;
     RECT  12.517 46.608 13.093 48.744 ;
     RECT  12.733 49.776 13.093 61.176 ;
     RECT  12.805 2.448 13.208 2.808 ;
     RECT  12.589 4.08 13.208 9.864 ;
     RECT  13.057 10.944 13.208 22.344 ;
     RECT  12.625 23.52 13.208 25.8 ;
     RECT  13.093 26.784 13.208 39.624 ;
     RECT  12.125 40.848 13.208 41.208 ;
     RECT  12.841 42.288 13.208 42.312 ;
     RECT  11.869 43.632 13.208 43.656 ;
     RECT  11.293 45.312 13.208 45.336 ;
     RECT  13.093 46.608 13.208 61.176 ;
     RECT  12.661 62.736 13.208 63.096 ;
     RECT  13.045 64.368 13.208 65.64 ;
     RECT  13.045 66.768 13.208 66.792 ;
     RECT  13.208 2.148 13.312 66.972 ;
     RECT  13.312 2.418 13.504 66.792 ;
     RECT  13.504 4.512 13.565 39.288 ;
     RECT  13.504 64.368 13.565 64.392 ;
     RECT  13.565 4.512 13.619 9.096 ;
     RECT  13.504 42.384 13.619 42.648 ;
     RECT  13.504 43.92 13.667 43.944 ;
     RECT  13.619 5.136 13.673 9.096 ;
     RECT  13.565 10.128 13.673 39.288 ;
     RECT  13.504 2.496 13.745 2.76 ;
     RECT  13.673 10.128 13.817 13.656 ;
     RECT  13.504 45.552 13.853 50.664 ;
     RECT  13.817 10.704 13.889 13.656 ;
     RECT  13.504 66.768 13.889 66.792 ;
     RECT  13.619 42.384 13.9 42.408 ;
     RECT  13.504 60 13.925 63.24 ;
     RECT  13.925 60 14.105 61.752 ;
     RECT  13.673 14.688 14.141 39.288 ;
     RECT  13.504 51.888 14.185 58.728 ;
     RECT  13.745 2.736 14.321 2.76 ;
     RECT  14.185 51.888 14.321 58.584 ;
     RECT  13.504 40.848 14.533 41.208 ;
     RECT  14.321 51.888 14.533 55.176 ;
     RECT  14.533 40.848 14.537 41.544 ;
     RECT  14.105 60 14.573 61.08 ;
     RECT  14.141 39.264 14.681 39.288 ;
     RECT  13.504 65.52 14.713 65.544 ;
     RECT  14.141 14.688 14.723 38.28 ;
     RECT  13.925 62.832 14.789 63.24 ;
     RECT  14.533 50.976 14.821 55.176 ;
     RECT  13.673 5.136 14.897 5.16 ;
     RECT  14.723 14.688 14.915 34.248 ;
     RECT  13.673 6.288 14.965 9.096 ;
     RECT  14.821 50.88 15.068 55.176 ;
     RECT  14.789 62.832 15.073 63.096 ;
     RECT  14.573 60.432 15.077 61.08 ;
     RECT  15.068 50.64 15.155 55.176 ;
     RECT  15.077 60.528 15.181 61.08 ;
     RECT  14.915 23.568 15.185 34.248 ;
     RECT  14.965 6.288 15.217 9.96 ;
     RECT  13.853 45.552 15.221 49.512 ;
     RECT  15.217 5.568 15.329 9.96 ;
     RECT  15.185 23.568 15.329 33.864 ;
     RECT  15.155 50.736 15.401 55.176 ;
     RECT  14.713 65.328 15.469 65.544 ;
     RECT  15.361 43.776 15.505 43.8 ;
     RECT  15.469 65.328 15.509 65.832 ;
     RECT  15.329 23.568 15.617 29.304 ;
     RECT  15.329 30.288 15.617 33.864 ;
     RECT  14.723 35.28 15.793 38.28 ;
     RECT  15.793 35.28 15.833 39.24 ;
     RECT  14.537 41.52 15.901 41.544 ;
     RECT  15.073 62.736 15.905 63.096 ;
     RECT  15.181 60.528 15.937 61.656 ;
     RECT  15.401 51.984 16.009 55.176 ;
     RECT  15.221 45.552 16.117 48.504 ;
     RECT  13.889 10.944 16.153 13.656 ;
     RECT  14.915 14.688 16.153 22.584 ;
     RECT  15.617 32.64 16.153 33.864 ;
     RECT  15.833 35.28 16.153 35.304 ;
     RECT  15.901 41.424 16.153 42.168 ;
     RECT  14.321 56.352 16.153 58.584 ;
     RECT  16.153 56.352 16.297 59.016 ;
     RECT  15.937 60.528 16.297 61.992 ;
     RECT  16.117 45.408 16.333 48.504 ;
     RECT  15.221 49.488 16.333 49.512 ;
     RECT  15.505 43.776 16.373 43.896 ;
     RECT  16.297 56.352 16.373 61.992 ;
     RECT  16.153 10.944 16.405 22.584 ;
     RECT  15.617 23.568 16.405 23.592 ;
     RECT  16.225 2.88 16.409 2.904 ;
     RECT  16.153 41.04 16.409 42.168 ;
     RECT  16.409 41.424 16.481 42.168 ;
     RECT  16.333 45.408 16.501 49.512 ;
     RECT  15.401 50.736 16.501 51 ;
     RECT  16.009 51.984 16.501 55.32 ;
     RECT  16.501 45.408 16.547 55.32 ;
     RECT  16.547 45.408 16.553 52.008 ;
     RECT  16.481 41.52 16.625 42.168 ;
     RECT  15.617 24.672 16.769 29.304 ;
     RECT  15.329 5.568 16.837 9 ;
     RECT  16.405 10.944 16.873 23.592 ;
     RECT  16.373 43.872 16.913 43.896 ;
     RECT  16.153 32.64 16.945 35.304 ;
     RECT  16.945 32.448 16.981 35.352 ;
     RECT  15.833 36.336 16.981 39.24 ;
     RECT  16.837 5.184 16.985 9 ;
     RECT  16.985 5.568 17.017 9 ;
     RECT  16.873 10.176 17.017 23.592 ;
     RECT  16.373 58.176 17.053 61.992 ;
     RECT  15.905 63.072 17.053 63.096 ;
     RECT  16.769 24.912 17.089 29.304 ;
     RECT  15.617 30.288 17.089 31.464 ;
     RECT  17.089 24.912 17.129 31.464 ;
     RECT  16.547 53.328 17.129 55.32 ;
     RECT  17.129 29.52 17.165 31.464 ;
     RECT  16.553 45.696 17.165 52.008 ;
     RECT  17.165 29.52 17.173 29.544 ;
     RECT  17.165 30.528 17.209 31.464 ;
     RECT  15.509 65.808 17.269 65.832 ;
     RECT  17.053 58.176 17.315 63.096 ;
     RECT  16.373 56.352 17.341 57.192 ;
     RECT  17.269 65.136 17.356 66.216 ;
     RECT  17.129 24.912 17.363 28.536 ;
     RECT  17.165 45.696 17.417 45.816 ;
     RECT  17.017 5.568 17.453 23.592 ;
     RECT  17.165 46.848 17.557 52.008 ;
     RECT  17.129 53.328 17.557 54.936 ;
     RECT  17.053 42.384 17.629 42.408 ;
     RECT  17.629 42 17.737 42.408 ;
     RECT  17.737 41.76 17.773 42.408 ;
     RECT  17.417 45.696 17.989 45.72 ;
     RECT  17.363 26.16 18.133 28.536 ;
     RECT  17.773 40.896 18.169 42.408 ;
     RECT  17.209 30.912 18.236 31.464 ;
     RECT  18.236 30.624 18.277 31.464 ;
     RECT  16.981 32.448 18.277 39.24 ;
     RECT  17.557 46.848 18.277 54.936 ;
     RECT  17.341 56.208 18.277 57.192 ;
     RECT  17.315 58.176 18.277 62.76 ;
     RECT  18.169 40.896 18.373 42.6 ;
     RECT  17.989 44.976 18.373 45.72 ;
     RECT  17.363 24.912 18.421 24.936 ;
     RECT  18.133 26.16 18.421 29.112 ;
     RECT  18.373 44.592 18.457 45.72 ;
     RECT  18.373 40.896 18.529 42.744 ;
     RECT  18.457 44.16 18.529 45.72 ;
     RECT  17.356 65.808 18.565 66.216 ;
     RECT  17.453 5.568 18.608 9.096 ;
     RECT  17.453 10.368 18.608 23.592 ;
     RECT  18.421 24.912 18.608 29.112 ;
     RECT  18.277 30.624 18.608 39.24 ;
     RECT  18.529 40.896 18.608 45.72 ;
     RECT  18.277 46.848 18.608 57.192 ;
     RECT  18.277 58.176 18.608 63 ;
     RECT  18.565 65.808 18.608 66.264 ;
     RECT  18.608 2.148 18.712 66.972 ;
     RECT  18.712 2.418 18.904 66.702 ;
     RECT  18.904 2.784 18.965 2.856 ;
     RECT  18.904 10.896 18.965 23.592 ;
     RECT  18.904 53.328 19.001 62.472 ;
     RECT  18.904 44.16 19.037 44.184 ;
     RECT  18.904 40.896 19.145 40.92 ;
     RECT  18.904 24.624 19.181 29.4 ;
     RECT  18.904 42 19.217 42.744 ;
     RECT  18.904 32.832 19.469 33.336 ;
     RECT  18.965 10.944 19.505 23.592 ;
     RECT  18.904 34.416 19.577 39.816 ;
     RECT  18.904 51.6 19.577 52.008 ;
     RECT  18.965 2.832 19.657 2.856 ;
     RECT  19.469 32.832 19.793 33.288 ;
     RECT  19.181 24.624 19.829 24.792 ;
     RECT  19.577 51.792 19.859 52.008 ;
     RECT  19.505 10.944 19.996 23.4 ;
     RECT  18.904 5.28 20.045 9.528 ;
     RECT  19.577 36.336 20.077 39.816 ;
     RECT  19.793 32.832 20.081 33.144 ;
     RECT  18.904 46.176 20.113 48.504 ;
     RECT  18.904 30.912 20.149 31.656 ;
     RECT  20.077 36.336 20.149 40.056 ;
     RECT  19.217 42.192 20.185 42.744 ;
     RECT  19.181 25.824 20.221 29.4 ;
     RECT  20.149 30.912 20.221 31.704 ;
     RECT  20.185 41.952 20.221 42.744 ;
     RECT  20.221 25.824 20.236 31.704 ;
     RECT  19.859 51.792 20.297 51.816 ;
     RECT  20.113 45.504 20.365 48.504 ;
     RECT  18.904 63.6 20.365 63.768 ;
     RECT  18.904 65.04 20.365 65.064 ;
     RECT  20.236 25.824 20.441 31.656 ;
     RECT  20.149 36.336 20.473 40.104 ;
     RECT  20.441 30.336 20.531 31.656 ;
     RECT  20.365 45.168 20.549 48.504 ;
     RECT  20.221 41.424 20.585 42.744 ;
     RECT  18.904 49.488 20.653 50.424 ;
     RECT  20.585 41.952 20.657 42.744 ;
     RECT  20.365 63.6 20.677 65.064 ;
     RECT  18.904 66.24 20.677 66.264 ;
     RECT  20.677 63.6 20.725 66.264 ;
     RECT  20.549 45.168 20.732 45.192 ;
     RECT  20.657 42 20.801 42.744 ;
     RECT  19.577 34.416 20.833 35.352 ;
     RECT  20.473 36.336 20.833 40.152 ;
     RECT  20.833 34.416 20.869 40.152 ;
     RECT  20.732 45.12 20.869 45.192 ;
     RECT  20.441 25.824 21.017 29.112 ;
     RECT  20.045 5.76 21.049 9.528 ;
     RECT  19.996 10.944 21.049 23.304 ;
     RECT  19.829 24.768 21.049 24.792 ;
     RECT  21.017 25.824 21.049 29.016 ;
     RECT  21.049 5.76 21.053 23.304 ;
     RECT  21.049 24.768 21.053 29.016 ;
     RECT  21.053 6 21.085 23.304 ;
     RECT  21.053 24.768 21.085 28.728 ;
     RECT  20.081 33.072 21.085 33.144 ;
     RECT  20.869 34.416 21.085 40.872 ;
     RECT  21.085 33.072 21.089 40.872 ;
     RECT  19.001 53.328 21.109 61.992 ;
     RECT  20.725 63.216 21.109 66.264 ;
     RECT  21.085 6 21.169 28.728 ;
     RECT  20.549 46.176 21.197 48.504 ;
     RECT  21.089 35.088 21.269 40.872 ;
     RECT  21.109 53.328 21.269 66.264 ;
     RECT  20.531 30.912 21.445 31.656 ;
     RECT  21.089 33.072 21.445 33.672 ;
     RECT  21.445 30.912 21.517 33.672 ;
     RECT  20.869 45.024 21.517 45.192 ;
     RECT  21.517 45.024 21.625 45.816 ;
     RECT  20.801 42.192 21.733 42.744 ;
     RECT  21.197 46.848 21.877 48.504 ;
     RECT  20.653 49.488 21.877 51.096 ;
     RECT  21.269 35.28 21.985 40.872 ;
     RECT  21.733 42.192 21.985 43.128 ;
     RECT  21.877 46.848 22.025 51.096 ;
     RECT  21.877 52.176 22.237 52.2 ;
     RECT  21.269 53.328 22.237 64.44 ;
     RECT  21.733 2.496 22.273 2.52 ;
     RECT  21.269 66.24 22.313 66.264 ;
     RECT  21.169 6 22.345 23.352 ;
     RECT  22.237 52.176 22.349 64.44 ;
     RECT  22.273 2.256 22.403 2.52 ;
     RECT  22.345 5.136 22.489 23.352 ;
     RECT  21.169 24.432 22.489 28.728 ;
     RECT  21.517 30.048 22.489 33.672 ;
     RECT  22.489 5.136 22.529 28.728 ;
     RECT  22.529 5.136 22.547 9.096 ;
     RECT  22.489 30.048 22.597 34.152 ;
     RECT  21.985 35.28 22.597 43.128 ;
     RECT  22.025 46.848 22.643 50.28 ;
     RECT  22.529 10.368 22.705 28.728 ;
     RECT  22.597 30.048 22.705 43.128 ;
     RECT  22.349 52.608 22.745 64.44 ;
     RECT  22.705 10.368 22.781 43.128 ;
     RECT  22.547 5.52 22.817 9.096 ;
     RECT  22.817 5.616 22.853 9.096 ;
     RECT  22.745 52.608 22.925 54.216 ;
     RECT  22.643 49.488 23.461 50.28 ;
     RECT  22.853 5.76 23.713 9.096 ;
     RECT  22.781 41.376 23.749 43.128 ;
     RECT  22.925 52.992 23.893 54.216 ;
     RECT  22.745 55.2 23.893 64.44 ;
     RECT  22.357 3.648 24.008 3.672 ;
     RECT  23.713 5.76 24.008 9.288 ;
     RECT  22.781 10.368 24.008 40.104 ;
     RECT  23.749 41.136 24.008 43.128 ;
     RECT  21.625 44.448 24.008 45.816 ;
     RECT  22.643 46.848 24.008 48.504 ;
     RECT  23.461 49.488 24.008 50.712 ;
     RECT  23.965 51.744 24.008 51.768 ;
     RECT  23.893 52.992 24.008 64.44 ;
     RECT  24.008 2.148 24.112 66.972 ;
     RECT  24.112 2.352 24.304 66.702 ;
     RECT  24.304 46.848 24.401 64.872 ;
     RECT  24.304 6.288 24.467 43.416 ;
     RECT  24.401 46.848 24.473 50.616 ;
     RECT  24.304 3.936 24.581 3.96 ;
     RECT  24.473 46.848 24.581 50.376 ;
     RECT  24.401 51.744 24.617 64.872 ;
     RECT  24.467 6.288 24.797 29.592 ;
     RECT  24.467 30.912 24.869 43.416 ;
     RECT  24.304 2.352 25.121 2.376 ;
     RECT  24.797 6.288 25.121 9.096 ;
     RECT  24.869 39.312 25.333 43.416 ;
     RECT  24.304 44.448 25.333 45.72 ;
     RECT  24.617 51.744 25.337 64.344 ;
     RECT  25.333 39.312 25.381 45.72 ;
     RECT  25.381 39.312 25.409 41.352 ;
     RECT  24.797 10.128 25.445 29.592 ;
     RECT  25.337 52.656 25.621 64.344 ;
     RECT  25.381 42.528 25.661 45.72 ;
     RECT  24.581 46.848 25.667 48.264 ;
     RECT  25.667 46.848 25.708 48.072 ;
     RECT  25.621 52.656 25.805 65.016 ;
     RECT  25.445 10.128 25.841 27.768 ;
     RECT  25.805 52.656 25.877 64.344 ;
     RECT  24.869 30.912 25.945 38.28 ;
     RECT  25.409 39.312 25.945 39.816 ;
     RECT  24.304 66.288 26.129 66.312 ;
     RECT  25.513 5.184 26.149 5.208 ;
     RECT  25.121 6.288 26.269 7.176 ;
     RECT  25.121 8.16 26.269 9.096 ;
     RECT  25.841 10.416 26.273 27.768 ;
     RECT  25.877 53.28 26.273 64.344 ;
     RECT  26.149 5.184 26.485 5.304 ;
     RECT  26.269 6.288 26.485 9.096 ;
     RECT  26.273 25.872 26.485 27.768 ;
     RECT  24.581 49.44 26.485 50.184 ;
     RECT  25.945 30.912 26.593 39.816 ;
     RECT  25.409 41.136 26.593 41.352 ;
     RECT  26.485 49.44 26.593 50.376 ;
     RECT  26.273 63.6 26.809 64.344 ;
     RECT  26.377 65.664 26.809 65.688 ;
     RECT  26.593 49.344 26.837 50.376 ;
     RECT  26.557 51.744 26.837 52.152 ;
     RECT  25.445 29.088 26.917 29.592 ;
     RECT  26.593 30.912 26.917 41.352 ;
     RECT  26.837 49.344 26.921 52.152 ;
     RECT  26.557 2.832 26.957 2.856 ;
     RECT  26.917 29.088 26.989 41.352 ;
     RECT  25.661 42.528 26.989 45.24 ;
     RECT  26.485 25.872 27.025 27.816 ;
     RECT  26.485 5.184 27.029 9.096 ;
     RECT  26.273 53.28 27.109 62.568 ;
     RECT  26.273 10.416 27.133 24.792 ;
     RECT  26.989 29.088 27.169 45.24 ;
     RECT  27.109 53.184 27.245 62.568 ;
     RECT  27.245 53.184 27.313 54.216 ;
     RECT  26.921 51.744 27.353 52.152 ;
     RECT  27.353 51.744 27.389 51.768 ;
     RECT  26.809 63.6 27.404 65.688 ;
     RECT  27.349 66.768 27.404 66.792 ;
     RECT  27.025 25.872 27.425 27.912 ;
     RECT  27.169 29.088 27.425 45.528 ;
     RECT  27.404 63.6 27.491 66.792 ;
     RECT  26.921 49.344 27.529 50.712 ;
     RECT  27.425 30 27.569 45.528 ;
     RECT  27.569 30.24 27.709 45.528 ;
     RECT  25.708 46.848 27.709 47.688 ;
     RECT  27.029 5.184 27.74 7.176 ;
     RECT  27.74 5.136 27.827 7.176 ;
     RECT  27.709 30.24 27.827 47.688 ;
     RECT  27.133 10.224 27.853 24.792 ;
     RECT  27.425 25.872 27.853 27.768 ;
     RECT  27.029 8.304 27.889 9.096 ;
     RECT  27.853 10.224 27.889 27.768 ;
     RECT  27.529 49.008 27.889 50.712 ;
     RECT  27.827 40.416 27.929 47.688 ;
     RECT  27.929 41.136 27.961 47.688 ;
     RECT  27.245 55.2 27.961 62.568 ;
     RECT  27.491 63.6 27.961 63.624 ;
     RECT  27.827 30.24 28.001 39.384 ;
     RECT  27.781 3.312 28.453 3.336 ;
     RECT  27.889 8.304 28.573 27.768 ;
     RECT  27.781 28.8 28.573 28.824 ;
     RECT  28.001 30.24 28.693 38.28 ;
     RECT  27.889 49.008 28.717 51.336 ;
     RECT  27.313 53.136 28.741 54.216 ;
     RECT  27.961 55.2 28.741 63.624 ;
     RECT  28.741 53.136 28.748 63.624 ;
     RECT  27.827 6.048 28.753 7.176 ;
     RECT  28.573 8.304 28.753 28.824 ;
     RECT  28.753 6.048 28.825 28.824 ;
     RECT  29.041 4.944 29.077 4.968 ;
     RECT  28.825 6 29.077 28.824 ;
     RECT  28.693 30.048 29.077 38.28 ;
     RECT  27.961 41.136 29.077 47.88 ;
     RECT  28.717 49.008 29.077 51.672 ;
     RECT  28.748 52.704 29.293 63.624 ;
     RECT  27.491 64.704 29.293 66.792 ;
     RECT  28.453 2.496 29.408 3.336 ;
     RECT  29.077 4.656 29.408 4.968 ;
     RECT  29.077 6 29.408 38.28 ;
     RECT  28.001 39.312 29.408 39.384 ;
     RECT  29.077 41.136 29.408 51.672 ;
     RECT  29.293 52.704 29.408 66.792 ;
     RECT  29.408 2.148 29.512 66.972 ;
     RECT  29.512 2.418 29.704 66.702 ;
     RECT  29.704 42.528 29.843 51.72 ;
     RECT  29.704 4.944 29.981 4.968 ;
     RECT  29.704 2.496 30.035 3.96 ;
     RECT  29.704 66.192 30.275 66.552 ;
     RECT  29.704 55.2 30.341 65.016 ;
     RECT  30.341 55.2 30.557 64.968 ;
     RECT  29.704 39.36 30.733 39.672 ;
     RECT  29.704 52.896 30.733 54.216 ;
     RECT  30.557 55.2 30.733 64.872 ;
     RECT  29.704 41.424 30.757 41.496 ;
     RECT  29.843 42.528 30.757 51.672 ;
     RECT  30.757 41.424 30.769 51.672 ;
     RECT  30.035 2.496 30.773 3.144 ;
     RECT  30.769 41.04 30.837 51.672 ;
     RECT  30.275 66.336 31.165 66.552 ;
     RECT  31.165 66.336 31.205 66.696 ;
     RECT  29.704 6 31.273 38.28 ;
     RECT  30.733 39.264 31.273 39.672 ;
     RECT  31.205 66.672 31.457 66.696 ;
     RECT  31.273 6 31.813 39.672 ;
     RECT  30.837 42.144 31.921 51.672 ;
     RECT  30.837 41.04 31.957 41.064 ;
     RECT  31.921 42.096 31.957 51.72 ;
     RECT  31.957 41.04 32.033 51.72 ;
     RECT  32.033 41.136 32.209 51.72 ;
     RECT  30.733 52.896 32.209 64.872 ;
     RECT  31.813 5.904 32.213 39.672 ;
     RECT  32.213 39.36 32.437 39.672 ;
     RECT  32.213 5.904 32.465 38.28 ;
     RECT  32.465 5.904 32.537 28.392 ;
     RECT  32.209 41.136 32.636 64.872 ;
     RECT  32.636 41.136 32.641 65.352 ;
     RECT  32.641 41.136 32.821 65.544 ;
     RECT  32.537 5.904 32.861 28.2 ;
     RECT  32.821 41.136 33.113 66.456 ;
     RECT  33.113 41.136 33.289 49.656 ;
     RECT  33.113 50.688 33.473 66.456 ;
     RECT  32.437 39.36 33.541 39.912 ;
     RECT  33.473 50.688 33.653 64.872 ;
     RECT  32.861 6.288 33.757 28.2 ;
     RECT  32.465 29.472 33.757 38.28 ;
     RECT  33.541 39.36 34.081 40.056 ;
     RECT  33.653 50.688 34.189 64.824 ;
     RECT  30.773 2.496 34.261 2.52 ;
     RECT  33.757 6.288 34.405 38.28 ;
     RECT  34.081 39.264 34.405 40.056 ;
     RECT  33.289 41.088 34.585 49.656 ;
     RECT  34.189 50.64 34.585 64.824 ;
     RECT  34.261 2.496 34.808 3.432 ;
     RECT  34.513 5.136 34.808 5.16 ;
     RECT  34.405 6.288 34.808 40.056 ;
     RECT  34.585 41.088 34.808 64.824 ;
     RECT  33.473 66.432 34.808 66.456 ;
     RECT  34.808 2.148 34.912 66.972 ;
     RECT  34.912 2.418 35.104 66.702 ;
     RECT  35.104 6.288 35.267 29.016 ;
     RECT  35.104 30.24 35.597 39.384 ;
     RECT  35.104 41.664 35.741 64.296 ;
     RECT  35.741 42 36.035 64.296 ;
     RECT  35.104 3.024 36.097 3.048 ;
     RECT  35.267 6.288 36.349 7.272 ;
     RECT  36.097 3.024 36.353 3.576 ;
     RECT  35.104 65.28 36.421 65.304 ;
     RECT  36.421 65.28 36.461 65.544 ;
     RECT  36.035 42 36.641 64.152 ;
     RECT  36.349 6.048 36.677 7.272 ;
     RECT  35.267 8.304 36.713 29.016 ;
     RECT  36.641 46.512 36.749 64.152 ;
     RECT  36.677 6.288 36.853 7.272 ;
     RECT  36.713 8.304 36.853 28.632 ;
     RECT  35.597 30.336 36.853 39.384 ;
     RECT  36.853 6.288 37.109 28.632 ;
     RECT  36.749 46.512 37.109 63.624 ;
     RECT  36.853 30.192 37.285 39.384 ;
     RECT  37.105 40.992 37.285 41.016 ;
     RECT  37.109 46.512 37.331 47.832 ;
     RECT  37.109 6.336 37.753 28.632 ;
     RECT  37.285 30.192 37.753 41.016 ;
     RECT  37.109 48.864 37.753 63.624 ;
     RECT  37.753 48.864 37.793 64.44 ;
     RECT  36.353 3.024 37.825 3.048 ;
     RECT  37.793 52.464 37.829 64.44 ;
     RECT  37.829 52.512 37.837 64.44 ;
     RECT  37.793 48.864 37.865 51.432 ;
     RECT  37.753 6.336 37.897 41.016 ;
     RECT  36.641 42 37.897 45.528 ;
     RECT  36.461 65.52 37.973 65.544 ;
     RECT  37.897 6.336 38.149 45.528 ;
     RECT  38.149 5.472 38.153 45.528 ;
     RECT  37.331 46.608 38.185 47.832 ;
     RECT  37.865 48.864 38.185 50.952 ;
     RECT  37.825 3.024 38.195 3.96 ;
     RECT  38.153 5.472 38.621 39.384 ;
     RECT  37.837 52.512 38.693 63.96 ;
     RECT  38.195 3.024 38.765 3.048 ;
     RECT  38.621 5.472 38.867 29.016 ;
     RECT  38.867 10.32 38.873 29.016 ;
     RECT  38.693 52.944 38.873 63.96 ;
     RECT  38.873 10.32 38.945 28.968 ;
     RECT  38.873 52.992 39.053 63.96 ;
     RECT  38.621 30.096 39.125 39.384 ;
     RECT  39.125 33.888 39.301 39.384 ;
     RECT  38.185 46.608 39.517 50.952 ;
     RECT  39.517 46.608 39.769 51.72 ;
     RECT  38.867 5.472 40.208 9.144 ;
     RECT  38.945 10.32 40.208 28.584 ;
     RECT  39.125 30.096 40.208 32.52 ;
     RECT  39.301 33.888 40.208 39.528 ;
     RECT  38.153 40.8 40.208 45.528 ;
     RECT  39.769 46.608 40.208 51.768 ;
     RECT  39.053 52.992 40.208 63.624 ;
     RECT  40.208 2.148 40.312 66.972 ;
     RECT  40.312 2.418 40.504 66.702 ;
     RECT  40.504 2.832 40.637 2.856 ;
     RECT  40.504 5.472 40.924 55.224 ;
     RECT  40.504 3.888 41.285 3.912 ;
     RECT  40.924 5.472 41.753 51.768 ;
     RECT  41.753 8.304 41.861 51.768 ;
     RECT  41.557 4.272 41.969 4.296 ;
     RECT  41.861 40.368 42.073 51.768 ;
     RECT  40.924 52.992 42.073 55.224 ;
     RECT  40.504 56.352 42.325 63.624 ;
     RECT  42.325 56.352 42.469 64.344 ;
     RECT  42.469 56.352 42.649 64.728 ;
     RECT  41.861 8.304 42.869 39.384 ;
     RECT  42.869 8.304 42.905 9.384 ;
     RECT  42.073 40.368 42.941 55.224 ;
     RECT  42.941 41.088 42.977 55.224 ;
     RECT  42.901 2.736 43.013 2.76 ;
     RECT  41.753 5.472 43.117 7.176 ;
     RECT  42.905 8.304 43.117 9.336 ;
     RECT  43.117 5.472 43.265 9.336 ;
     RECT  42.973 3.936 43.337 3.96 ;
     RECT  42.649 56.352 43.373 64.776 ;
     RECT  42.869 10.416 43.477 39.384 ;
     RECT  43.373 56.352 43.625 64.056 ;
     RECT  42.977 41.136 43.661 55.224 ;
     RECT  43.625 56.352 43.697 63.672 ;
     RECT  43.477 10.416 44.161 39.432 ;
     RECT  43.661 41.136 44.161 51.912 ;
     RECT  43.265 5.472 44.269 9.096 ;
     RECT  44.161 65.472 44.377 65.496 ;
     RECT  44.269 4.608 44.483 9.096 ;
     RECT  44.377 65.472 44.521 65.928 ;
     RECT  44.161 10.416 44.561 51.912 ;
     RECT  44.561 10.416 44.665 39.48 ;
     RECT  44.561 40.896 44.809 51.912 ;
     RECT  43.661 53.04 44.809 55.224 ;
     RECT  44.521 64.944 45.385 65.928 ;
     RECT  43.945 2.592 45.529 2.616 ;
     RECT  45.529 2.592 45.608 3.384 ;
     RECT  44.483 5.472 45.608 9.096 ;
     RECT  44.665 10.08 45.608 39.48 ;
     RECT  44.809 40.896 45.608 55.224 ;
     RECT  43.697 56.352 45.608 63.624 ;
     RECT  45.385 64.944 45.608 65.976 ;
     RECT  45.608 2.148 45.712 66.972 ;
     RECT  45.712 2.418 45.904 66.702 ;
     RECT  45.904 30.192 45.965 32.52 ;
     RECT  45.904 5.472 46.019 7.176 ;
     RECT  45.904 2.592 46.037 3.624 ;
     RECT  45.904 10.08 46.145 28.536 ;
     RECT  46.037 3.6 46.217 3.624 ;
     RECT  46.037 2.592 46.865 2.616 ;
     RECT  45.904 37.968 46.865 41.4 ;
     RECT  45.904 42.48 46.897 48.504 ;
     RECT  45.904 49.488 46.897 65.976 ;
     RECT  46.145 10.416 47.005 28.536 ;
     RECT  46.865 40.8 47.005 41.4 ;
     RECT  46.897 42.48 47.005 65.976 ;
     RECT  45.904 33.6 47.041 36.936 ;
     RECT  47.005 40.8 47.045 65.976 ;
     RECT  47.041 33.504 47.113 36.936 ;
     RECT  46.865 37.968 47.113 39.384 ;
     RECT  45.965 30.192 47.149 32.328 ;
     RECT  47.113 33.504 47.149 39.384 ;
     RECT  47.005 10.416 47.269 28.872 ;
     RECT  47.149 30.192 47.269 39.384 ;
     RECT  47.269 4.128 47.369 4.152 ;
     RECT  45.904 8.304 47.509 9.096 ;
     RECT  47.269 10.416 47.509 39.384 ;
     RECT  47.045 65.952 47.833 65.976 ;
     RECT  46.019 6.24 47.852 7.176 ;
     RECT  47.833 65.952 47.905 66.552 ;
     RECT  47.045 40.8 47.941 64.968 ;
     RECT  47.941 40.608 47.987 64.968 ;
     RECT  47.852 5.856 48.013 7.176 ;
     RECT  47.509 8.304 48.013 39.384 ;
     RECT  47.905 65.952 48.121 67.272 ;
     RECT  48.013 5.856 48.125 39.384 ;
     RECT  47.893 4.8 48.161 4.824 ;
     RECT  47.987 40.608 48.179 64.872 ;
     RECT  48.085 68.496 48.265 68.52 ;
     RECT  48.179 46.56 48.269 64.872 ;
     RECT  48.269 46.56 48.413 64.248 ;
     RECT  48.179 40.608 48.419 45.576 ;
     RECT  48.125 5.856 48.517 29.304 ;
     RECT  48.121 65.952 48.517 67.32 ;
     RECT  48.265 68.4 48.517 68.52 ;
     RECT  48.125 30.576 48.557 39.384 ;
     RECT  48.476 1.104 48.613 1.128 ;
     RECT  48.517 65.952 48.613 68.52 ;
     RECT  48.557 30.912 48.845 39.384 ;
     RECT  48.613 1.104 48.889 1.752 ;
     RECT  48.613 65.952 48.917 69 ;
     RECT  48.917 65.952 49.187 68.904 ;
     RECT  48.697 3.696 49.285 3.72 ;
     RECT  48.845 30.912 49.313 37.08 ;
     RECT  49.187 65.952 49.393 66.312 ;
     RECT  48.889 1.152 49.529 1.752 ;
     RECT  49.529 1.728 49.661 1.752 ;
     RECT  48.517 5.712 49.705 29.304 ;
     RECT  49.661 1.728 49.744 1.8 ;
     RECT  49.705 5.712 49.745 29.496 ;
     RECT  48.419 40.608 49.777 45.48 ;
     RECT  48.413 46.56 49.777 63.672 ;
     RECT  48.845 38.112 49.849 39.384 ;
     RECT  49.777 40.608 49.849 63.672 ;
     RECT  49.741 64.656 49.849 64.872 ;
     RECT  49.744 1.728 49.997 1.848 ;
     RECT  49.849 38.112 50.093 64.872 ;
     RECT  49.393 65.952 50.093 66.216 ;
     RECT  49.997 1.728 50.105 1.752 ;
     RECT  49.313 30.912 50.245 36.648 ;
     RECT  49.187 67.776 50.245 68.808 ;
     RECT  49.285 2.88 50.281 3.72 ;
     RECT  50.245 67.248 50.293 68.808 ;
     RECT  49.745 6 50.389 29.496 ;
     RECT  50.245 30.672 50.389 36.648 ;
     RECT  50.093 38.112 50.485 66.216 ;
     RECT  50.293 67.248 50.485 68.904 ;
     RECT  50.281 2.88 50.713 3.96 ;
     RECT  50.485 38.112 50.773 68.904 ;
     RECT  50.713 2.88 51.008 4.536 ;
     RECT  50.389 6 51.008 36.648 ;
     RECT  50.773 38.112 51.008 68.952 ;
     RECT  51.008 2.148 51.112 68.952 ;
     RECT  51.112 2.418 51.304 68.952 ;
     RECT  51.304 10.416 51.365 36.648 ;
     RECT  51.304 2.832 51.401 6.84 ;
     RECT  51.401 2.832 51.923 6.024 ;
     RECT  51.304 8.208 51.941 9.048 ;
     RECT  51.923 2.832 51.971 3.432 ;
     RECT  51.304 67.584 52.225 68.952 ;
     RECT  51.923 5.136 52.229 6.024 ;
     RECT  51.304 38.16 52.229 66.216 ;
     RECT  52.225 67.584 52.309 69 ;
     RECT  51.365 10.416 52.333 33.528 ;
     RECT  52.333 10.416 52.369 33.96 ;
     RECT  51.365 34.992 52.369 36.648 ;
     RECT  52.369 10.416 52.405 36.648 ;
     RECT  51.941 9.024 52.441 9.048 ;
     RECT  52.229 38.496 52.441 66.216 ;
     RECT  52.309 67.488 52.441 69 ;
     RECT  52.441 9.024 52.765 9.288 ;
     RECT  52.405 10.416 52.765 36.792 ;
     RECT  52.441 38.496 52.789 69 ;
     RECT  52.765 9.024 53.057 36.792 ;
     RECT  52.229 5.472 53.129 5.496 ;
     RECT  52.789 38.496 53.363 69.096 ;
     RECT  53.057 10.128 53.413 36.792 ;
     RECT  53.413 10.128 53.485 36.84 ;
     RECT  53.057 9.024 53.507 9.096 ;
     RECT  53.485 10.128 53.521 37.32 ;
     RECT  53.363 38.496 53.521 66.408 ;
     RECT  53.557 7.872 54.205 7.896 ;
     RECT  53.521 10.128 54.275 66.408 ;
     RECT  54.275 38.16 54.341 66.408 ;
     RECT  53.363 67.488 54.341 69.096 ;
     RECT  54.341 38.16 54.461 69.096 ;
     RECT  53.507 9.072 54.565 9.096 ;
     RECT  54.275 10.128 54.565 37.032 ;
     RECT  54.205 7.776 55.105 7.896 ;
     RECT  54.565 9.072 55.105 37.032 ;
     RECT  54.461 39.264 55.187 69.096 ;
     RECT  55.105 7.776 55.429 37.032 ;
     RECT  54.461 38.16 55.429 38.184 ;
     RECT  55.573 0.96 55.789 0.984 ;
     RECT  55.429 7.776 55.813 38.184 ;
     RECT  55.813 7.392 55.861 38.184 ;
     RECT  55.187 39.264 55.861 46.344 ;
     RECT  55.573 2.352 55.897 2.376 ;
     RECT  55.789 0.816 55.969 0.984 ;
     RECT  55.897 2.352 56.005 2.52 ;
     RECT  55.861 7.392 56.005 46.344 ;
     RECT  56.005 6.624 56.077 46.344 ;
     RECT  55.969 0.048 56.221 0.984 ;
     RECT  56.005 2.352 56.221 2.904 ;
     RECT  56.197 4.512 56.245 4.536 ;
     RECT  56.221 0.048 56.293 2.904 ;
     RECT  56.245 3.936 56.293 5.016 ;
     RECT  56.077 6 56.293 46.344 ;
     RECT  56.293 0.048 56.408 46.344 ;
     RECT  55.187 47.328 56.408 69.096 ;
     RECT  56.408 0.048 56.704 69.096 ;
     RECT  56.704 47.328 56.801 69.096 ;
     RECT  56.704 0.048 57.769 46.344 ;
     RECT  56.801 47.376 57.769 69.096 ;
     RECT  57.769 0.048 60.077 69.096 ;
     RECT  60.077 0.096 61.229 69.096 ;
     RECT  61.229 0.096 61.273 69 ;
     RECT  61.273 0.096 62.339 68.952 ;
     RECT  62.339 0.096 63.173 68.424 ;
     RECT  63.173 38.64 63.889 68.424 ;
     RECT  63.173 0.096 64.045 37.608 ;
     RECT  63.889 38.64 64.115 68.472 ;
     RECT  64.045 0.144 64.393 37.608 ;
     RECT  64.115 38.64 64.393 67.368 ;
     RECT  64.115 68.352 64.501 68.472 ;
     RECT  64.501 68.352 64.883 68.952 ;
     RECT  64.393 0.144 65.017 67.368 ;
     RECT  64.883 68.4 65.267 68.952 ;
     RECT  65.017 39.36 65.585 67.368 ;
     RECT  65.267 68.88 65.789 68.952 ;
     RECT  65.585 40.56 65.837 67.368 ;
     RECT  65.017 0.144 65.939 38.232 ;
     RECT  65.939 0.144 65.945 20.04 ;
     RECT  65.837 46.224 65.989 67.368 ;
     RECT  65.939 21.264 66.035 38.232 ;
     RECT  66.035 38.016 66.085 38.232 ;
     RECT  65.585 39.36 66.085 39.432 ;
     RECT  66.085 38.016 66.131 39.432 ;
     RECT  65.989 46.224 66.131 67.512 ;
     RECT  65.837 40.56 66.133 45 ;
     RECT  65.945 0.144 66.149 1.224 ;
     RECT  66.035 21.264 66.161 37.032 ;
     RECT  66.133 40.56 66.197 41.016 ;
     RECT  65.945 2.256 66.227 19.944 ;
     RECT  66.161 21.264 66.269 23.4 ;
     RECT  66.161 24.528 66.341 37.032 ;
     RECT  66.227 4.272 66.371 19.944 ;
     RECT  66.371 4.272 66.377 5.736 ;
     RECT  66.377 5.712 66.467 5.736 ;
     RECT  66.377 4.272 66.485 4.392 ;
     RECT  66.131 38.208 66.485 39.432 ;
     RECT  66.131 46.224 66.485 46.248 ;
     RECT  66.131 47.424 66.485 67.512 ;
     RECT  66.371 6.816 66.557 19.944 ;
     RECT  66.269 21.264 66.557 23.352 ;
     RECT  66.341 25.68 66.593 37.032 ;
     RECT  66.149 0.096 66.611 1.224 ;
     RECT  66.485 38.784 66.661 39.432 ;
     RECT  66.197 40.56 66.661 40.776 ;
     RECT  66.557 6.816 66.707 19.368 ;
     RECT  66.557 21.552 66.707 23.352 ;
     RECT  66.341 24.528 66.707 24.648 ;
     RECT  66.661 38.784 66.707 40.776 ;
     RECT  66.485 49.008 66.707 67.512 ;
     RECT  66.485 4.368 66.737 4.392 ;
     RECT  66.707 38.784 66.737 38.808 ;
     RECT  66.133 42.048 66.737 45 ;
     RECT  66.485 47.424 66.737 47.88 ;
     RECT  66.707 49.536 66.737 67.512 ;
     RECT  65.789 68.88 66.757 69 ;
     RECT  66.707 21.552 66.773 22.296 ;
     RECT  66.593 26.016 66.773 37.032 ;
     RECT  66.707 40.176 66.773 40.776 ;
     RECT  66.611 0.096 66.809 1.176 ;
     RECT  66.757 68.784 66.809 69 ;
     RECT  66.227 2.256 66.845 2.904 ;
     RECT  66.707 6.864 66.845 19.368 ;
     RECT  66.707 23.328 66.845 23.352 ;
     RECT  66.773 36.432 66.845 37.032 ;
     RECT  66.773 40.176 66.845 40.2 ;
     RECT  66.737 47.76 66.845 47.88 ;
     RECT  66.809 0.096 66.881 0.648 ;
     RECT  66.809 68.784 66.899 68.952 ;
     RECT  66.845 2.88 66.917 2.904 ;
     RECT  66.737 50.064 66.947 67.512 ;
     RECT  66.899 68.928 67.043 68.952 ;
     RECT  66.947 50.064 67.091 61.224 ;
     RECT  67.091 50.256 67.187 61.224 ;
     RECT  66.881 0.096 67.205 0.504 ;
     RECT  67.205 0.24 67.283 0.504 ;
     RECT  67.187 50.688 67.331 61.224 ;
     RECT  67.283 0.24 67.379 0.264 ;
     RECT  67.331 50.928 67.385 61.224 ;
     RECT  67.385 50.928 67.427 57.384 ;
     RECT  66.947 62.4 67.427 67.512 ;
     RECT  67.427 50.928 67.475 51.192 ;
     RECT  67.427 52.416 67.571 57.384 ;
     RECT  67.571 52.992 67.619 57.384 ;
     RECT  67.427 62.4 67.619 63.288 ;
     RECT  67.427 64.368 67.667 67.512 ;
     RECT  66.845 47.856 67.763 47.88 ;
     RECT  67.619 52.992 67.859 53.256 ;
     RECT  67.619 62.4 67.955 62.712 ;
     RECT  67.667 64.464 67.997 67.512 ;
     RECT  67.475 50.928 68.051 50.952 ;
     RECT  67.619 54.24 68.147 57.384 ;
     RECT  67.859 53.232 68.243 53.256 ;
     RECT  66.737 42.192 68.281 45 ;
     RECT  68.273 68.976 68.357 69 ;
     RECT  68.147 54.336 68.389 57.384 ;
     RECT  67.385 58.416 68.389 61.224 ;
     RECT  67.955 62.4 68.681 62.424 ;
     RECT  66.845 6.96 68.929 19.08 ;
     RECT  68.389 54.336 68.929 61.224 ;
     RECT  66.773 26.016 68.969 35.208 ;
     RECT  68.929 54.336 69.041 61.32 ;
     RECT  68.929 6.864 69.084 19.08 ;
     RECT  68.969 26.064 69.084 35.208 ;
     RECT  68.281 42.192 69.084 45.192 ;
     RECT  69.041 54.48 69.084 61.32 ;
     RECT  67.997 64.464 69.084 67.464 ;
    LAYER M5 ;
     RECT  58.32 0.016 67.464 0.997 ;
     RECT  48.528 0.016 49.8 1.139 ;
     RECT  57.456 0.997 67.464 1.717 ;
     RECT  48.624 1.139 49.8 1.763 ;
     RECT  49.296 1.763 49.8 1.859 ;
     RECT  57.36 1.717 67.464 2.137 ;
     RECT  2.4 2.137 2.52 2.151 ;
     RECT  7.8 2.137 7.92 2.151 ;
     RECT  13.2 2.137 13.32 2.151 ;
     RECT  18.6 2.137 18.72 2.151 ;
     RECT  24 2.137 24.12 2.151 ;
     RECT  29.4 2.137 29.52 2.151 ;
     RECT  34.8 2.137 34.92 2.151 ;
     RECT  40.2 2.137 40.32 2.151 ;
     RECT  45.6 2.137 45.72 2.151 ;
     RECT  51 2.137 51.12 2.151 ;
     RECT  29.4 2.151 29.712 2.485 ;
     RECT  18.6 2.151 18.912 2.821 ;
     RECT  51 2.151 51.312 2.821 ;
     RECT  11.52 2.485 11.544 2.915 ;
     RECT  49.296 1.859 49.32 2.915 ;
     RECT  28.464 2.485 29.712 3.301 ;
     RECT  27.792 3.301 29.712 3.347 ;
     RECT  51 2.821 51.96 3.443 ;
     RECT  56.4 2.137 67.464 3.491 ;
     RECT  22.368 2.245 22.392 3.637 ;
     RECT  22.368 3.637 22.536 3.683 ;
     RECT  29.4 3.347 29.712 3.925 ;
     RECT  56.4 3.491 56.904 3.925 ;
     RECT  57.984 3.491 67.464 4.211 ;
     RECT  13.2 2.151 13.512 4.501 ;
     RECT  56.256 3.925 56.904 4.501 ;
     RECT  11.088 3.925 11.112 4.547 ;
     RECT  44.448 2.581 44.472 4.643 ;
     RECT  47.28 4.117 47.304 4.789 ;
     RECT  3.936 3.397 3.96 5.027 ;
     RECT  2.4 2.151 2.712 5.029 ;
     RECT  13.2 4.501 13.608 5.171 ;
     RECT  22.512 3.683 22.536 5.171 ;
     RECT  51 3.443 51.912 5.171 ;
     RECT  7.8 2.151 8.112 5.173 ;
     RECT  27.792 3.347 27.816 5.173 ;
     RECT  45.6 2.151 45.912 5.461 ;
     RECT  38.16 3.925 38.184 5.507 ;
     RECT  41.568 4.261 41.592 5.603 ;
     RECT  58.128 4.211 67.464 5.605 ;
     RECT  2.4 5.029 3.576 5.747 ;
     RECT  27.408 5.173 27.816 5.747 ;
     RECT  56.208 4.501 57 5.893 ;
     RECT  58.08 5.605 67.464 5.893 ;
     RECT  29.4 3.925 30.024 6.227 ;
     RECT  47.28 4.789 47.928 6.371 ;
     RECT  7.8 5.173 9.096 6.373 ;
     RECT  56.208 5.893 67.464 6.613 ;
     RECT  45.6 5.461 46.008 6.661 ;
     RECT  47.904 6.371 47.928 6.707 ;
     RECT  2.4 5.747 2.712 6.709 ;
     RECT  5.904 2.821 5.928 6.709 ;
     RECT  51 5.171 51.312 6.853 ;
     RECT  49.008 5.989 49.032 6.995 ;
     RECT  50.832 6.853 51.312 6.995 ;
     RECT  31.296 6.181 31.32 7.189 ;
     RECT  40.2 2.151 40.512 7.189 ;
     RECT  7.8 6.373 9.432 7.237 ;
     RECT  31.296 7.189 31.704 7.333 ;
     RECT  5.904 6.709 6.168 7.381 ;
     RECT  7.8 7.237 9.912 7.381 ;
     RECT  34.8 2.151 35.112 7.381 ;
     RECT  56.016 6.613 67.464 7.381 ;
     RECT  5.904 7.381 9.912 7.427 ;
     RECT  2.4 6.709 3.432 7.763 ;
     RECT  6.144 7.427 8.112 7.763 ;
     RECT  29.4 6.227 29.712 7.861 ;
     RECT  55.824 7.381 67.464 7.907 ;
     RECT  55.824 7.907 66.984 8.195 ;
     RECT  18.6 2.821 19.608 8.293 ;
     RECT  40.2 7.189 40.632 8.341 ;
     RECT  13.2 5.171 13.512 8.437 ;
     RECT  38.832 8.005 38.856 8.437 ;
     RECT  49.344 7.621 49.368 8.437 ;
     RECT  51 6.995 51.312 8.437 ;
     RECT  45.6 6.661 46.44 8.579 ;
     RECT  24 2.151 24.312 8.725 ;
     RECT  34.8 7.381 35.256 8.819 ;
     RECT  23.184 8.725 24.312 8.963 ;
     RECT  31.2 7.333 31.704 9.011 ;
     RECT  18.6 8.293 19.752 9.061 ;
     RECT  24 8.963 24.312 9.061 ;
     RECT  37.152 6.805 37.176 9.109 ;
     RECT  38.736 8.437 38.856 9.109 ;
     RECT  56.016 8.195 66.984 9.203 ;
     RECT  68.976 9.205 69 9.395 ;
     RECT  34.8 8.819 35.112 9.541 ;
     RECT  37.152 9.109 38.856 9.731 ;
     RECT  29.232 7.861 29.712 10.165 ;
     RECT  56.016 9.203 66.84 10.307 ;
     RECT  29.184 10.165 29.712 10.309 ;
     RECT  45.6 8.579 46.008 10.501 ;
     RECT  37.152 9.731 38.568 10.643 ;
     RECT  31.296 9.011 31.704 10.691 ;
     RECT  53.472 9.013 53.496 10.741 ;
     RECT  49.344 8.437 51.312 10.789 ;
     RECT  29.184 10.309 29.832 10.837 ;
     RECT  56.016 10.307 66.792 10.883 ;
     RECT  21.744 9.349 21.768 10.981 ;
     RECT  24 9.061 24.408 10.981 ;
     RECT  33.12 10.357 33.144 10.981 ;
     RECT  34.56 9.541 35.112 10.981 ;
     RECT  45.6 10.501 46.104 10.981 ;
     RECT  23.664 10.981 24.408 11.027 ;
     RECT  29.184 10.837 30.36 11.123 ;
     RECT  16.464 5.557 16.488 11.171 ;
     RECT  33.12 10.981 35.112 11.267 ;
     RECT  40.2 8.341 41.016 11.269 ;
     RECT  49.344 10.789 51.432 11.269 ;
     RECT  26.16 5.269 26.184 11.317 ;
     RECT  52.704 10.741 53.496 11.365 ;
     RECT  37.728 10.643 38.568 11.411 ;
     RECT  56.016 10.883 65.976 11.509 ;
     RECT  29.184 11.123 29.832 11.699 ;
     RECT  52.704 11.365 53.88 11.747 ;
     RECT  37.728 11.411 38.376 11.941 ;
     RECT  49.344 11.269 51.48 11.941 ;
     RECT  26.16 11.317 27 11.987 ;
     RECT  33.12 11.267 33.624 12.035 ;
     RECT  17.664 9.061 19.752 12.037 ;
     RECT  5.664 11.317 5.688 12.083 ;
     RECT  23.664 11.027 24.312 12.179 ;
     RECT  24 12.179 24.312 12.229 ;
     RECT  14.976 9.925 15 12.275 ;
     RECT  55.296 11.509 65.976 12.325 ;
     RECT  54.816 12.325 65.976 12.421 ;
     RECT  24 12.229 25.032 12.517 ;
     RECT  26.16 11.987 26.184 12.517 ;
     RECT  21.744 10.981 22.344 12.563 ;
     RECT  40.2 11.269 41.064 12.565 ;
     RECT  39.504 12.565 41.064 12.611 ;
     RECT  7.056 7.763 8.112 12.757 ;
     RECT  9.408 7.427 9.912 12.757 ;
     RECT  7.056 12.757 9.912 12.803 ;
     RECT  29.232 11.699 29.832 12.901 ;
     RECT  37.488 11.941 38.376 13.091 ;
     RECT  24 12.517 26.184 13.093 ;
     RECT  49.152 11.941 51.48 13.093 ;
     RECT  49.152 13.093 51.576 13.139 ;
     RECT  24 13.093 26.904 13.283 ;
     RECT  29.184 12.901 29.832 13.283 ;
     RECT  12.672 8.437 13.512 13.477 ;
     RECT  31.68 10.691 31.704 13.525 ;
     RECT  12.672 13.477 13.656 13.573 ;
     RECT  49.344 13.139 51.576 13.573 ;
     RECT  52.704 11.747 53.496 13.573 ;
     RECT  29.184 13.283 29.712 13.715 ;
     RECT  30.912 13.525 31.704 13.715 ;
     RECT  34.8 11.267 35.112 13.813 ;
     RECT  39.504 12.611 40.512 13.859 ;
     RECT  49.344 13.573 53.496 13.957 ;
     RECT  54.816 12.421 66.12 13.957 ;
     RECT  17.616 12.037 19.752 14.197 ;
     RECT  37.488 13.091 38.28 14.389 ;
     RECT  24 13.283 26.184 14.435 ;
     RECT  33.12 12.035 33.144 14.435 ;
     RECT  39.888 13.859 40.512 14.435 ;
     RECT  29.232 13.715 29.712 14.531 ;
     RECT  22.32 12.563 22.344 14.533 ;
     RECT  37.44 14.389 38.28 14.579 ;
     RECT  49.344 13.957 66.12 14.675 ;
     RECT  7.8 12.803 9.912 14.773 ;
     RECT  37.44 14.579 38.184 14.819 ;
     RECT  30.912 13.715 30.936 14.867 ;
     RECT  12.672 13.573 14.472 14.915 ;
     RECT  34.8 13.813 35.736 14.917 ;
     RECT  54.72 14.675 66.12 15.107 ;
     RECT  5.712 14.677 5.736 15.347 ;
     RECT  16.224 15.061 16.248 15.349 ;
     RECT  17.616 14.197 19.992 15.349 ;
     RECT  24 14.435 25.752 15.395 ;
     RECT  16.224 15.349 19.992 15.443 ;
     RECT  37.44 14.819 38.136 15.443 ;
     RECT  22.32 14.533 22.776 15.445 ;
     RECT  6.96 14.773 9.912 15.587 ;
     RECT  16.224 15.443 19.752 15.635 ;
     RECT  32.736 15.349 32.76 15.733 ;
     RECT  33.744 15.253 33.768 15.733 ;
     RECT  32.736 15.733 33.768 15.925 ;
     RECT  34.8 14.917 36.312 15.925 ;
     RECT  37.44 15.443 37.464 15.925 ;
     RECT  24 15.395 25.56 16.019 ;
     RECT  49.344 14.675 53.496 16.019 ;
     RECT  21.888 15.445 22.776 16.021 ;
     RECT  24 16.019 24.312 16.021 ;
     RECT  45.6 10.981 47.016 16.115 ;
     RECT  7.152 15.587 9.912 16.259 ;
     RECT  44.4 12.757 44.424 16.259 ;
     RECT  46.992 16.115 47.016 16.261 ;
     RECT  12.672 14.915 13.512 16.501 ;
     RECT  32.016 15.925 33.768 16.501 ;
     RECT  34.8 15.925 37.464 16.501 ;
     RECT  45.6 16.115 45.912 16.597 ;
     RECT  29.28 14.531 29.712 16.885 ;
     RECT  54.816 15.107 66.12 16.933 ;
     RECT  32.016 16.501 37.464 16.979 ;
     RECT  21.888 16.021 24.312 16.981 ;
     RECT  25.536 16.019 25.56 16.981 ;
     RECT  49.344 16.019 51.768 16.981 ;
     RECT  52.752 16.019 53.496 16.981 ;
     RECT  54.72 16.933 66.12 16.981 ;
     RECT  21.888 16.981 25.56 17.075 ;
     RECT  46.992 16.261 47.928 17.075 ;
     RECT  49.056 16.981 51.768 17.075 ;
     RECT  22.464 17.075 25.56 17.077 ;
     RECT  26.736 16.405 26.76 17.077 ;
     RECT  39.984 14.435 40.512 17.077 ;
     RECT  22.464 17.077 26.76 17.123 ;
     RECT  29.088 16.885 29.712 17.123 ;
     RECT  44.832 16.597 45.912 17.123 ;
     RECT  49.056 17.075 51.672 17.123 ;
     RECT  52.752 16.981 66.12 17.221 ;
     RECT  12.144 16.501 13.512 17.267 ;
     RECT  49.2 17.123 51.672 17.267 ;
     RECT  32.016 16.979 37.08 17.459 ;
     RECT  39.984 17.077 40.968 17.459 ;
     RECT  42.192 11.941 42.216 17.507 ;
     RECT  7.8 16.259 9.912 17.605 ;
     RECT  25.776 17.123 26.76 17.699 ;
     RECT  25.776 17.699 25.8 17.747 ;
     RECT  52.656 17.221 66.12 17.747 ;
     RECT  32.016 17.459 36.744 17.795 ;
     RECT  22.464 17.123 24.312 18.035 ;
     RECT  29.4 17.123 29.712 18.181 ;
     RECT  7.392 17.605 9.912 18.611 ;
     RECT  39.984 17.459 40.512 18.661 ;
     RECT  12.672 17.267 13.512 18.709 ;
     RECT  49.344 17.267 51.672 18.709 ;
     RECT  16.224 15.635 18.912 18.851 ;
     RECT  38.4 18.709 38.424 19.093 ;
     RECT  39.552 18.661 40.512 19.093 ;
     RECT  49.056 18.709 51.672 19.141 ;
     RECT  52.656 17.747 65.928 19.141 ;
     RECT  12.672 18.709 13.608 19.283 ;
     RECT  32.016 17.795 35.208 19.333 ;
     RECT  49.056 19.141 65.928 19.475 ;
     RECT  27.36 18.709 27.384 19.813 ;
     RECT  28.416 18.181 29.712 19.813 ;
     RECT  27.36 19.813 29.712 19.859 ;
     RECT  22.464 18.035 22.488 19.909 ;
     RECT  31.056 19.333 35.208 19.909 ;
     RECT  36.288 17.795 36.744 19.909 ;
     RECT  46.992 17.075 47.016 19.957 ;
     RECT  46.992 19.957 47.16 20.003 ;
     RECT  14.64 18.229 14.664 20.101 ;
     RECT  23.808 18.035 24.312 20.149 ;
     RECT  29.28 19.859 29.712 20.149 ;
     RECT  31.056 19.909 36.744 20.149 ;
     RECT  29.28 20.149 36.744 20.195 ;
     RECT  27.36 19.859 28.2 20.339 ;
     RECT  45.6 17.123 45.912 20.341 ;
     RECT  7.8 18.611 9.912 20.437 ;
     RECT  38.4 19.093 40.512 20.485 ;
     RECT  49.344 19.475 65.928 20.485 ;
     RECT  14.496 20.101 14.664 20.579 ;
     RECT  20.064 19.765 20.088 20.579 ;
     RECT  48.48 20.485 65.928 20.579 ;
     RECT  25.872 20.581 25.896 20.723 ;
     RECT  37.728 20.485 40.512 20.723 ;
     RECT  6.096 19.861 6.12 21.013 ;
     RECT  48.48 20.579 65.736 21.059 ;
     RECT  29.28 20.195 36.168 21.107 ;
     RECT  43.248 19.909 43.272 21.155 ;
     RECT  52.752 21.059 65.736 21.155 ;
     RECT  12.672 19.283 13.512 21.157 ;
     RECT  14.496 20.579 14.52 21.157 ;
     RECT  7.8 20.437 10.872 21.203 ;
     RECT  48.48 21.059 51.432 21.203 ;
     RECT  6.096 21.013 6.696 21.299 ;
     RECT  12.672 21.157 14.52 21.299 ;
     RECT  29.28 21.107 35.208 21.397 ;
     RECT  27.552 20.339 28.2 21.637 ;
     RECT  7.8 21.203 9.912 21.683 ;
     RECT  16.944 18.851 18.912 21.683 ;
     RECT  45.6 20.341 46.056 21.779 ;
     RECT  23.808 20.149 24.408 21.973 ;
     RECT  17.856 21.683 18.912 22.019 ;
     RECT  29.232 21.397 35.208 22.069 ;
     RECT  52.752 21.155 65.544 22.165 ;
     RECT  66.672 21.541 66.696 22.165 ;
     RECT  6.672 21.299 6.696 22.259 ;
     RECT  23.808 21.973 24.936 22.355 ;
     RECT  27.552 21.637 28.248 22.499 ;
     RECT  27.552 22.499 28.2 22.643 ;
     RECT  20.016 21.349 20.04 22.693 ;
     RECT  19.92 22.693 20.04 22.739 ;
     RECT  14.496 21.299 14.52 22.741 ;
     RECT  37.728 20.723 37.752 22.741 ;
     RECT  39.024 20.723 40.512 22.787 ;
     RECT  4.512 21.397 4.536 22.835 ;
     RECT  43.872 22.693 43.896 22.835 ;
     RECT  7.8 21.683 8.112 22.885 ;
     RECT  9.408 21.683 9.912 22.885 ;
     RECT  39.312 22.787 40.512 23.077 ;
     RECT  49.344 21.203 51.432 23.125 ;
     RECT  52.752 22.165 66.696 23.125 ;
     RECT  39.312 23.077 41.016 23.315 ;
     RECT  12.672 21.299 13.512 23.317 ;
     RECT  14.496 22.741 14.904 23.317 ;
     RECT  24 22.355 24.936 23.317 ;
     RECT  19.92 22.739 19.944 23.411 ;
     RECT  12.672 23.317 14.904 23.701 ;
     RECT  22.464 19.909 22.776 23.701 ;
     RECT  37.248 22.741 37.752 23.747 ;
     RECT  45.6 21.779 46.008 23.893 ;
     RECT  47.136 20.003 47.16 23.893 ;
     RECT  7.8 22.885 10.584 23.987 ;
     RECT  27.648 22.643 28.2 23.987 ;
     RECT  37.584 23.747 37.752 23.987 ;
     RECT  42.192 23.317 42.216 23.987 ;
     RECT  29.232 22.069 35.256 24.179 ;
     RECT  39.312 23.315 40.512 24.277 ;
     RECT  9.408 23.987 10.584 24.467 ;
     RECT  29.232 24.179 33.768 24.467 ;
     RECT  5.424 23.317 5.448 24.469 ;
     RECT  49.344 23.125 66.696 24.613 ;
     RECT  21.12 22.741 21.144 24.757 ;
     RECT  37.584 23.987 37.608 25.045 ;
     RECT  39.312 24.277 40.632 25.091 ;
     RECT  5.04 24.469 5.448 25.093 ;
     RECT  5.04 25.093 5.688 25.139 ;
     RECT  12.672 23.701 15.048 25.139 ;
     RECT  29.232 24.467 30.84 25.187 ;
     RECT  32.736 24.467 33.768 25.237 ;
     RECT  34.8 24.179 35.256 25.237 ;
     RECT  32.736 25.237 35.256 25.283 ;
     RECT  37.584 25.045 37.896 25.285 ;
     RECT  28.176 23.987 28.2 25.427 ;
     RECT  29.232 25.187 30.216 25.475 ;
     RECT  7.8 23.987 8.112 25.573 ;
     RECT  37.008 25.285 37.896 25.667 ;
     RECT  5.136 25.139 5.688 25.715 ;
     RECT  22.464 23.701 23.016 25.715 ;
     RECT  42.48 25.045 42.504 25.715 ;
     RECT  7.8 25.573 8.232 25.907 ;
     RECT  18.6 22.019 18.912 26.149 ;
     RECT  45.6 23.893 47.16 26.243 ;
     RECT  17.328 25.573 17.352 26.629 ;
     RECT  40.2 25.091 40.632 26.675 ;
     RECT  32.736 25.283 35.112 26.725 ;
     RECT  22.464 25.715 22.776 26.819 ;
     RECT  16.896 26.629 17.352 26.867 ;
     RECT  20.496 24.757 21.144 26.867 ;
     RECT  5.136 25.715 5.16 26.915 ;
     RECT  20.496 26.867 20.52 26.917 ;
     RECT  49.248 24.613 66.696 26.965 ;
     RECT  45.6 26.243 46.872 27.061 ;
     RECT  32.112 26.725 35.112 27.155 ;
     RECT  48.768 26.965 66.696 27.155 ;
     RECT  20.448 26.917 20.52 27.205 ;
     RECT  28.224 26.773 28.248 27.205 ;
     RECT  29.232 25.475 29.976 27.205 ;
     RECT  28.224 27.205 29.976 27.251 ;
     RECT  16.896 26.867 16.92 27.347 ;
     RECT  49.344 27.155 66.696 27.395 ;
     RECT  10.896 25.189 10.92 27.733 ;
     RECT  44.976 27.061 46.872 27.829 ;
     RECT  10.896 27.733 10.968 27.875 ;
     RECT  37.632 25.667 37.896 27.877 ;
     RECT  18.48 26.149 18.912 27.923 ;
     RECT  22.656 26.819 22.776 28.019 ;
     RECT  32.112 27.155 33.432 28.163 ;
     RECT  7.8 25.907 8.112 28.453 ;
     RECT  37.632 27.877 38.28 28.643 ;
     RECT  34.416 27.155 35.112 28.739 ;
     RECT  18.6 27.923 18.912 29.029 ;
     RECT  49.344 27.395 51.432 29.029 ;
     RECT  52.416 27.395 66.696 29.029 ;
     RECT  43.008 27.877 43.032 29.123 ;
     RECT  44.976 27.829 47.304 29.123 ;
     RECT  28.704 27.251 29.976 29.173 ;
     RECT  20.064 27.205 20.52 29.317 ;
     RECT  38.256 28.643 38.28 29.363 ;
     RECT  22.752 28.019 22.776 29.461 ;
     RECT  24 23.317 25.08 29.461 ;
     RECT  49.344 29.029 66.696 29.699 ;
     RECT  10.944 27.875 10.968 29.795 ;
     RECT  22.752 29.461 25.08 29.987 ;
     RECT  7.488 28.453 8.112 30.037 ;
     RECT  9.408 24.467 9.912 30.227 ;
     RECT  28.704 29.173 30.744 30.275 ;
     RECT  45.6 29.123 47.304 30.275 ;
     RECT  19.968 29.317 20.52 30.371 ;
     RECT  6.576 30.037 8.112 30.515 ;
     RECT  17.136 29.509 17.16 30.563 ;
     RECT  12.672 25.139 14.904 30.565 ;
     RECT  7.488 30.515 8.112 30.709 ;
     RECT  49.344 29.699 65.544 30.757 ;
     RECT  66.576 29.699 66.696 30.757 ;
     RECT  19.968 30.371 20.472 30.803 ;
     RECT  5.136 29.365 5.16 30.851 ;
     RECT  68.928 30.853 68.952 31.139 ;
     RECT  7.488 30.709 8.808 31.187 ;
     RECT  18.288 29.029 18.912 31.189 ;
     RECT  19.968 30.803 20.184 31.379 ;
     RECT  2.4 7.763 2.712 31.477 ;
     RECT  34.8 28.739 35.112 31.525 ;
     RECT  20.16 31.379 20.184 31.715 ;
     RECT  28.704 30.275 29.976 31.813 ;
     RECT  23.904 29.987 25.08 31.861 ;
     RECT  17.376 31.189 18.912 31.955 ;
     RECT  28.464 31.813 29.976 31.955 ;
     RECT  10.896 31.525 10.92 32.195 ;
     RECT  22.752 29.987 22.776 32.197 ;
     RECT  23.904 31.861 25.704 32.197 ;
     RECT  34.8 31.525 35.352 32.339 ;
     RECT  38.736 32.197 38.76 32.339 ;
     RECT  2.4 31.477 2.808 32.387 ;
     RECT  17.376 31.955 17.4 32.483 ;
     RECT  49.344 30.757 66.696 33.013 ;
     RECT  12.576 30.565 14.904 33.059 ;
     RECT  7.488 31.187 8.112 33.107 ;
     RECT  12.576 33.059 13.608 33.107 ;
     RECT  22.752 32.197 25.704 33.107 ;
     RECT  28.704 31.955 29.976 33.107 ;
     RECT  12.672 33.107 13.608 33.155 ;
     RECT  9.888 30.227 9.912 33.203 ;
     RECT  24 33.107 25.704 33.251 ;
     RECT  29.28 33.107 29.976 33.299 ;
     RECT  14.688 33.059 14.904 33.349 ;
     RECT  49.008 33.013 66.696 33.493 ;
     RECT  45.6 30.275 46.872 33.541 ;
     RECT  32.736 28.163 33.432 33.683 ;
     RECT  36.672 31.861 36.696 33.683 ;
     RECT  7.536 33.107 8.112 34.355 ;
     RECT  32.736 33.683 32.76 34.355 ;
     RECT  44.928 33.541 46.872 34.355 ;
     RECT  13.2 33.155 13.608 34.453 ;
     RECT  14.688 33.349 15.096 34.453 ;
     RECT  0.192 34.453 0.216 34.739 ;
     RECT  22.752 33.107 22.776 34.741 ;
     RECT  34.8 32.339 35.112 34.741 ;
     RECT  22.608 34.741 22.776 34.787 ;
     RECT  48.432 33.493 66.696 34.787 ;
     RECT  24 33.251 25.08 34.789 ;
     RECT  49.344 34.787 66.696 34.835 ;
     RECT  13.2 34.453 15.096 34.885 ;
     RECT  24 34.789 25.128 35.029 ;
     RECT  24 35.029 25.656 35.315 ;
     RECT  13.008 34.885 15.096 35.317 ;
     RECT  42.768 34.933 42.792 35.363 ;
     RECT  45.6 34.355 46.872 35.363 ;
     RECT  29.4 33.299 29.976 35.509 ;
     RECT  29.088 35.509 29.976 35.747 ;
     RECT  12.96 35.317 15.096 35.845 ;
     RECT  12.96 35.845 15.384 35.939 ;
     RECT  13.2 35.939 15.384 36.035 ;
     RECT  65.952 34.835 66.696 36.035 ;
     RECT  14.88 36.035 15.24 36.083 ;
     RECT  49.344 34.835 64.968 36.085 ;
     RECT  45.6 35.363 45.912 36.373 ;
     RECT  48 35.845 48.024 36.515 ;
     RECT  49.344 36.085 65.304 36.611 ;
     RECT  40.2 26.675 40.512 36.757 ;
     RECT  52.416 36.611 65.304 36.803 ;
     RECT  17.136 36.565 17.16 36.851 ;
     RECT  13.2 36.035 13.848 36.949 ;
     RECT  11.28 33.013 11.304 37.045 ;
     RECT  44.832 36.373 45.912 37.189 ;
     RECT  11.28 37.045 11.928 37.523 ;
     RECT  21.12 35.125 21.144 37.573 ;
     RECT  22.608 34.787 22.632 37.573 ;
     RECT  52.8 36.803 65.304 37.573 ;
     RECT  66.576 36.035 66.696 37.573 ;
     RECT  40.2 36.757 41.064 37.667 ;
     RECT  47.664 37.189 47.688 37.957 ;
     RECT  31.44 36.373 31.464 38.005 ;
     RECT  44.736 37.189 45.912 38.005 ;
     RECT  44.448 38.005 45.912 38.147 ;
     RECT  44.448 38.147 44.472 38.149 ;
     RECT  31.104 38.005 31.464 38.195 ;
     RECT  29.4 35.747 29.976 38.243 ;
     RECT  27.936 37.093 27.96 38.629 ;
     RECT  27.504 38.629 27.96 38.675 ;
     RECT  24 35.315 25.08 38.725 ;
     RECT  24 38.725 25.992 38.917 ;
     RECT  27.504 38.675 27.528 38.917 ;
     RECT  5.136 38.485 5.16 39.011 ;
     RECT  47.664 37.957 47.928 39.203 ;
     RECT  0.144 38.581 0.168 39.299 ;
     RECT  24 38.917 27.528 39.299 ;
     RECT  11.28 37.523 11.304 39.301 ;
     RECT  21.12 37.573 22.632 39.301 ;
     RECT  9.408 34.741 9.432 39.349 ;
     RECT  52.8 37.573 66.696 39.395 ;
     RECT  43.488 38.149 44.472 39.443 ;
     RECT  44.448 39.443 44.472 39.491 ;
     RECT  49.344 36.611 51.312 39.589 ;
     RECT  31.104 38.195 31.128 39.683 ;
     RECT  2.4 32.387 2.712 39.685 ;
     RECT  7.8 34.355 8.112 39.733 ;
     RECT  9.12 39.349 9.432 39.733 ;
     RECT  7.8 39.733 9.432 39.779 ;
     RECT  27.504 39.299 27.528 39.877 ;
     RECT  7.8 39.779 9.144 39.923 ;
     RECT  27.504 39.877 27.816 40.405 ;
     RECT  52.8 39.395 65.4 40.405 ;
     RECT  45.504 38.147 45.912 40.981 ;
     RECT  5.136 40.837 5.16 41.027 ;
     RECT  37.296 40.405 37.32 41.027 ;
     RECT  10.416 39.301 11.304 41.075 ;
     RECT  12.96 36.949 13.848 41.075 ;
     RECT  27.312 40.405 27.816 41.075 ;
     RECT  52.8 40.405 65.544 41.077 ;
     RECT  47.664 39.203 47.688 41.125 ;
     RECT  29.4 38.243 29.712 41.221 ;
     RECT  52.656 41.077 65.544 41.557 ;
     RECT  66.576 39.395 66.696 41.557 ;
     RECT  2.4 39.685 2.808 41.893 ;
     RECT  28.896 41.221 29.712 41.939 ;
     RECT  45.072 40.981 45.912 41.989 ;
     RECT  2.4 41.893 2.856 42.035 ;
     RECT  32.448 39.877 32.472 42.037 ;
     RECT  32.304 42.037 32.472 42.133 ;
     RECT  44.448 41.989 45.912 42.133 ;
     RECT  49.344 39.589 51.432 42.133 ;
     RECT  52.656 41.557 66.696 42.133 ;
     RECT  13.2 41.075 13.848 42.419 ;
     RECT  30.768 41.461 30.792 42.467 ;
     RECT  18.6 31.955 18.912 42.709 ;
     RECT  24 39.299 25.992 42.709 ;
     RECT  34.272 34.741 35.112 42.709 ;
     RECT  44.4 42.133 45.912 42.757 ;
     RECT  20.784 39.301 22.632 43.139 ;
     RECT  49.344 42.133 66.696 43.285 ;
     RECT  3.936 43.477 3.96 43.619 ;
     RECT  49.248 43.285 66.696 43.861 ;
     RECT  48.864 43.861 66.696 43.907 ;
     RECT  42.24 42.133 42.264 43.909 ;
     RECT  27.792 41.075 27.816 43.955 ;
     RECT  48.864 43.907 64.392 43.955 ;
     RECT  42.192 43.909 42.264 44.387 ;
     RECT  31.824 42.133 32.472 44.437 ;
     RECT  18.384 42.709 18.912 44.627 ;
     RECT  0.144 44.053 0.168 44.723 ;
     RECT  40.2 37.667 40.512 44.725 ;
     RECT  5.232 43.861 5.256 44.915 ;
     RECT  48.864 43.955 64.344 44.965 ;
     RECT  65.472 43.907 66.696 44.965 ;
     RECT  7.8 39.923 9.096 45.011 ;
     RECT  20.784 43.139 20.904 45.059 ;
     RECT  36.624 42.709 36.648 45.061 ;
     RECT  36.48 45.061 36.648 45.107 ;
     RECT  44.4 42.757 46.008 45.107 ;
     RECT  20.784 45.059 20.808 45.155 ;
     RECT  24 42.709 26.616 45.155 ;
     RECT  7.8 45.011 9 45.299 ;
     RECT  31.824 44.437 32.712 45.301 ;
     RECT  31.296 45.301 32.712 45.491 ;
     RECT  15.072 36.083 15.24 45.541 ;
     RECT  47.184 41.125 47.688 45.541 ;
     RECT  48.864 44.965 66.696 45.541 ;
     RECT  32.304 45.491 32.712 45.635 ;
     RECT  24 45.155 26.568 45.731 ;
     RECT  32.688 45.635 32.712 46.021 ;
     RECT  33.84 42.709 35.112 46.021 ;
     RECT  11.28 41.075 11.304 46.213 ;
     RECT  7.8 45.299 8.112 46.357 ;
     RECT  45.6 45.107 46.008 46.405 ;
     RECT  42.24 44.387 42.264 46.451 ;
     RECT  36.48 45.107 36.504 46.501 ;
     RECT  11.088 46.213 11.304 46.645 ;
     RECT  44.4 45.107 44.424 46.693 ;
     RECT  10.944 46.645 11.304 46.883 ;
     RECT  11.088 46.883 11.304 47.123 ;
     RECT  44.4 46.693 44.472 47.269 ;
     RECT  45.456 46.405 46.008 47.269 ;
     RECT  7.8 46.357 8.856 47.315 ;
     RECT  32.688 46.021 35.112 47.317 ;
     RECT  36.48 46.501 37.32 47.317 ;
     RECT  44.4 47.269 46.008 47.317 ;
     RECT  32.688 47.317 37.32 47.363 ;
     RECT  47.184 45.541 66.696 47.411 ;
     RECT  20.064 46.165 20.088 47.507 ;
     RECT  44.4 47.317 46.104 47.747 ;
     RECT  26.208 45.731 26.568 47.749 ;
     RECT  15.072 45.541 15.384 47.845 ;
     RECT  44.448 47.747 46.104 47.891 ;
     RECT  11.28 47.123 11.304 48.227 ;
     RECT  15.024 47.845 15.384 48.323 ;
     RECT  40.2 44.725 41.16 48.421 ;
     RECT  44.976 47.891 46.104 48.467 ;
     RECT  13.2 42.419 13.656 48.515 ;
     RECT  44.976 48.467 46.008 48.515 ;
     RECT  31.296 45.491 31.32 48.611 ;
     RECT  22.608 43.139 22.632 48.949 ;
     RECT  21.888 48.949 22.632 49.043 ;
     RECT  47.664 47.411 66.696 49.043 ;
     RECT  29.4 41.939 29.712 49.045 ;
     RECT  29.28 49.045 29.712 49.427 ;
     RECT  38.448 47.269 38.472 49.573 ;
     RECT  4.608 45.397 4.632 49.619 ;
     RECT  40.2 48.421 41.592 49.861 ;
     RECT  38.448 49.573 38.808 50.003 ;
     RECT  40.2 49.861 41.736 50.051 ;
     RECT  47.664 49.043 66.12 50.053 ;
     RECT  67.728 47.845 67.752 50.053 ;
     RECT  16.512 48.421 16.536 50.195 ;
     RECT  25.632 47.749 26.568 50.195 ;
     RECT  38.784 50.003 38.808 50.195 ;
     RECT  18.6 44.627 18.912 50.917 ;
     RECT  47.664 50.053 67.752 50.917 ;
     RECT  33.648 47.363 37.32 50.963 ;
     RECT  47.664 50.917 68.04 50.965 ;
     RECT  26.544 50.195 26.568 51.253 ;
     RECT  44.976 48.515 45.912 51.253 ;
     RECT  46.944 50.965 68.04 51.253 ;
     RECT  34.176 50.963 37.32 51.299 ;
     RECT  29.4 49.427 29.712 51.637 ;
     RECT  28.8 51.637 29.712 51.685 ;
     RECT  24 45.731 24.504 51.829 ;
     RECT  18.48 50.917 18.912 51.923 ;
     RECT  44.976 51.253 68.04 51.923 ;
     RECT  18.6 51.923 18.912 51.973 ;
     RECT  2.4 42.035 2.712 52.021 ;
     RECT  26.544 51.253 26.904 52.117 ;
     RECT  21.888 49.043 21.912 52.211 ;
     RECT  32.928 50.965 32.952 52.453 ;
     RECT  16.512 51.205 16.536 52.499 ;
     RECT  32.928 52.453 33.048 52.499 ;
     RECT  33.024 52.499 33.048 52.595 ;
     RECT  44.976 51.923 46.152 52.595 ;
     RECT  37.296 51.299 37.32 52.597 ;
     RECT  31.248 51.637 31.272 52.979 ;
     RECT  15.072 48.323 15.384 52.981 ;
     RECT  24 51.829 25.128 52.981 ;
     RECT  37.152 52.597 37.32 52.981 ;
     RECT  47.664 51.923 68.04 53.221 ;
     RECT  2.4 52.021 2.856 53.267 ;
     RECT  34.176 51.299 36.024 53.365 ;
     RECT  45.6 52.595 46.152 53.509 ;
     RECT  13.2 48.515 13.608 53.557 ;
     RECT  14.928 52.981 15.384 53.557 ;
     RECT  23.376 52.981 25.128 53.557 ;
     RECT  9.6 52.741 9.624 53.603 ;
     RECT  28.8 51.685 29.832 53.795 ;
     RECT  13.2 53.557 15.384 53.845 ;
     RECT  13.104 53.845 15.384 53.891 ;
     RECT  15.072 53.891 15.384 54.131 ;
     RECT  40.2 50.051 41.16 54.133 ;
     RECT  47.664 53.221 68.232 54.227 ;
     RECT  23.376 53.557 25.464 54.323 ;
     RECT  13.104 53.891 13.992 54.371 ;
     RECT  31.488 53.557 31.896 54.371 ;
     RECT  40.2 54.133 41.592 54.371 ;
     RECT  45.6 53.509 46.44 54.421 ;
     RECT  26.544 52.117 27.144 54.467 ;
     RECT  7.8 47.315 8.112 54.565 ;
     RECT  5.088 52.069 5.112 54.611 ;
     RECT  7.44 54.565 8.112 54.709 ;
     RECT  3.744 54.325 3.768 54.755 ;
     RECT  47.904 54.227 68.232 54.947 ;
     RECT  37.152 52.981 37.656 54.995 ;
     RECT  18.6 51.973 19.848 55.141 ;
     RECT  28.848 53.795 29.832 55.141 ;
     RECT  7.44 54.709 8.28 55.283 ;
     RECT  37.632 54.995 37.656 55.285 ;
     RECT  23.376 54.323 25.032 55.331 ;
     RECT  2.4 53.267 2.712 55.381 ;
     RECT  28.752 55.141 29.832 55.477 ;
     RECT  31.584 54.371 31.896 55.525 ;
     RECT  13.104 54.371 13.608 55.813 ;
     RECT  15.072 54.131 15.096 55.813 ;
     RECT  2.4 55.381 2.952 55.859 ;
     RECT  28.752 55.477 29.928 55.907 ;
     RECT  18.6 55.141 20.76 56.003 ;
     RECT  23.904 55.331 25.032 56.003 ;
     RECT  37.632 55.285 38.04 56.195 ;
     RECT  20.736 56.003 20.76 56.243 ;
     RECT  29.4 55.907 29.928 56.389 ;
     RECT  37.632 56.195 37.8 56.579 ;
     RECT  18.6 56.003 18.912 56.581 ;
     RECT  23.904 56.003 24.552 57.011 ;
     RECT  23.904 57.011 24.312 57.059 ;
     RECT  47.904 54.947 47.928 57.059 ;
     RECT  13.104 55.813 15.096 57.397 ;
     RECT  13.104 57.397 15.624 57.443 ;
     RECT  40.2 54.371 41.304 57.443 ;
     RECT  29.4 56.389 30.12 57.541 ;
     RECT  49.2 54.947 68.232 57.635 ;
     RECT  7.44 55.283 8.112 58.117 ;
     RECT  45.6 54.421 46.488 58.117 ;
     RECT  13.2 57.443 15.624 58.355 ;
     RECT  13.2 58.355 15.096 58.403 ;
     RECT  6.24 55.189 6.264 58.643 ;
     RECT  49.392 57.635 68.232 58.645 ;
     RECT  11.376 58.549 11.4 58.693 ;
     RECT  24 57.059 24.312 58.693 ;
     RECT  13.2 58.403 14.136 58.739 ;
     RECT  26.544 54.467 26.568 58.739 ;
     RECT  31.584 55.525 32.76 58.883 ;
     RECT  33.936 53.365 36.024 58.885 ;
     RECT  49.344 58.645 68.232 59.029 ;
     RECT  26.928 59.077 27.096 59.219 ;
     RECT  11.376 58.693 11.88 59.315 ;
     RECT  49.008 59.029 68.232 59.315 ;
     RECT  43.968 59.221 43.992 59.507 ;
     RECT  29.4 57.541 30.216 59.555 ;
     RECT  24 58.693 24.408 59.605 ;
     RECT  11.376 59.315 11.4 59.797 ;
     RECT  45.6 58.117 46.728 59.797 ;
     RECT  33.936 58.885 36.216 59.987 ;
     RECT  7.44 58.117 8.808 60.035 ;
     RECT  10.896 59.797 11.4 60.035 ;
     RECT  31.824 58.883 32.76 60.035 ;
     RECT  23.424 59.605 24.408 60.421 ;
     RECT  29.4 59.555 30.12 60.515 ;
     RECT  31.824 60.035 32.664 60.709 ;
     RECT  13.2 58.739 13.656 60.805 ;
     RECT  40.2 57.443 40.512 60.805 ;
     RECT  44.592 60.757 44.616 60.899 ;
     RECT  10.896 60.035 10.92 60.947 ;
     RECT  13.2 60.805 14.376 60.947 ;
     RECT  40.2 60.805 41.064 60.947 ;
     RECT  31.632 60.709 32.664 60.995 ;
     RECT  27.024 59.219 27.096 61.141 ;
     RECT  26.736 61.141 27.096 61.283 ;
     RECT  40.2 60.947 40.512 61.381 ;
     RECT  29.4 60.515 29.976 61.907 ;
     RECT  27.024 61.283 27.096 61.909 ;
     RECT  49.344 59.315 68.232 62.149 ;
     RECT  6.096 60.949 6.12 62.195 ;
     RECT  39.696 61.381 40.512 62.195 ;
     RECT  43.296 60.757 43.32 62.195 ;
     RECT  42.096 60.373 42.12 62.435 ;
     RECT  32.352 60.995 32.664 62.677 ;
     RECT  21.12 61.957 21.144 62.723 ;
     RECT  23.424 60.421 25.08 62.723 ;
     RECT  45.6 59.797 46.824 62.723 ;
     RECT  13.2 60.947 13.656 62.725 ;
     RECT  13.056 62.725 13.656 62.771 ;
     RECT  31.776 62.677 32.664 62.771 ;
     RECT  48.96 62.149 68.232 62.771 ;
     RECT  44.448 61.381 44.472 62.819 ;
     RECT  18.336 56.581 18.912 63.011 ;
     RECT  47.904 60.181 47.928 63.299 ;
     RECT  31.776 62.771 32.376 63.539 ;
     RECT  7.44 60.035 8.112 63.587 ;
     RECT  45.6 62.723 46.488 63.635 ;
     RECT  9.408 62.677 9.432 63.827 ;
     RECT  24 62.723 25.08 64.019 ;
     RECT  32.352 63.539 32.376 64.163 ;
     RECT  33.936 59.987 36.024 64.307 ;
     RECT  32.688 64.165 32.712 64.357 ;
     RECT  37.776 56.579 37.8 64.451 ;
     RECT  27.024 61.909 27.48 64.693 ;
     RECT  7.584 63.587 8.112 64.835 ;
     RECT  33.936 64.307 35.112 64.835 ;
     RECT  47.952 63.493 47.976 64.979 ;
     RECT  29.4 61.907 29.712 64.981 ;
     RECT  26.832 64.693 27.48 65.267 ;
     RECT  20.688 63.589 20.712 65.363 ;
     RECT  32.688 64.357 32.808 65.363 ;
     RECT  32.784 65.363 32.808 65.555 ;
     RECT  4.128 63.781 4.152 65.653 ;
     RECT  4.128 65.653 4.92 65.699 ;
     RECT  27.456 65.267 27.48 66.179 ;
     RECT  17.28 63.061 17.304 66.227 ;
     RECT  49.344 62.771 68.232 66.323 ;
     RECT  29.4 64.981 30.264 66.371 ;
     RECT  4.896 65.699 4.92 66.611 ;
     RECT  13.056 62.771 13.512 66.803 ;
     RECT  2.4 55.859 2.712 66.969 ;
     RECT  7.8 64.835 8.112 66.969 ;
     RECT  13.2 66.803 13.512 66.969 ;
     RECT  18.6 63.011 18.912 66.969 ;
     RECT  24 64.019 24.312 66.969 ;
     RECT  29.4 66.371 29.712 66.969 ;
     RECT  34.8 64.835 35.112 66.969 ;
     RECT  40.2 62.195 40.512 66.969 ;
     RECT  45.6 63.635 45.912 66.969 ;
     RECT  2.4 66.969 2.52 66.983 ;
     RECT  7.8 66.969 7.92 66.983 ;
     RECT  13.2 66.969 13.32 66.983 ;
     RECT  18.6 66.969 18.72 66.983 ;
     RECT  24 66.969 24.12 66.983 ;
     RECT  29.4 66.969 29.52 66.983 ;
     RECT  34.8 66.969 34.92 66.983 ;
     RECT  40.2 66.969 40.32 66.983 ;
     RECT  45.6 66.969 45.72 66.983 ;
     RECT  48.336 66.517 48.36 67.237 ;
     RECT  48.144 67.237 49.176 67.765 ;
     RECT  50.256 66.323 68.232 67.765 ;
     RECT  48.144 67.765 68.232 68.965 ;
     RECT  48.144 68.965 68.328 69.072 ;
     RECT  52.8 69.072 52.824 69.107 ;
  END
END ot_hgi_dma_back_static_vp4_controller
END LIBRARY
